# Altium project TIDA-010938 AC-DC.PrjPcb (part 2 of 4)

## Sheet TIDA-010938 AC-DC_Power Stage_BranchB.SchDoc
size 558 x 431 mm; Date: Not shown in title block; ApprovedBy: Not shown in title block; CheckedBy: Not shown in title block; Author: Not shown in title block; CompanyName: Not shown in title block; Engineer: Not shown in title block; Organization: Not shown in title block; Address1: Not shown in title block; Address2: Not shown in title block; Address3: Not shown in title block; Address4: Not shown in title block; DocumentNumber: 3; Revision: Use project parameter SCH_Rev; SheetNumber: 4; SheetTotal: 11; PageSetup: Record=PageOptions¦CenterHorizontal=True¦CenterVertical=True¦PrintScale=1.00¦XCorrection=1.00¦YCorrection=1.00¦PrintKind=0¦BorderSize=5000000¦LeftOffset=0¦BottomOffset=0¦Orientation=2¦PaperLength=1000¦PaperWidth=1000¦Scale=100¦PaperSource=15¦PrintQuality=600¦MediaType=1¦DitherType=10¦PaperKind=Letter¦PrintScaleMode=1

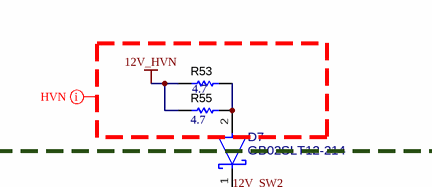
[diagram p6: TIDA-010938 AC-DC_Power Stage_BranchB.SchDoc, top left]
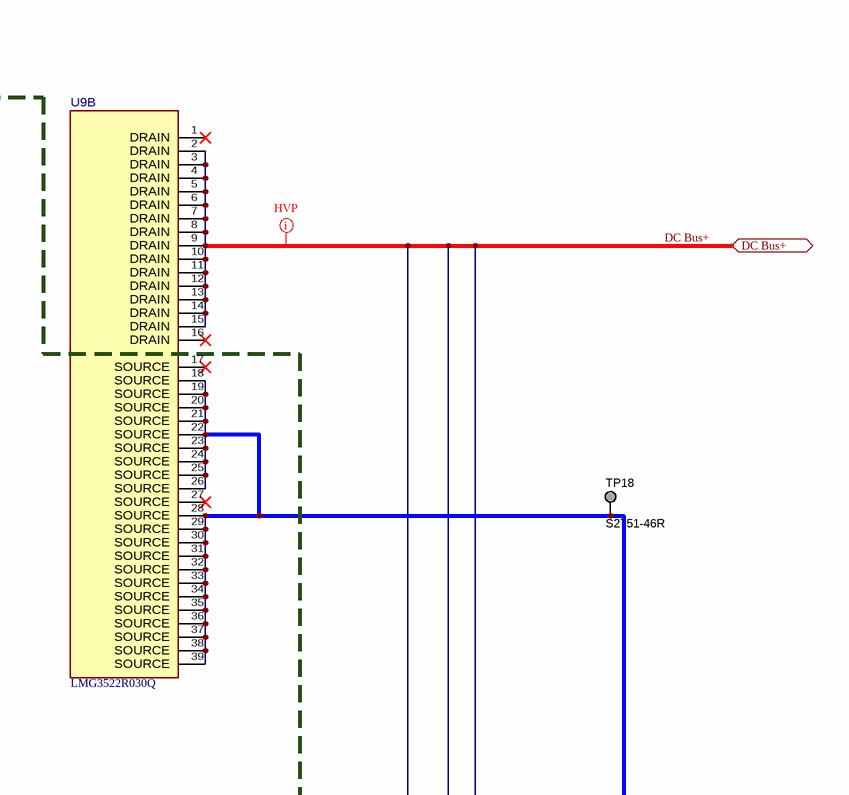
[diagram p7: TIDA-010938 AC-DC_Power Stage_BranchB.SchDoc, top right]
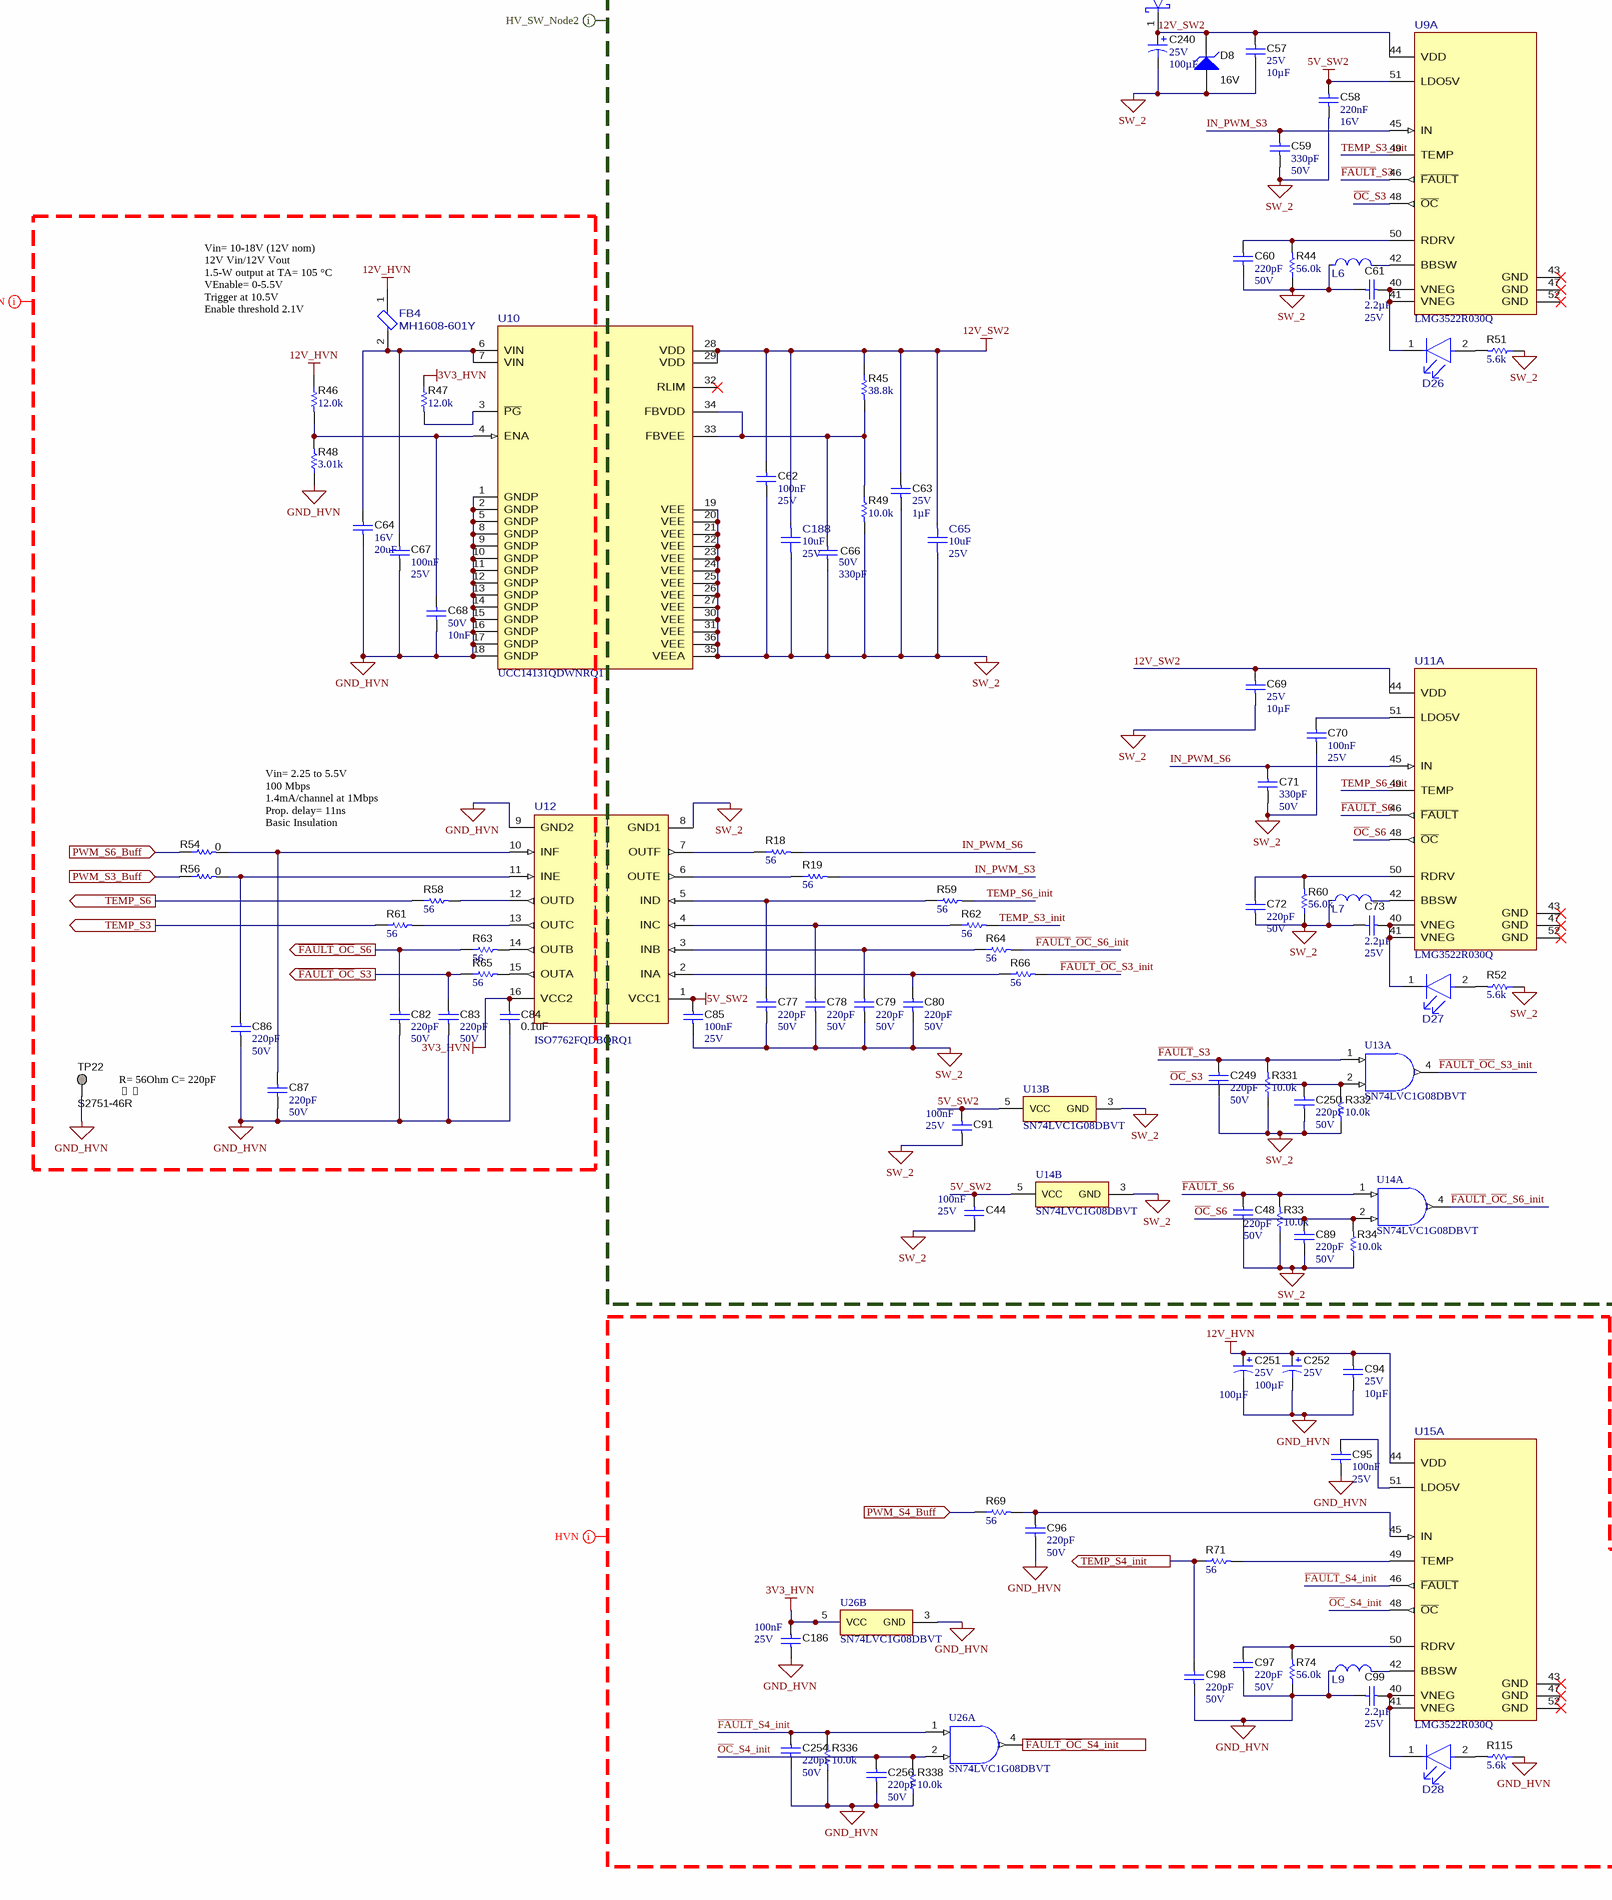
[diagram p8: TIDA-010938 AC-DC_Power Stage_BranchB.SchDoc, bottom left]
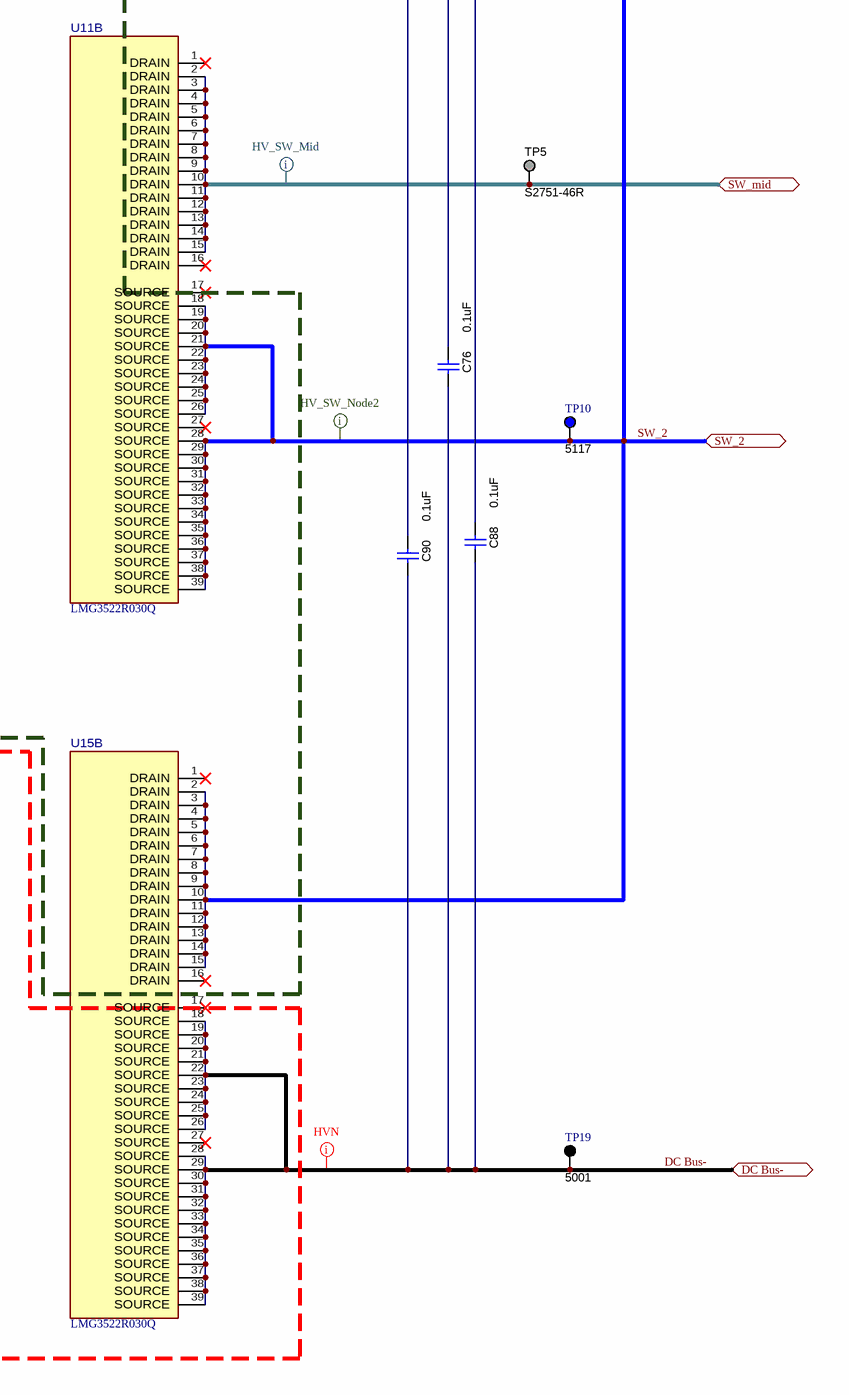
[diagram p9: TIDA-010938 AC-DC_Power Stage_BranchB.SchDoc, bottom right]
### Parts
C44  Cap_F: 100nF  VDC_V: 25V  [0603]  (hidden comment: 06033C104JAT2A)
C48  Cap_F: 220pF  VDC_V: 50V  [0603]  (hidden comment: GRM188R71H221KA01D)
C57  VDC_V: 25V  ValueDisplayed: 10µF  [1206_180]  (hidden comment: TMK316AB7106KLHT)
C58  Cap_F: 220nF  VDC_V: 16V  [0603]  (hidden comment: GRM188R71C224KA01D)
C59  Cap_F: 330pF  VDC_V: 50V  [0603]  (hidden comment: C0603C331K5RACTU)
C60  Cap_F: 220pF  VDC_V: 50V  [0603]  (hidden comment: GRM188R71H221KA01D)
C61  Cap_F: 2.2µF  VDC_V: 25V  [0805_HV]  (hidden comment: CGA4J3X7R1E225K125AB)
C62  Cap_F: 100nF  VDC_V: 25V  [0603]  (hidden comment: 06033C104JAT2A)
C63  VDC_V: 25V  ValueDisplayed: 1µF  [0603]  (hidden comment: TMK107BJ105KA-T)
C64  VDC_V: 16V  ValueDisplayed: 20uF  [0704]  (hidden comment: GRMJN7R61C206ME05)
C65  ValueDisplayed: 10uF  VDC_V: 25V  [FP-ZRB18AR61E106ME01L_0603-MFG]  (hidden comment: ZRB18AR61E106ME01L)
C66  VDC_V: 50V  ValueDisplayed: 330pF  [0603]  (hidden comment: GRM1885C1H331JA01D)
C67  Cap_F: 100nF  VDC_V: 25V  [0603]  (hidden comment: 06033C104JAT2A)
C68  VDC_V: 50V  Cap_F: 10nF  [0603]  (hidden comment: 885012206089)
C69  VDC_V: 25V  ValueDisplayed: 10µF  [1206_180]  (hidden comment: TMK316AB7106KLHT)
C70  Cap_F: 100nF  VDC_V: 25V  [0603]  (hidden comment: 06033C104JAT2A)
C71  Cap_F: 330pF  VDC_V: 50V  [0603]  (hidden comment: C0603C331K5RACTU)
C72  Cap_F: 220pF  VDC_V: 50V  [0603]  (hidden comment: GRM188R71H221KA01D)
C73  Cap_F: 2.2µF  VDC_V: 25V  [0805_HV]  (hidden comment: CGA4J3X7R1E225K125AB)
C76  ValueDisplayed: 0.1uF  [1812_254]  (hidden comment: C1812W104KDRACTU)
C77  Cap_F: 220pF  VDC_V: 50V  [0603]  (hidden comment: GRM188R71H221KA01D)
C78  Cap_F: 220pF  VDC_V: 50V  [0603]  (hidden comment: GRM188R71H221KA01D)
C79  Cap_F: 220pF  VDC_V: 50V  [0603]  (hidden comment: GRM188R71H221KA01D)
C80  Cap_F: 220pF  VDC_V: 50V  [0603]  (hidden comment: GRM188R71H221KA01D)
C82  Cap_F: 220pF  VDC_V: 50V  [0603]  (hidden comment: GRM188R71H221KA01D)
C83  Cap_F: 220pF  VDC_V: 50V  [0603]  (hidden comment: GRM188R71H221KA01D)
C84  ValueDisplayed: 0.1uF  [0603]  (hidden comment: 885012206095)
C85  Cap_F: 100nF  VDC_V: 25V  [0603]  (hidden comment: 06033C104JAT2A)
C86  Cap_F: 220pF  VDC_V: 50V  [0603]  (hidden comment: GRM188R71H221KA01D)
C87  Cap_F: 220pF  VDC_V: 50V  [0603]  (hidden comment: GRM188R71H221KA01D)
C88  ValueDisplayed: 0.1uF  [1812_254]  (hidden comment: C1812W104KDRACTU)
C89  Cap_F: 220pF  VDC_V: 50V  [0603]  (hidden comment: GRM188R71H221KA01D)
C90  ValueDisplayed: 0.1uF  [1812_254]  (hidden comment: C1812W104KDRACTU)
C91  Cap_F: 100nF  VDC_V: 25V  [0603]  (hidden comment: 06033C104JAT2A)
C94  VDC_V: 25V  ValueDisplayed: 10µF  [1206_180]  (hidden comment: TMK316AB7106KLHT)
C95  Cap_F: 100nF  VDC_V: 25V  [0603]  (hidden comment: 06033C104JAT2A)
C96  Cap_F: 220pF  VDC_V: 50V  [0603]  (hidden comment: GRM188R71H221KA01D)
C97  Cap_F: 220pF  VDC_V: 50V  [0603]  (hidden comment: GRM188R71H221KA01D)
C98  Cap_F: 220pF  VDC_V: 50V  [0603]  (hidden comment: GRM188R71H221KA01D)
C99  Cap_F: 2.2µF  VDC_V: 25V  [0805_HV]  (hidden comment: CGA4J3X7R1E225K125AB)
C186  Cap_F: 100nF  VDC_V: 25V  [0603]  (hidden comment: 06033C104JAT2A)
C188  ValueDisplayed: 10uF  VDC_V: 25V  [FP-ZRB18AR61E106ME01L_0603-MFG]  (hidden comment: ZRB18AR61E106ME01L)
C240  VDC_V: 25V  ValueDisplayed: 100µF  [UWT_630x770]  (hidden comment: UWT1E101MCL1GS)
C249  Cap_F: 220pF  VDC_V: 50V  [0603]  (hidden comment: GRM188R71H221KA01D)
C250  Cap_F: 220pF  VDC_V: 50V  [0603]  (hidden comment: GRM188R71H221KA01D)
C251  VDC_V: 25V  ValueDisplayed: 100µF  [UWT_630x770]  (hidden comment: UWT1E101MCL1GS)
C252  VDC_V: 25V  ValueDisplayed: 100µF  [UWT_630x770]  (hidden comment: UWT1E101MCL1GS)
C254  Cap_F: 220pF  VDC_V: 50V  [0603]  (hidden comment: GRM188R71H221KA01D)
C256  Cap_F: 220pF  VDC_V: 50V  [0603]  (hidden comment: GRM188R71H221KA01D)
D7  GB02SLT12-214  [FP-GB02SLT12-214_DO-214AA-MFG]
D8  value 16V  [SOD-123]  (hidden comment: BZT52C16-7-F)
D26  KG DELLS1.22-JGKH-24  [FP-KG DELLS1.22-JGKH-24_0603-MFG]  (value not drawn)
D27  KG DELLS1.22-JGKH-24  [FP-KG DELLS1.22-JGKH-24_0603-MFG]  (value not drawn)
D28  KG DELLS1.22-JGKH-24  [FP-KG DELLS1.22-JGKH-24_0603-MFG]  (value not drawn)
FB4  MH1608-601Y  [FP-MH1608-601Y_0603-MFG]
L6  SDEM20161T-4R7MS  [FP-SDEM20161T-4R7MS_SMD2-MFG]  (value not drawn)
L7  SDEM20161T-4R7MS  [FP-SDEM20161T-4R7MS_SMD2-MFG]  (value not drawn)
L9  SDEM20161T-4R7MS  [FP-SDEM20161T-4R7MS_SMD2-MFG]  (value not drawn)
R18  ValueDisplayed: 56  [0603]  (hidden comment: RG1608P-560-B-T5)
R19  ValueDisplayed: 56  [0603]  (hidden comment: RG1608P-560-B-T5)
R33  ValueDisplayed: 10.0k  [0603]  (hidden comment: RG1608P-103-B-T5)
R34  ValueDisplayed: 10.0k  [0603]  (hidden comment: RG1608P-103-B-T5)
R44  ValueDisplayed: 56.0k  [0603]  (hidden comment: RG1608P-563-B-T5)
R45  ValueDisplayed: 38.8k  [0603]  (hidden comment: RT0603DRE0738K8L)
R46  ValueDisplayed: 12.0k  [0603]  (hidden comment: ERJ-3EKF1202V)
R47  ValueDisplayed: 12.0k  [0603]  (hidden comment: ERJ-3EKF1202V)
R48  ValueDisplayed: 3.01k  [0603]  (hidden comment: RC0603FR-073K01L)
R49  ValueDisplayed: 10.0k  [0603]  (hidden comment: RG1608P-103-B-T5)
R51  ValueDisplayed: 5.6k  [0603]  (hidden comment: RC0603JR-075K6L)
R52  ValueDisplayed: 5.6k  [0603]  (hidden comment: RC0603JR-075K6L)
R53  ValueDisplayed: 4.7  [1206]  (hidden comment: CRCW12064R70JNEAHP)
R54  ValueDisplayed: 0  [0603]  (hidden comment: RCS06030000Z0EA)
R55  ValueDisplayed: 4.7  [1206]  (hidden comment: CRCW12064R70JNEAHP)
R56  ValueDisplayed: 0  [0603]  (hidden comment: RCS06030000Z0EA)
R58  ValueDisplayed: 56  [0603]  (hidden comment: RG1608P-560-B-T5)
R59  ValueDisplayed: 56  [0603]  (hidden comment: RG1608P-560-B-T5)
R60  ValueDisplayed: 56.0k  [0603]  (hidden comment: RG1608P-563-B-T5)
R61  ValueDisplayed: 56  [0603]  (hidden comment: RG1608P-560-B-T5)
R62  ValueDisplayed: 56  [0603]  (hidden comment: RG1608P-560-B-T5)
R63  ValueDisplayed: 56  [0603]  (hidden comment: RG1608P-560-B-T5)
R64  ValueDisplayed: 56  [0603]  (hidden comment: RG1608P-560-B-T5)
R65  ValueDisplayed: 56  [0603]  (hidden comment: RG1608P-560-B-T5)
R66  ValueDisplayed: 56  [0603]  (hidden comment: RG1608P-560-B-T5)
R69  ValueDisplayed: 56  [0603]  (hidden comment: RG1608P-560-B-T5)
R71  ValueDisplayed: 56  [0603]  (hidden comment: RG1608P-560-B-T5)
R74  ValueDisplayed: 56.0k  [0603]  (hidden comment: RG1608P-563-B-T5)
R115  ValueDisplayed: 5.6k  [0603]  (hidden comment: RC0603JR-075K6L)
R331  ValueDisplayed: 10.0k  [0603]  (hidden comment: RG1608P-103-B-T5)
R332  ValueDisplayed: 10.0k  [0603]  (hidden comment: RG1608P-103-B-T5)
R336  ValueDisplayed: 10.0k  [0603]  (hidden comment: RG1608P-103-B-T5)
R338  ValueDisplayed: 10.0k  [0603]  (hidden comment: RG1608P-103-B-T5)
TP5  S2751-46R  [Harwin_S2751-46R]  (no BOM)
TP10  5117  [Keystone5117]
TP18  S2751-46R  [Harwin_S2751-46R]  (no BOM)
TP19  5001  [Keystone5001]
TP22  S2751-46R  [Harwin_S2751-46R]  (no BOM)
U9  LMG3522R030Q  [RQS0052C-C01-MFG]  (parts A,B of 2)
U10  UCC14131QDWNRQ1  [DWJ0036A-MFG]
U11  LMG3522R030Q  [RQS0052C-C01-MFG]  (parts A,B of 2)
U12  ISO7762FQDBQRQ1  [DBQ0016A-MFG]
U13  SN74LVC1G08DBVT  [DBV0005A_N]  (parts A,B of 2)
U14  SN74LVC1G08DBVT  [DBV0005A_N]  (parts A,B of 2)
U15  LMG3522R030Q  [RQS0052C-C01-MFG]  (parts A,B of 2)
U26  SN74LVC1G08DBVT  [DBV0005A_N]  (parts A,B of 2)

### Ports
DC Bus+ (bidir), DC Bus- (bidir), PWM_S3_Buff (in), PWM_S4_Buff (in), PWM_S6_Buff (in), SW_2 (bidir), SW_mid (bidir), TEMP_S3 (out), TEMP_S4_init (out), TEMP_S6 (out), ~{FAULT}_~{OC}_S3 (out), ~{FAULT}_~{OC}_S4_init (out), ~{FAULT}_~{OC}_S6 (out)

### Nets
3V3_HVN: C84.2 C186.1 R47.1 U12.16(VCC2) U26.5(VCC)
5V_SW2: C44.1 C58.1 C85.2 C91.1 U9.51(LDO5V) U12.1(VCC1) U13.5(VCC) U14.5(VCC)
12V_HVN: C94.1 C251.1(+) C252.1(+) FB4.1 R46.1 R53.1 R55.1 U15.44(VDD)
12V_SW2: C57.1 C62.2 C63.2 C65.1 C69.1 C188.1 C240.1(+) D7.1(CATHODE) D8.1(K) R45.1 U9.44(VDD) U10.28(VDD) U10.29(VDD) U11.44(VDD)
DC Bus-: C64.1 C67.2 C68.1 C76.2 C82.1 C83.1 C84.1 C86.1 C87.1 C88.2 C90.2 C94.2 C95.1 C96.1 C97.1 C98.1 C99.2 C186.2 C251.2(-) C252.2(-) C254.1 C256.1 L9.1 R48.1 R74.1 R115.1 R336.1 R338.1 TP19.1 TP22.1 U10.1(GNDP) U10.2(GNDP) U10.5(GNDP) U10.8(GNDP) U10.9(GNDP) U10.10(GNDP) U10.11(GNDP) U10.12(GNDP) U10.13(GNDP) U10.14(GNDP) U10.15(GNDP) U10.16(GNDP) U10.17(GNDP) U10.18(GNDP) U12.9(GND2) U15.18(SOURCE) U15.19(SOURCE) U15.20(SOURCE) U15.21(SOURCE) U15.22(SOURCE) U15.23(SOURCE) U15.24(SOURCE) U15.25(SOURCE) U15.26(SOURCE) U15.28(SOURCE) U15.29(SOURCE) U15.30(SOURCE) U15.31(SOURCE) U15.32(SOURCE) U15.33(SOURCE) U15.34(SOURCE) U15.35(SOURCE) U15.36(SOURCE) U15.37(SOURCE) U15.38(SOURCE) U15.39(SOURCE) U26.3(GND) ; port DC Bus-  [also labelled GND_HVN]
SW_2: C44.2 C48.1 C57.2 C58.2 C59.1 C60.1 C61.2 C62.1 C63.1 C65.2 C66.2 C69.2 C70.1 C71.1 C72.1 C73.2 C77.1 C78.1 C79.1 C80.1 C85.1 C89.1 C91.2 C188.2 C240.2(-) C249.1 C250.1 D8.2(A) L6.1 L7.1 R33.1 R34.1 R44.1 R49.2 R51.1 R52.1 R60.1 R331.1 R332.1 TP10.1 TP18.1 U9.18(SOURCE) U9.19(SOURCE) U9.20(SOURCE) U9.21(SOURCE) U9.22(SOURCE) U9.23(SOURCE) U9.24(SOURCE) U9.25(SOURCE) U9.26(SOURCE) U9.28(SOURCE) U9.29(SOURCE) U9.30(SOURCE) U9.31(SOURCE) U9.32(SOURCE) U9.33(SOURCE) U9.34(SOURCE) U9.35(SOURCE) U9.36(SOURCE) U9.37(SOURCE) U9.38(SOURCE) U9.39(SOURCE) U10.19(VEE) U10.20(VEE) U10.21(VEE) U10.22(VEE) U10.23(VEE) U10.24(VEE) U10.25(VEE) U10.26(VEE) U10.27(VEE) U10.30(VEE) U10.31(VEE) U10.35(VEEA) U10.36(VEE) U11.18(SOURCE) U11.19(SOURCE) U11.20(SOURCE) U11.21(SOURCE) U11.22(SOURCE) U11.23(SOURCE) U11.24(SOURCE) U11.25(SOURCE) U11.26(SOURCE) U11.28(SOURCE) U11.29(SOURCE) U11.30(SOURCE) U11.31(SOURCE) U11.32(SOURCE) U11.33(SOURCE) U11.34(SOURCE) U11.35(SOURCE) U11.36(SOURCE) U11.37(SOURCE) U11.38(SOURCE) U11.39(SOURCE) U12.8(GND1) U13.3(GND) U14.3(GND) U15.2(DRAIN) U15.3(DRAIN) U15.4(DRAIN) U15.5(DRAIN) U15.6(DRAIN) U15.7(DRAIN) U15.8(DRAIN) U15.9(DRAIN) U15.10(DRAIN) U15.11(DRAIN) U15.12(DRAIN) U15.13(DRAIN) U15.14(DRAIN) U15.15(DRAIN) ; port SW_2
DC Bus+: C76.1 C88.1 C90.1 U9.2(DRAIN) U9.3(DRAIN) U9.4(DRAIN) U9.5(DRAIN) U9.6(DRAIN) U9.7(DRAIN) U9.8(DRAIN) U9.9(DRAIN) U9.10(DRAIN) U9.11(DRAIN) U9.12(DRAIN) U9.13(DRAIN) U9.14(DRAIN) U9.15(DRAIN) ; port DC Bus+
~{FAULT}_~{OC}_S3: C83.2 R65.1 ; port ~{FAULT}_~{OC}_S3
~{FAULT}_~{OC}_S3_init: R66.2 U13.4(Y)
~{FAULT}_~{OC}_S4_init: U26.4(Y) ; port ~{FAULT}_~{OC}_S4_init
~{FAULT}_~{OC}_S6: C82.2 R63.1 ; port ~{FAULT}_~{OC}_S6
~{FAULT}_~{OC}_S6_init: R64.2 U14.4(Y)
~{FAULT}_S3: C249.2 R331.2 U9.46(~{FAULT}) U13.1(A)
~{FAULT}_S4_init: C254.2 R336.2 U15.46(~{FAULT}) U26.1(A)
~{FAULT}_S6: C48.2 R33.2 U11.46(~{FAULT}) U14.1(A)
IN_PWM_S3: C59.2 R19.2 U9.45(IN)
IN_PWM_S6: C71.2 R18.2 U11.45(IN)
~{OC}_S3: C250.2 R332.2 U9.48(~{OC}) U13.2(B)
~{OC}_S4_init: C256.2 R338.2 U15.48(~{OC}) U26.2(B)
~{OC}_S6: C89.2 R34.2 U11.48(~{OC}) U14.2(B)
PWM_S3_Buff: R56.1 ; port PWM_S3_Buff
PWM_S4_Buff: R69.1 ; port PWM_S4_Buff
PWM_S6_Buff: R54.1 ; port PWM_S6_Buff
SW_mid: TP5.1 U11.2(DRAIN) U11.3(DRAIN) U11.4(DRAIN) U11.5(DRAIN) U11.6(DRAIN) U11.7(DRAIN) U11.8(DRAIN) U11.9(DRAIN) U11.10(DRAIN) U11.11(DRAIN) U11.12(DRAIN) U11.13(DRAIN) U11.14(DRAIN) U11.15(DRAIN) ; port SW_mid
TEMP_S3: R61.1 ; port TEMP_S3
TEMP_S3_init: R62.2 U9.49(TEMP)
TEMP_S4_init: C98.2 R71.1 ; port TEMP_S4_init
TEMP_S6: R58.1 ; port TEMP_S6
TEMP_S6_init: R59.2 U11.49(TEMP)
NetC60_2: C60.2 R44.2 U9.50(RDRV)
NetC61_1: C61.1 D26.1(CATHODE) U9.40(VNEG) U9.41(VNEG)
NetC64_2: C64.2 C67.1 FB4.2 U10.6(VIN) U10.7(VIN)
NetC66_1: C66.1 R45.2 R49.1 U10.33(FBVEE) U10.34(FBVDD)
NetC68_2: C68.2 R46.2 R48.2 U10.4(ENA)
NetC70_2: C70.2 U11.51(LDO5V)
NetC72_2: C72.2 R60.2 U11.50(RDRV)
NetC73_1: C73.1 D27.1(CATHODE) U11.40(VNEG) U11.41(VNEG)
NetC77_2: C77.2 R59.1 U12.5(IND)
NetC78_2: C78.2 R62.1 U12.4(INC)
NetC79_2: C79.2 R64.1 U12.3(INB)
NetC80_2: C80.2 R66.1 U12.2(INA)
NetC86_2: C86.2 R56.2 U12.11(INE)
NetC87_2: C87.2 R54.2 U12.10(INF)
NetC95_2: C95.2 U15.51(LDO5V)
NetC96_2: C96.2 R69.2 U15.45(IN)
NetC97_2: C97.2 R74.2 U15.50(RDRV)
NetC99_1: C99.1 D28.1(CATHODE) U15.40(VNEG) U15.41(VNEG)
NetD7_2: D7.2(ANODE) R53.2 R55.2
NetD26_2: D26.2(ANODE) R51.2
NetD27_2: D27.2(ANODE) R52.2
NetD28_2: D28.2(ANODE) R115.2
NetL6_2: L6.2 U9.42(BBSW)
NetL7_2: L7.2 U11.42(BBSW)
NetL9_2: L9.2 U15.42(BBSW)
NetR18_1: R18.1 U12.7(OUTF)
NetR19_1: R19.1 U12.6(OUTE)
NetR47_2: R47.2 U10.3(~{PG})
NetR58_2: R58.2 U12.12(OUTD)
NetR61_2: R61.2 U12.13(OUTC)
NetR63_2: R63.2 U12.14(OUTB)
NetR65_2: R65.2 U12.15(OUTA)
NetR71_2: R71.2 U15.49(TEMP)

Not connected (* = marked no-connect by the designer): U9 1(DRAIN)* 16(DRAIN)* 17(SOURCE)* 27(SOURCE)* 43(GND)* 47(GND)* 52(GND)*; U10 32(RLIM)*; U11 1(DRAIN)* 16(DRAIN)* 17(SOURCE)* 27(SOURCE)* 43(GND)* 47(GND)* 52(GND)*; U15 1(DRAIN)* 16(DRAIN)* 17(SOURCE)* 27(SOURCE)* 43(GND)* 47(GND)* 52(GND)*

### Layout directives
net class HV_SW_Node2: 5V_SW2, 12V_HVN, 12V_SW2, GND_HVN, IN_PWM_S3, IN_PWM_S6, SW_2, TEMP_S3_init, TEMP_S6_init, ~{FAULT}_S3, ~{FAULT}_S6, ~{FAULT}_~{OC}_S3_init, ~{FAULT}_~{OC}_S6_init, ~{OC}_S3, ~{OC}_S6
net class HVN: 3V3_HVN, 5V_SW2, 12V_HVN, 12V_SW2, DC Bus-, GND_HVN, IN_PWM_S3, IN_PWM_S6, SW_2, TEMP_S3_init, TEMP_S6_init, ~{FAULT}_S3, ~{FAULT}_S6, ~{FAULT}_~{OC}_S3_init, ~{FAULT}_~{OC}_S6_init, ~{OC}_S3, ~{OC}_S6
net class HV_SW_Mid: SW_mid
net class HVP: DC Bus+

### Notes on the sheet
- (near FB4) Vin= 10-18V (12V nom)
  12V Vin/12V Vout
  1.5-W output at TA= 105 °C
  VEnable= 0-5.5V
  Trigger at 10.5V
  Enable threshold 2.1V
- Vin= 2.25 to 5.5V
  100 Mbps
  1.4mA/channel at 1Mbps
  Prop. delay= 11ns
  Basic Insulation
- R= 56Ohm C= 220pF
  𝜏= 1.23e-8

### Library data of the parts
C44 C62 C67 C70 C85 C91 C95 C186 = CMP-0006752-5: CAP, CERM, 0.1 uF, 25 V, +/- 5%, X7R, 0603; Manufacturer: AVX; TaMin_C: -55°C; ESR_ohm: 0.05; Polarized: N; SizeAreaWB_mm2: 4.68; Value1: 0.05 ohm; U/M: EA; Value: 0.1uF; TaMax_C: 125°C; SizeZ_mm: 1; SizeX_mm: 1.6; SizeY_mm: 0.8; SizeArea_mm2: 1.28; AEC Category: Q200
C48 C60 C72 C77-C80 C82 C83 C86 C87 C89 C96-C98 C249 C250 C254 C256 = CMP-0007442-5: CAP, CERM, 220 pF, 50 V, +/- 10%, X7R, 0603; Manufacturer: MuRata; TaMin_C: -55°C; Polarized: N; SizeAreaWB_mm2: 4.68; Value1: Unknown; U/M: EA; Value: 220pF; TaMax_C: 125°C; SizeZ_mm: 1; SizeX_mm: 1.6; SizeY_mm: 0.8; SizeArea_mm2: 1.28; AEC Category: Q200
C57 C69 C94 = CMP-0750154-1: CAP, CERM, 10 µF, 25 V,+/- 10%, X7R, AEC-Q200 Grade 1, 1206; Manufacturer: Taiyo Yuden; AEC Qualified: Y; SizeZ_mm: 1.8; TaMax_C: 125°C; TaMin_C: -55°C; Cap_Case: 1206; Polarized: N; AEC Grade: 1; SizeY_mm: 1.6; Value: 10uF; SizeX_mm: 3.2; SizeAreaWB_mm2: 10.92; AEC Category: Q200; U/M: EA; SizeArea_mm2: 5.12
C58 = CMP-0007389-4: CAP, CERM, 0.22 uF, 16 V, +/- 10%, X7R, 0603; Manufacturer: MuRata; TaMin_C: -55°C; Polarized: N; SizeAreaWB_mm2: 4.68; Value1: Unknown; U/M: EA; Value: 0.22uF; TaMax_C: 125°C; SizeZ_mm: 1; SizeX_mm: 1.6; SizeY_mm: 0.8; SizeArea_mm2: 1.28; AEC Category: Q200
C59 C71 = CMP-0006921-4: CAP, CERM, 330 pF, 50 V, +/- 10%, X7R, 0603; Manufacturer: Kemet; TaMin_C: -55°C; Polarized: N; SizeAreaWB_mm2: 4.68; Value1: Unknown; U/M: EA; Value: 330pF; TaMax_C: 125°C; SizeZ_mm: 1; SizeX_mm: 1.6; SizeY_mm: 0.8; SizeArea_mm2: 1.28; AEC Category: Q200
C61 C73 C99 = CMP-0007975-2: CAP, CERM, 2.2 uF, 25 V, +/- 10%, X7R, AEC-Q200 Grade 1, 0805; Manufacturer: TDK; TaMin_C: -55°C; Polarized: N; SizeAreaWB_mm2: 6.75; Value1: Unknown; U/M: EA; Value: 2.2uF; TaMax_C: 125°C; SizeZ_mm: 1.45; SizeX_mm: 2; SizeY_mm: 1.25; Cap_Case: 0805; SizeArea_mm2: 2.5; AEC Qualified: Y; AEC Grade: 1; AEC Category: Q200
C63 = CMP-0086152-1: CAP, CERM, 1 µF, 25 V,+/- 10%, X5R, 0603; Manufacturer: Taiyo Yuden; SizeAreaWB_mm2: 4.68; SizeZ_mm: 1; U/M: EA; Green_REACh: Passed; Value: 1uF; AEC Qualified: N; TaMax_C: 85°C; Green_Lifecycle: Active; AEC Category: Q200; SizeArea_mm2: 1.28; TaMin_C: -55°C; SizeY_mm: 0.8; SizeX_mm: 1.6
C64 = CMP-0009474-2: CAP, CERM, 20 uF, 16 V, +/- 20%, X5R, 0704; Manufacturer: MuRata; TaMin_C: -55°C; Polarized: N; SizeAreaWB_mm2: 5.6; Value1: Unknown; U/M: EA; Value: 20uF; TaMax_C: 85°C; SizeZ_mm: 0.8; SizeX_mm: 1; SizeY_mm: 1.8; Cap_F: 20µF; AEC Category: Q200
C65 C188 = CMP-0094458-1: 10µF ±20% 25V Ceramic Capacitor X5R 0603 (1608 Metric); Manufacturer: Murata Electronics; SizeZ_mm: 1.2mm; AEC Qualified: No
C66 = CMP-0007209-4: CAP, CERM, 330 pF, 50 V, +/- 5%, C0G/NP0, 0603; Manufacturer: MuRata; TaMin_C: -55°C; Polarized: N; SizeAreaWB_mm2: 4.68; Value1: Unknown; U/M: EA; Value: 330pF; TaMax_C: 125°C; SizeZ_mm: 1; SizeX_mm: 1.6; SizeY_mm: 0.8; SizeArea_mm2: 1.28; AEC Category: Q200
C68 = CMP-0750039-1: CAP, CERM, 0.01 µF, 50 V,+/- 10%, X7R, 0603; Manufacturer: Wurth Elektronik; Polarized: N; AEC Category: Q200; TaMax_C: 125°C; SizeAreaWB_mm2: 4.68; Value: 0.01uF; SizeArea_mm2: 1.28; SizeY_mm: 0.8; SizeZ_mm: 1; ValueDisplayed: 0.01µF; SizeX_mm: 1.6; U/M: EA; TaMin_C: -55°C
C76 C88 C90 = CMP-0009326-2: CAP, CERM, 0.1 uF, 1000 V, +/- 10%, X7R, 1812; Manufacturer: Kemet; Polarized: N; Value: 0.1uF; U/M: EA; Cap_F: 100nF; Value1: Unknown; VDC_V: 1kV; Value2: 1000V; TaMin_C: -55°C; TaMax_C: 125°C; Cap_Case: 1812; AEC Category: Q200; SizeArea_mm2: 14.4; SizeAreaWB_mm2: 23.1; SizeX_mm: 4.5; SizeY_mm: 3.2; SizeZ_mm: 2.54
C84 = CMP-0006837-4: CAP, CERM, 0.1 uF, 50 V, +/- 10%, X7R, 0603; Manufacturer: Wurth Elektronik; TaMin_C: -55°C; Polarized: N; SizeAreaWB_mm2: 4.68; Value1: Unknown; U/M: EA; Value: 0.1uF; TaMax_C: 125°C; SizeZ_mm: 1; SizeX_mm: 1.6; SizeY_mm: 0.8; Value2: 50V; SizeArea_mm2: 1.28; CompType: Capacitor; Cap_F: 100nF; AEC Category: Q200
C240 C251 C252 = CMP-0081462-1: CAP, AL, 100 µF, 25 V, +/- 20%, SMD; Manufacturer: Nichicon; TaMin_C: -55°C; Polarized: Y; SizeAreaWB_mm2: 77.4; U/M: EA; Value: 100uF; TaMax_C: 105°C; SizeZ_mm: 8; SizeX_mm: 7; SizeY_mm: 6.6; Cap_Case: 6.3x7.7mm; SizeArea_mm2: 46.2; CompType: Capacitor; AEC Qualified: N; IRMS_A: 91mA; AEC Category: Q200
D7 = CMP-0095009-1: Diode Silicon Carbide Schottky 1200 V 2A (DC) Surface Mount DO-214AA; Manufacturer: GeneSiC Semiconductor; Max Surge Forward Current: 20A; ValueDisplayed: 122pF; Vf_V: 1.2kV; Peak Reverse Current: 1uA; SizeZ_mm: 2.44mm; AEC Qualified: No; TJmax_C: 175°C
D8 = CMP-0005769-4: Diode, Zener, 16 V, 500 mW, AEC-Q101, SOD-123; Manufacturer: Diodes Inc.; SizeZ_mm: 1.35; AEC Qualified: Y; SizeX_mm: 3.85; AEC Category: Q101; Power_W: 500mW; SizeY_mm: 1.7; Value1: 0.5W; SizeAreaWB_mm2: 13.095; SizeArea_mm2: 6.545; RJA_CperW: 338
D26-D28 = CMP-0093310-1: Standard LEDs - SMD Green TOPLED E 1608; Manufacturer: Osram Opto; AEC Grade: Grade 2; LambdaP: 572nm; SizeZ_mm: 0.7mm; LuminousFlux_PhiV: 0.016-0.0295lm; Luminous Intensity: 4.5-9.7mcd; LambdaD: 570nm; Tjmax_C: 125°C; Angle: 120°; Led Orientation: Top View; Forward Current: 2mA; Vf_V: 1.8V; AEC Qualified: Yes; Vr_V: 12V
FB4 = CMP-0037505-1: 600 Ohms @ 100 MHz 1 Power, Signal Line Ferrite Bead 0603 (1608 Metric) 1A 200mOhm; Manufacturer: Bourns; DCR_ohm: 0.2; SizeZ_mm: 1mm; AEC Qualified: No; Impedance At Frequency: 600Ω @ 100MHz; Test Frequency: 100MHz; Tolerance_%: 25%
L6 L7 L9 = CMP-0089347-1: 4.7µH Unshielded Inductor 1.1A 426mOhm Max 0806 (2016 Metric); Manufacturer: Cyntec; AEC Qualified: No; Material: Metal Dust; Isat: 1.26A; Test Frequency: 1MHz; DCR_ohm: 0.426; SizeZ_mm: 1mm; Tolerance_%: 20%
R18 R19 R58 R59 R61-R66 R69 R71 = CMP-0023572-3: RES, 56, 0.1%, 0.1 W, 0603; Manufacturer: Susumu Co Ltd; Power_W: 100mW; TempCo: 25 ppm/C; Value_Code: 56R0; U/M: EA; Value: 56; SizeX_mm: 1.6; SizeY_mm: 0.8; SizeZ_mm: 1; Value2: 0.1W; SizeArea_mm2: 1.28; VDC_V: 75V; AEC Category: Q200
R33 R34 R331 R332 R336 R338 = CMP-0023404-3: RES, 10.0 k, 0.1%, 0.1 W, 0603; Manufacturer: Susumu Co Ltd; Power_W: 100mW; TempCo: 25 ppm/C; Value_Code: 10k0; U/M: EA; Value: 10.0k; EIA_Code: E192; Res_ohm: 10k; SizeX_mm: 1.6; SizeY_mm: 0.8; SizeZ_mm: 1; Value2: 0.1W; SizeArea_mm2: 1.28; VDC_V: 75V; AEC Category: Q200
R44 R60 R74 = CMP-0023577-3: RES, 56.0 k, 0.1%, 0.1 W, 0603; Manufacturer: Susumu Co Ltd; Power_W: 100mW; TempCo: 25 ppm/C; Value_Code: 56k0; U/M: EA; Value: 56.0k; Res_ohm: 56k; SizeX_mm: 1.6; SizeY_mm: 0.8; SizeZ_mm: 1; Value2: 0.1W; SizeArea_mm2: 1.28; VDC_V: 75V; AEC Category: Q200
R45 = CMP-0025200-2: RES, 38.8 k, 0.5%, 0.1 W, 0603; Manufacturer: Yageo America; Power_W: 100mW; TempCo: 50 ppm/C; Value_Code: 38k8; U/M: EA; Value: 38.8k; EIA_Code: E192; SizeX_mm: 1.6; SizeY_mm: 0.8; SizeZ_mm: 1; Value2: 0.1W; SizeArea_mm2: 1.28; VDC_V: 75V; AEC Category: Q200
R46 R47 = CMP-0022685-3: RES, 12.0 k, 1%, 0.1 W, 0603; Manufacturer: Panasonic; Power_W: 100mW; TempCo: 100 ppm/C; Value_Code: 12k0; U/M: EA; Value: 12.0k; Res_ohm: 12k; SizeX_mm: 1.6; SizeY_mm: 0.8; SizeZ_mm: 1; Value2: 0.1W; SizeArea_mm2: 1.28; VDC_V: 75V; AEC Category: Q200
R48 = CMP-0023076-5: RES, 3.01 k, 1%, 0.1 W, 0603; Manufacturer: Yageo; Power_W: 100mW; TempCo: 100 ppm/C; Value_Code: 3k01; Value: 3.01k; EIA_Code: E96; SizeX_mm: 1.6; SizeY_mm: 0.8; SizeZ_mm: 1; Value2: 0.1W; SizeArea_mm2: 1.28; AEC Qualified: N; VDC_V: 75V; AEC Category: Q200; SizeAreaWB_mm2: 4.68
R49 = CMP-0023404-1: RES, 10.0 k, 0.1%, 0.1 W, 0603; Manufacturer: Susumu Co Ltd; Power_W: 100mW; TempCo: 25 ppm/C; Value_Code: 10k0; U/M: EA; Value: 10.0k; EIA_Code: E192; Res_ohm: 10k; SizeX_mm: 1.6; SizeY_mm: 0.8; SizeZ_mm: 1; Value2: 0.1W; SizeArea_mm2: 1.28; VDC_V: 75V; AEC Category: Q200
R51 R52 R115 = CMP-0025933-5: RES, 5.6 k, 5%, 0.1 W, 0603; Manufacturer: Yageo; Power_W: 100mW; TempCo: 100 ppm/C; Value_Code: 5k60; Value: 5.6k; EIA_Code: E24; SizeX_mm: 1.6; SizeY_mm: 0.8; SizeZ_mm: 1; Value2: 0.1W; SizeArea_mm2: 1.28; AEC Qualified: N; VDC_V: 75V; AEC Category: Q200; SizeAreaWB_mm2: 4.68
R53 R55 = CMP-0018694-3: RES, 4.7, 5%, 0.75 W, AEC-Q200 Grade 0, 1206; Manufacturer: Vishay-Dale; Power_W: 750mW; TempCo: 200 ppm/C; Value_Code: 4R70; Value: 4.7; EIA_Code: E24; SizeX_mm: 3.2; SizeY_mm: 1.6; SizeZ_mm: 1.35; Value2: 0.75W; SizeArea_mm2: 5.12; AEC Qualified: Y; AEC Grade: 0; AEC Category: Q200
R54 R56 = CMP-0081973-1: RES, 0, 0%, 0.25 W, AEC-Q200 Grade 0, 0603; Manufacturer: Vishay-Dale; SizeAreaWB_mm2: 4.68; SizeArea_mm2: 1.28; AEC Qualified: Y; AEC Category: Q200; Value: 0; SizeZ_mm: 1; SizeY_mm: 0.8; Power_W: 250mW; Value2: 0.25W; SizeX_mm: 1.6
TP5 TP18 TP22 = CMP-0003968-1: Test Point, SMT; Manufacturer: Harwin
TP10 = CMP-0055154-1: Test Point, Miniature, Blue, TH; Manufacturer: Keystone; CNHeader: FALSE; Green_Lifecycle: Active; Green_REACh: Passed; ContactFinish: Silver; CT: TRUE
TP19 = CMP-0055138-2: Test Point, Miniature, Black, TH; Manufacturer: Keystone Electronics; ContactFinish: Silver; CNHeader: FALSE; Green_Lifecycle: Active; Green_REACh: Passed; CT: TRUE
U9 U11 U15 = CMP-0089967-3: 650-V 30-mΩ GaN FET with Integrated Driver and Protection; Manufacturer: Texas Instruments; Standoff Height: 0mm; TJmax_C: +125°C; AEC Qualified: Yes; Nominal Supply Current: 16mA; Min Supply Voltage: 7.5V; SizeZ_mm: 1mm; AEC Category: Q200; Output Voltage: 520V; CompType: IC; Number Of Outputs: 1; Max Supply Voltage: 18V; AEC Grade: Grade 1
U10 = CMP-0033793-2: Automotive 1.5-W, 12-V VIN / 12-VOUT, 15-V VIN / 15-V VOUT, HighDensity, > 5-kVRMS, Isolated DC/DC Module; Manufacturer: Texas Instruments; SizeZ_mm: 3.55mm; AEC Qualified: Yes; AEC Grade: Grade 1; Max Supply Voltage: 18V; Min Supply Voltage: 9V; Nominal Supply Current: 200-270mA; Number Of Outputs: 2; Output Type: AdjustableProgrammable; Output Voltage: 10-18V; Standoff Height: 0.1mm; Switching Frequency: 18MHz; TaMax_C: +125°C; TaMin_C: -40°C; TJmax_C: +150°C; AEC Category: Q200; CompType: IC
U12 = CMP-0091060-1: Automotive, robust EMC, six-channel, 4/2, reinforced digital isolator 16-SSOP -40 to 125; Manufacturer: Texas Instruments; AEC Qualified: Yes; AEC Grade: Grade 1; Standoff Height: 0.11mm; Min Supply Voltage: 2.25V; SizeZ_mm: 1.75mm; TaMax_C: +125°C; Nominal Supply Current: 2.1-25.7mA; TJmax_C: +150°C; Max Supply Voltage: 5.5V; TaMin_C: -40°C
U13 U14 U26 = CMP-0051571-2: Single 2-Input Positive-AND Gate, DBV0005A, SMALL T&R; Manufacturer: Texas Instruments; Voltage(Nom)(V): 1.8,2.5,3.3,5; Bits(#): 1; Rating: Catalog; F @ Nom Voltage(Max)(Mhz): 150; 3-State Output: No; Gate Type: AND; Output Drive (IOL/IOH)(Max)(mA): 32/-32; Technology Family: LVC; Logic: True; VCC(Max)(V): 5.5; ICC @ Nom Voltage(Max)(mA): 0.01; VCC(Min)(V): 1.65; tpd @ Nom Voltage(Max)(ns): 4.5,6,4,5; Input Type: CMOS/TTL; Output Type: CMOS; AEC Category: Q200; AEC Qualified: N; CompType: IC

## Sheet TIDA-010938 AC-DC_EMI Protection Stage.SchDoc
size 431 x 279 mm; Date: Not shown in title block; ApprovedBy: Not shown in title block; CheckedBy: Not shown in title block; Author: Not shown in title block; CompanyName: Not shown in title block; Engineer: Not shown in title block; Organization: Not shown in title block; Address1: Not shown in title block; Address2: Not shown in title block; Address3: Not shown in title block; Address4: Not shown in title block; DocumentNumber: 5; Revision: Use project parameter SCH_Rev; SheetNumber: 6; SheetTotal: 11; PageSetup: Record=PageOptions¦CenterHorizontal=True¦CenterVertical=True¦PrintScale=1.00¦XCorrection=1.00¦YCorrection=1.00¦PrintKind=0¦BorderSize=5000000¦LeftOffset=0¦BottomOffset=0¦Orientation=2¦PaperLength=1000¦PaperWidth=1000¦Scale=100¦PaperSource=15¦PrintQuality=600¦MediaType=1¦DitherType=10¦PaperKind=Letter¦PrintScaleMode=1

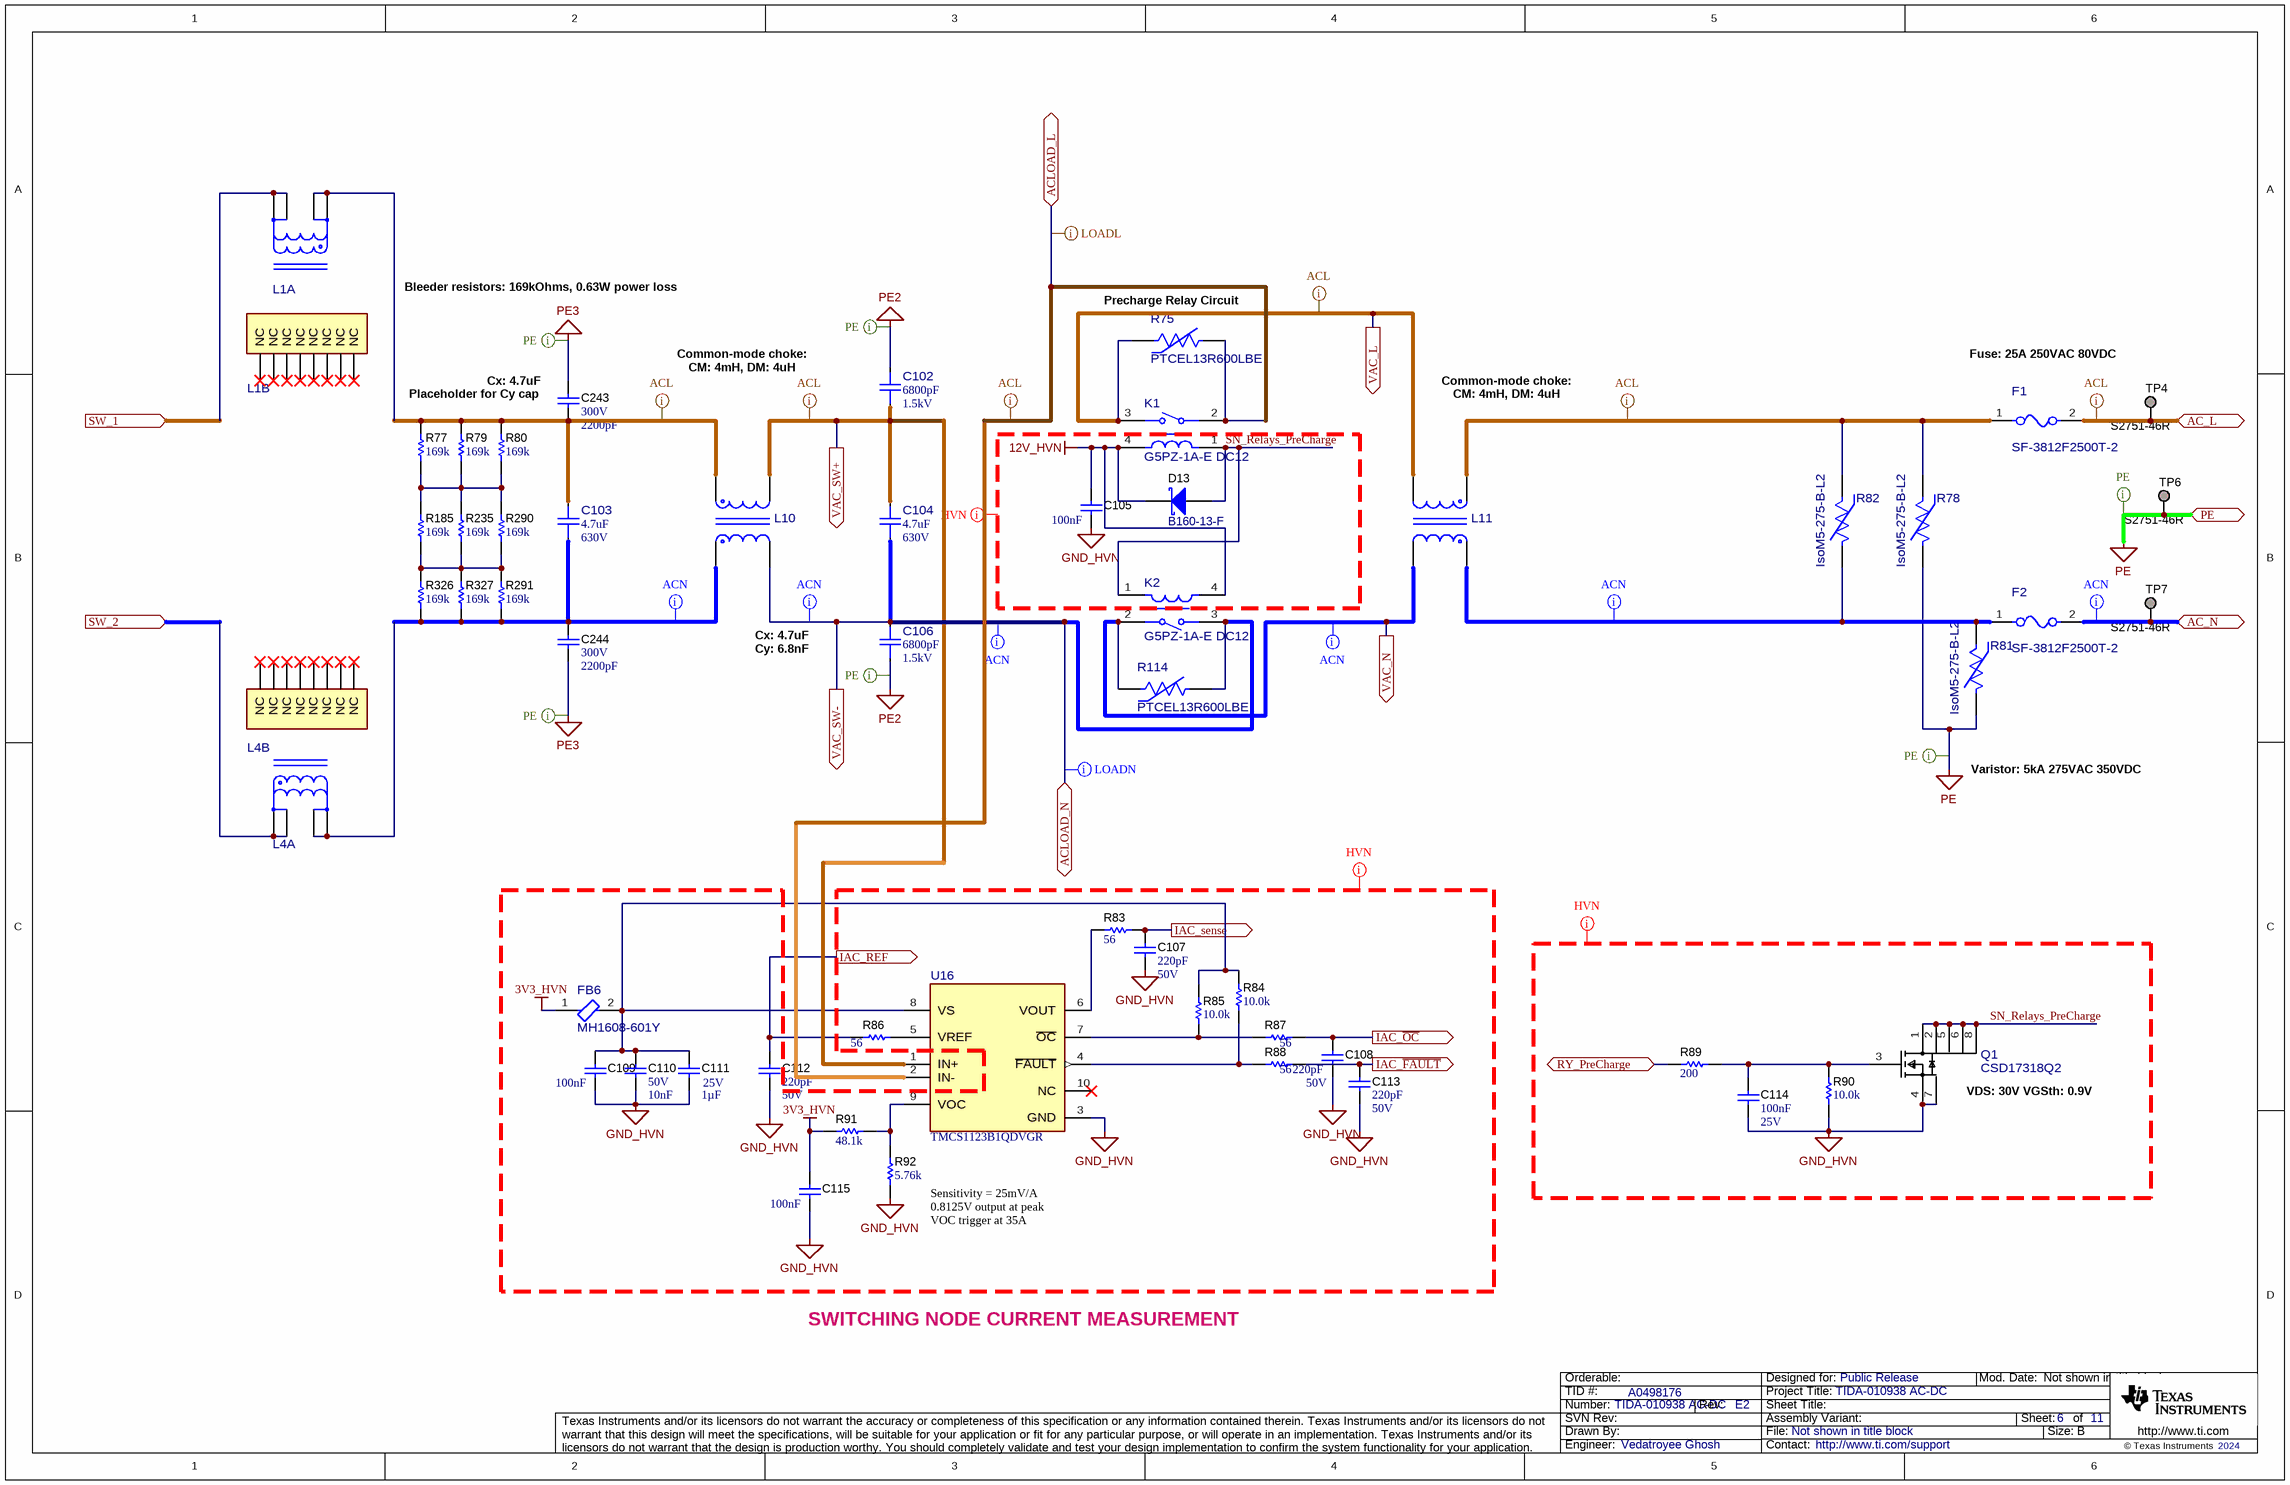
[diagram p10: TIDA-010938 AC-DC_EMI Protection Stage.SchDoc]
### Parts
C102  ValueDisplayed: 6800pF  VDC_V: 1.5kV  [FP-R413F168050T0K_RADIAL-MFG]  (hidden comment: R413F168050T0K)
C103  ValueDisplayed: 4.7uF  VDC_V: 630V  [FP-F862FY475K310ZV054_RADIAL-MFG]  (hidden comment: F862FY475K310ZV054)
C104  ValueDisplayed: 4.7uF  VDC_V: 630V  [FP-F862FY475K310ZV054_RADIAL-MFG]  (hidden comment: F862FY475K310ZV054)
C105  Cap_F: 100nF  [0603]  (hidden comment: GRM188R72A104KA35J)
C106  ValueDisplayed: 6800pF  VDC_V: 1.5kV  [FP-R413F168050T0K_RADIAL-MFG]  (hidden comment: R413F168050T0K)
C107  Cap_F: 220pF  VDC_V: 50V  [0603]  (hidden comment: GRM188R71H221KA01D)
C108  Cap_F: 220pF  VDC_V: 50V  [0603]  (hidden comment: GRM188R71H221KA01D)
C109  Cap_F: 100nF  [0603]  (hidden comment: GRM188R72A104KA35J)
C110  VDC_V: 50V  Cap_F: 10nF  [0603]  (hidden comment: 885012206089)
C111  VDC_V: 25V  ValueDisplayed: 1µF  [0603]  (hidden comment: TMK107BJ105KA-T)
C112  Cap_F: 220pF  VDC_V: 50V  [0603]  (hidden comment: GRM188R71H221KA01D)
C113  Cap_F: 220pF  VDC_V: 50V  [0603]  (hidden comment: GRM188R71H221KA01D)
C114  Cap_F: 100nF  VDC_V: 25V  [0603]  (hidden comment: 06033C104JAT2A)
C115  Cap_F: 100nF  [0603]  (hidden comment: GRM188R72A104KA35J)
C243  VDC_V: 300V  ValueDisplayed: 2200pF  [E_900x700x900]  (hidden comment: DE6E3KJ222MN3A)
C244  VDC_V: 300V  ValueDisplayed: 2200pF  [E_900x700x900]  (hidden comment: DE6E3KJ222MN3A)
D13  B160-13-F  [SMA]
F1  SF-3812F2500T-2  [FP-SF-3812F2500T-2_SMD2-MFG]
F2  SF-3812F2500T-2  [FP-SF-3812F2500T-2_SMD2-MFG]
FB6  MH1608-601Y  [FP-MH1608-601Y_0603-MFG]
K1  G5PZ-1A-E DC12  [FP-G5PZ-1A-E DC12_PTH_RELAY_23MM8_10MM3-MFG]
K2  G5PZ-1A-E DC12  [FP-G5PZ-1A-E DC12_PTH_RELAY_23MM8_10MM3-MFG]
L1  145453  [FP-145453_PTH12-MFG]  (value not drawn)  (parts A,B of 2)
L4  145453  [FP-145453_PTH12-MFG]  (value not drawn)  (parts A,B of 2)
L10  047708  [FP-047708_PTH4-MFG]  (value not drawn)
L11  047708  [FP-047708_PTH4-MFG]  (value not drawn)
Q1  CSD17318Q2  [FP-CSD17318Q2_WSON6-MFG]
R75  PTCEL13R600LBE  [FP-PTCEL13R600LBE_RADIAL-MFG]
R77  ValueDisplayed: 169k  [1206]  (hidden comment: ERJ-8ENF1693V)
R78  IsoM5-275-B-L2  [FP-IsoM5-275-B-L2_RADIAL-MFG]
R79  ValueDisplayed: 169k  [1206]  (hidden comment: ERJ-8ENF1693V)
R80  ValueDisplayed: 169k  [1206]  (hidden comment: ERJ-8ENF1693V)
R81  IsoM5-275-B-L2  [FP-IsoM5-275-B-L2_RADIAL-MFG]
R82  IsoM5-275-B-L2  [FP-IsoM5-275-B-L2_RADIAL-MFG]
R83  ValueDisplayed: 56  [0603]  (hidden comment: RG1608P-560-B-T5)
R84  ValueDisplayed: 10.0k  [0603]  (hidden comment: RG1608P-103-B-T5)
R85  ValueDisplayed: 10.0k  [0603]  (hidden comment: RG1608P-103-B-T5)
R86  ValueDisplayed: 56  [0603]  (hidden comment: RG1608P-560-B-T5)
R87  ValueDisplayed: 56  [0603]  (hidden comment: RG1608P-560-B-T5)
R88  ValueDisplayed: 56  [0603]  (hidden comment: RG1608P-560-B-T5)
R89  ValueDisplayed: 200  [0603]  (hidden comment: RT0603DRE07200RL)
R90  ValueDisplayed: 10.0k  [0603]  (hidden comment: RG1608P-103-B-T5)
R91  ValueDisplayed: 48.1k  [0603]  (hidden comment: RT0603BRD0748K1L)
R92  ValueDisplayed: 5.76k  [0603]  (hidden comment: RT0603DRE075K76L)
R114  PTCEL13R600LBE  [FP-PTCEL13R600LBE_RADIAL-MFG]
R185  ValueDisplayed: 169k  [1206]  (hidden comment: ERJ-8ENF1693V)
R235  ValueDisplayed: 169k  [1206]  (hidden comment: ERJ-8ENF1693V)
R290  ValueDisplayed: 169k  [1206]  (hidden comment: ERJ-8ENF1693V)
R291  ValueDisplayed: 169k  [1206]  (hidden comment: ERJ-8ENF1693V)
R326  ValueDisplayed: 169k  [1206]  (hidden comment: ERJ-8ENF1693V)
R327  ValueDisplayed: 169k  [1206]  (hidden comment: ERJ-8ENF1693V)
TP4  S2751-46R  [Harwin_S2751-46R]  (no BOM)
TP6  S2751-46R  [Harwin_S2751-46R]  (no BOM)
TP7  S2751-46R  [Harwin_S2751-46R]  (no BOM)
U16  TMCS1123B1QDVGR  [DVG0010A-MFG]

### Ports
AC_L (bidir), AC_N (bidir), ACLOAD_L (bidir), ACLOAD_N (bidir), IAC_REF (out), IAC_sense (out), IAC_~{FAULT} (out), IAC_~{OC} (out), PE (bidir), RY_PreCharge (bidir), SW_1 (in), SW_2 (in), VAC_L (out), VAC_N (out), VAC_SW+ (out), VAC_SW- (out)

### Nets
3V3_HVN: C115.1 FB6.1 R91.1
12V_HVN: C105.1 D13.1(K) K1.4 K2.4
GND_HVN: C105.2 C107.1 C108.1 C109.2 C110.2 C111.2 C112.1 C113.1 C114.2 C115.2 Q1.4(S) Q1.7(S) R90.2 R92.1 U16.3(GND)  [project net DC Bus-]
PE: R78.1 R81.1 TP6.1 ; port PE
PE2: C102.2 C106.1
PE3: C243.1 C244.2
SW_1: L1.11 L1.12 ; port SW_1
SW_2: L4.1 L4.2 ; port SW_2
AC_L: F1.2 TP4.1 ; port AC_L
AC_N: F2.2 TP7.1 ; port AC_N
ACLOAD_L: K1.2 R75.2 U16.2(IN-) ; port ACLOAD_L
ACLOAD_N: C104.1 C106.2 K2.3 L10.EI R114.2 ; port VAC_SW-, port ACLOAD_N
IAC_~{FAULT}: C113.2 R88.2 ; port IAC_~{FAULT}
IAC_~{OC}: C108.2 R87.2 ; port IAC_~{OC}
IAC_REF: C112.2 R86.1 ; port IAC_REF
IAC_sense: C107.2 R83.2 ; port IAC_sense
RY_PreCharge: R89.1 ; port RY_PreCharge
SN_Relays_PreCharge: D13.2(A) K1.1 K2.1 Q1.1(D) Q1.2(D) Q1.5(D) Q1.6(D) Q1.8(D)
VAC_L: K1.3 L11.EII R75.1 ; port VAC_L
VAC_N: K2.2 L11.EI R114.1 ; port VAC_N
VAC_SW+: C102.1 C104.2 L10.EII U16.1(IN+) ; port VAC_SW+
NetC103_1: C103.1 C244.1 L4.11 L4.12 L10.AI R291.1 R326.1 R327.1
NetC103_2: C103.2 C243.2 L1.1 L1.2 L10.AII R77.2 R79.2 R80.2
NetC109_1: C109.1 C110.1 C111.1 FB6.2 R84.1 R85.1 U16.8(VS)
NetC114_1: C114.1 Q1.3(G) R89.2 R90.1
NetF1_1: F1.1 L11.AII R78.2 R82.2
NetF2_1: F2.1 L11.AI R81.2 R82.1
NetR77_1: R77.1 R79.1 R80.1 R185.2 R235.2 R290.2
NetR83_1: R83.1 U16.6(VOUT)
NetR84_2: R84.2 R88.1 U16.4(~{FAULT})
NetR85_2: R85.2 R87.1 U16.7(~{OC})
NetR86_2: R86.2 U16.5(VREF)
NetR91_2: R91.2 R92.2 U16.9(VOC)
NetR185_1: R185.1 R235.1 R290.1 R291.2 R326.2 R327.2

Not connected (* = marked no-connect by the designer): L1 3(NC)* 4(NC)* 5(NC)* 6(NC)* 7(NC)* 8(NC)* 9(NC)* 10(NC)*; L4 3(NC)* 4(NC)* 5(NC)* 6(NC)* 7(NC)* 8(NC)* 9(NC)* 10(NC)*; U16 10(NC)*

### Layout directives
net class HVN: 3V3_HVN, 12V_HVN, GND_HVN, SN_Relays_PreCharge
net class ACL: AC_L, ACLOAD_L, NetC103_2, NetF1_1, VAC_L, VAC_SW+
net class ACN: AC_N, ACLOAD_N, NetC103_1, NetF2_1, VAC_N
net class PE: PE, PE2, PE3
net class LOADL: ACLOAD_L

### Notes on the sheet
- Bleeder resistors: 169kOhms, 0.63W power loss
- (near R75) Precharge Relay Circuit
- Common-mode choke:
- CM: 4mH, DM: 4uH
- Fuse: 25A 250VAC 80VDC
- Placeholder for Cy cap
- (near C243) Cx: 4.7uF
- Cx: 4.7uF
- Cy: 6.8nF
- Varistor: 5kA 275VAC 350VDC
- (near Q1) VDS: 30V VGSth: 0.9V
- (near R92) Sensitivity = 25mV/A
  0.8125V output at peak
  VOC trigger at 35A
- SWITCHING NODE CURRENT MEASUREMENT

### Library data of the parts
C102 C106 = CMP-0042924-1: 6800 pF Film Capacitor 300V 1500V (1.5kV) Polypropylene (PP), Metallized Radial; Manufacturer: KEMET; AEC Grade: Grade 1; AEC Qualified: Yes; Cap_F: 6.8nF; SizeZ_mm: 12.1mm; Tolerance_%: 10%; VAC_Y: Y2; Value: 6.8nF
C103 C104 = CMP-0038396-1: 4.7 µF Film Capacitor 310V 630V Polypropylene (PP), Metallized Radial; Manufacturer: KEMET; AEC Grade: Grade 2; AEC Qualified: Yes; Cap_F: 4.7µF; SizeZ_mm: 37mm; Tolerance_%: 10%; VAC_X: X2; Value: 4.7µF
C105 C109 C115 = CMP-0007470-5: CAP, CERM, 0.1 uF, 100 V, +/- 10%, X7R, 0603; Manufacturer: MuRata; TaMin_C: -55°C; Polarized: N; SizeAreaWB_mm2: 4.68; Value1: Unknown; U/M: EA; Value: 0.1uF; TaMax_C: 125°C; SizeZ_mm: 1; SizeX_mm: 1.6; SizeY_mm: 0.8; Value2: 100V; SizeArea_mm2: 1.28; AEC Category: Q200
C107 C108 C112 C113 = CMP-0007442-5: as C48 on sheet TIDA-010938 AC-DC_Power Stage_BranchB
C110 = CMP-0750039-1: as C68 on sheet TIDA-010938 AC-DC_Power Stage_BranchB
C111 = CMP-0086152-1: as C63 on sheet TIDA-010938 AC-DC_Power Stage_BranchB
C114 = CMP-0006752-5: as C44 on sheet TIDA-010938 AC-DC_Power Stage_BranchB
C243 C244 = CMP-0009613-2: CAP, CERM, 2200 pF, 300 V, +/- 20%, E, TH, 2- Leads, Body 9x7mm, Pin Spacing 7.5mm; Manufacturer: MuRata; TaMin_C: -40°C; Polarized: N; SizeAreaWB_mm2: 99; Value1: Unknown; U/M: EA; Value: 2200pF; TaMax_C: 125°C; SizeZ_mm: 12; SizeX_mm: 9; SizeY_mm: 7; Cap_Case: 9x7x9mm; SizeArea_mm2: 63; Cap_F: 2.2nF; AEC Category: Q200
D13 = CMP-0028389-2: Diode, Schottky, 60 V, 1 A, SMA; Manufacturer: Diodes Inc.; Green_Lifecycle: Not Set; SizeAreaWB_mm2: 37.3428; Green_REACh: Incomplete; TJmax_C: 150°C; AEC Category: Q101; SizeZ_mm: 2.87; RJC_CperW: 20; Io_A: 1A; SizeArea_mm2: 16.3228; Vf_V: 700mV; Value2: 0.7V; SizeY_mm: 2.92; Vr_V: 60V; SizeX_mm: 5.59; Value: 60V
F1 F2 = CMP-0122960-1: 25 A 250 V AC 80 V DC Fuse Board Mount (Cartridge Style Excluded) Surface Mount 2-SMD, Square End Block; Manufacturer: Bourns; Interrupt_AC: 100A; Interrupt_DC: 130A; MeltingTyp: 625A2Sec; SizeZ_mm: 3.3mm; VAC_V: 250V; Fuse Speed: Fast; AEC Qualified: No; Fuse Current: 25A; Res_ohm: 0.0024Ω
FB6 = CMP-0037505-1: as FB4 on sheet TIDA-010938 AC-DC_Power Stage_BranchB
K1 K2 = CMP-0093993-1: General Purpose Relay SPST-NO (1 Form A) 12VDC Coil Through Hole; Manufacturer: Omron; TaMax_C: +70°C; Coil Current_A: 44.1mA; Standoff Height: 0.5mm; Switching Current: 20A; Coil Voltage_VDC: 12V; Coil Resistance: 272Ω; AEC Qualified: No; TaMin_C: -40°C; Coil Type: Non-Latching; SizeZ_mm: 25mm; Coil Power_W: 530mW
L1 L4 = CMP-0123013-1: PFC Inductor 87µH ±10% 35A 13 mΩ; Manufacturer: Bourns; AEC Qualified: No; DCR_ohm: 14.3m; SizeZ_mm: 47.9mm; Value: 87uH; Test Frequency: 100kHz
L10 L11 = CMP-0123012-1: Common Mode Choke 4mH ±30%; Manufacturer: Kaschke Components; DCR_ohm: 12m; SizeZ_mm: 40mm; AEC Qualified: No
Q1 = CMP-0076725-1: 30-V N-Channel NexFET™ Power MOSFET; Manufacturer: Texas Instruments; VdsMax_V: 30V; SizeZ_mm: 0.8mm; ChMode: False; QgTyp_nC: 6nC @ 4.5V; Rdson45_ohm: 0.0139; Vgs_V: 10V; AEC Qualified: No; IdsMax_A: 10A
R75 R114 = CMP-0097004-1: PTCEL Series 500 V 60 Ohm ±30 % Radial Inrush Current Limiter PTC Thermistor; Manufacturer: Vishay Bccomponents; Value: 60Ω; SizeZ_mm: 17mm; AEC Qualified: Yes; Hold Current: 120mA; Tolerance_%: 30%; VDC_V: 500V; AEC Grade: Grade 2
R77 R79 R80 R185 R235 R290 R291 R326 R327 = CMP-0017399-3: RES, 169 k, 1%, 0.25 W, AEC-Q200 Grade 0, 1206; Manufacturer: Panasonic; Power_W: 250mW; TempCo: 100 ppm/C; Value: 169k; EIA_Code: E96; SizeX_mm: 3.2; SizeY_mm: 1.6; SizeZ_mm: 1.35; Value2: 0.25W; SizeArea_mm2: 5.12; AEC Qualified: Y; VDC_V: 200V; AEC Category: Q200; AEC Grade: 0; SizeAreaWB_mm2: 10.92
R78 R81 R82 = CMP-0096768-1: 5 kA Varistor 1 Circuit Through Hole Disc 17mm; Manufacturer: Bourns; AEC Qualified: No; SizeZ_mm: 23mm; VDC_V: 350V; Vc: 100A; ValueDisplayed: 40pF; Clamping Voltage: 730V
R83 R86-R88 = CMP-0023572-3: as R18 on sheet TIDA-010938 AC-DC_Power Stage_BranchB
R84 R85 R90 = CMP-0023404-1: as R49 on sheet TIDA-010938 AC-DC_Power Stage_BranchB
R89 = CMP-0024912-2: RES, 200, 0.5%, 0.1 W, 0603; Manufacturer: Yageo America; Power_W: 100mW; TempCo: 50 ppm/C; Value_Code: 200R; U/M: EA; Value: 200; EIA_Code: E192; SizeX_mm: 1.6; SizeY_mm: 0.8; SizeZ_mm: 1; Value2: 0.1W; SizeArea_mm2: 1.28; VDC_V: 75V; AEC Category: Q200
R91 = CMP-0024274-3: RES, 48.1 k, 0.1%, 0.1 W, 0603; Manufacturer: Yageo America; Power_W: 100mW; TempCo: 25 ppm/C; Value_Code: 48k1; U/M: EA; Value: 48.1k; EIA_Code: E192; SizeX_mm: 1.6; SizeY_mm: 0.8; SizeZ_mm: 1; Value2: 0.1W; SizeArea_mm2: 1.28; VDC_V: 75V; AEC Category: Q200
R92 = CMP-0025444-3: RES, 5.76 k, 0.5%, 0.1 W, 0603; Manufacturer: Yageo America; Power_W: 100mW; TempCo: 50 ppm/C; Value_Code: 5k76; U/M: EA; Value: 5.76k; EIA_Code: E192; SizeX_mm: 1.6; SizeY_mm: 0.8; SizeZ_mm: 1; Value2: 0.1W; SizeArea_mm2: 1.28; VDC_V: 75V; AEC Category: Q200
TP4 TP6 TP7 = CMP-0003968-1: Test Point, SMT; Manufacturer: Harwin
U16 = CMP-0096051-1: Manufacturer: Texas Instruments; Standoff Height: 0.1mm; SizeZ_mm: 2.65mm; AEC Qualified: No

## Sheet TIDA-010938 AC-DC_Voltage Measurement.SchDoc
size 431 x 279 mm; Date: Not shown in title block; ApprovedBy: Not shown in title block; CheckedBy: Not shown in title block; Author: Not shown in title block; CompanyName: Not shown in title block; Engineer: Not shown in title block; Organization: Not shown in title block; Address1: Not shown in title block; Address2: Not shown in title block; Address3: Not shown in title block; Address4: Not shown in title block; DocumentNumber: 6; Revision: Use project parameter SCH_Rev; SheetNumber: 7; SheetTotal: 11; PageSetup: Record=PageOptions¦CenterHorizontal=True¦CenterVertical=True¦PrintScale=1.00¦XCorrection=1.00¦YCorrection=1.00¦PrintKind=0¦BorderSize=5000000¦LeftOffset=0¦BottomOffset=0¦Orientation=2¦PaperLength=1000¦PaperWidth=1000¦Scale=100¦PaperSource=15¦PrintQuality=600¦MediaType=1¦DitherType=10¦PaperKind=Letter¦PrintScaleMode=1

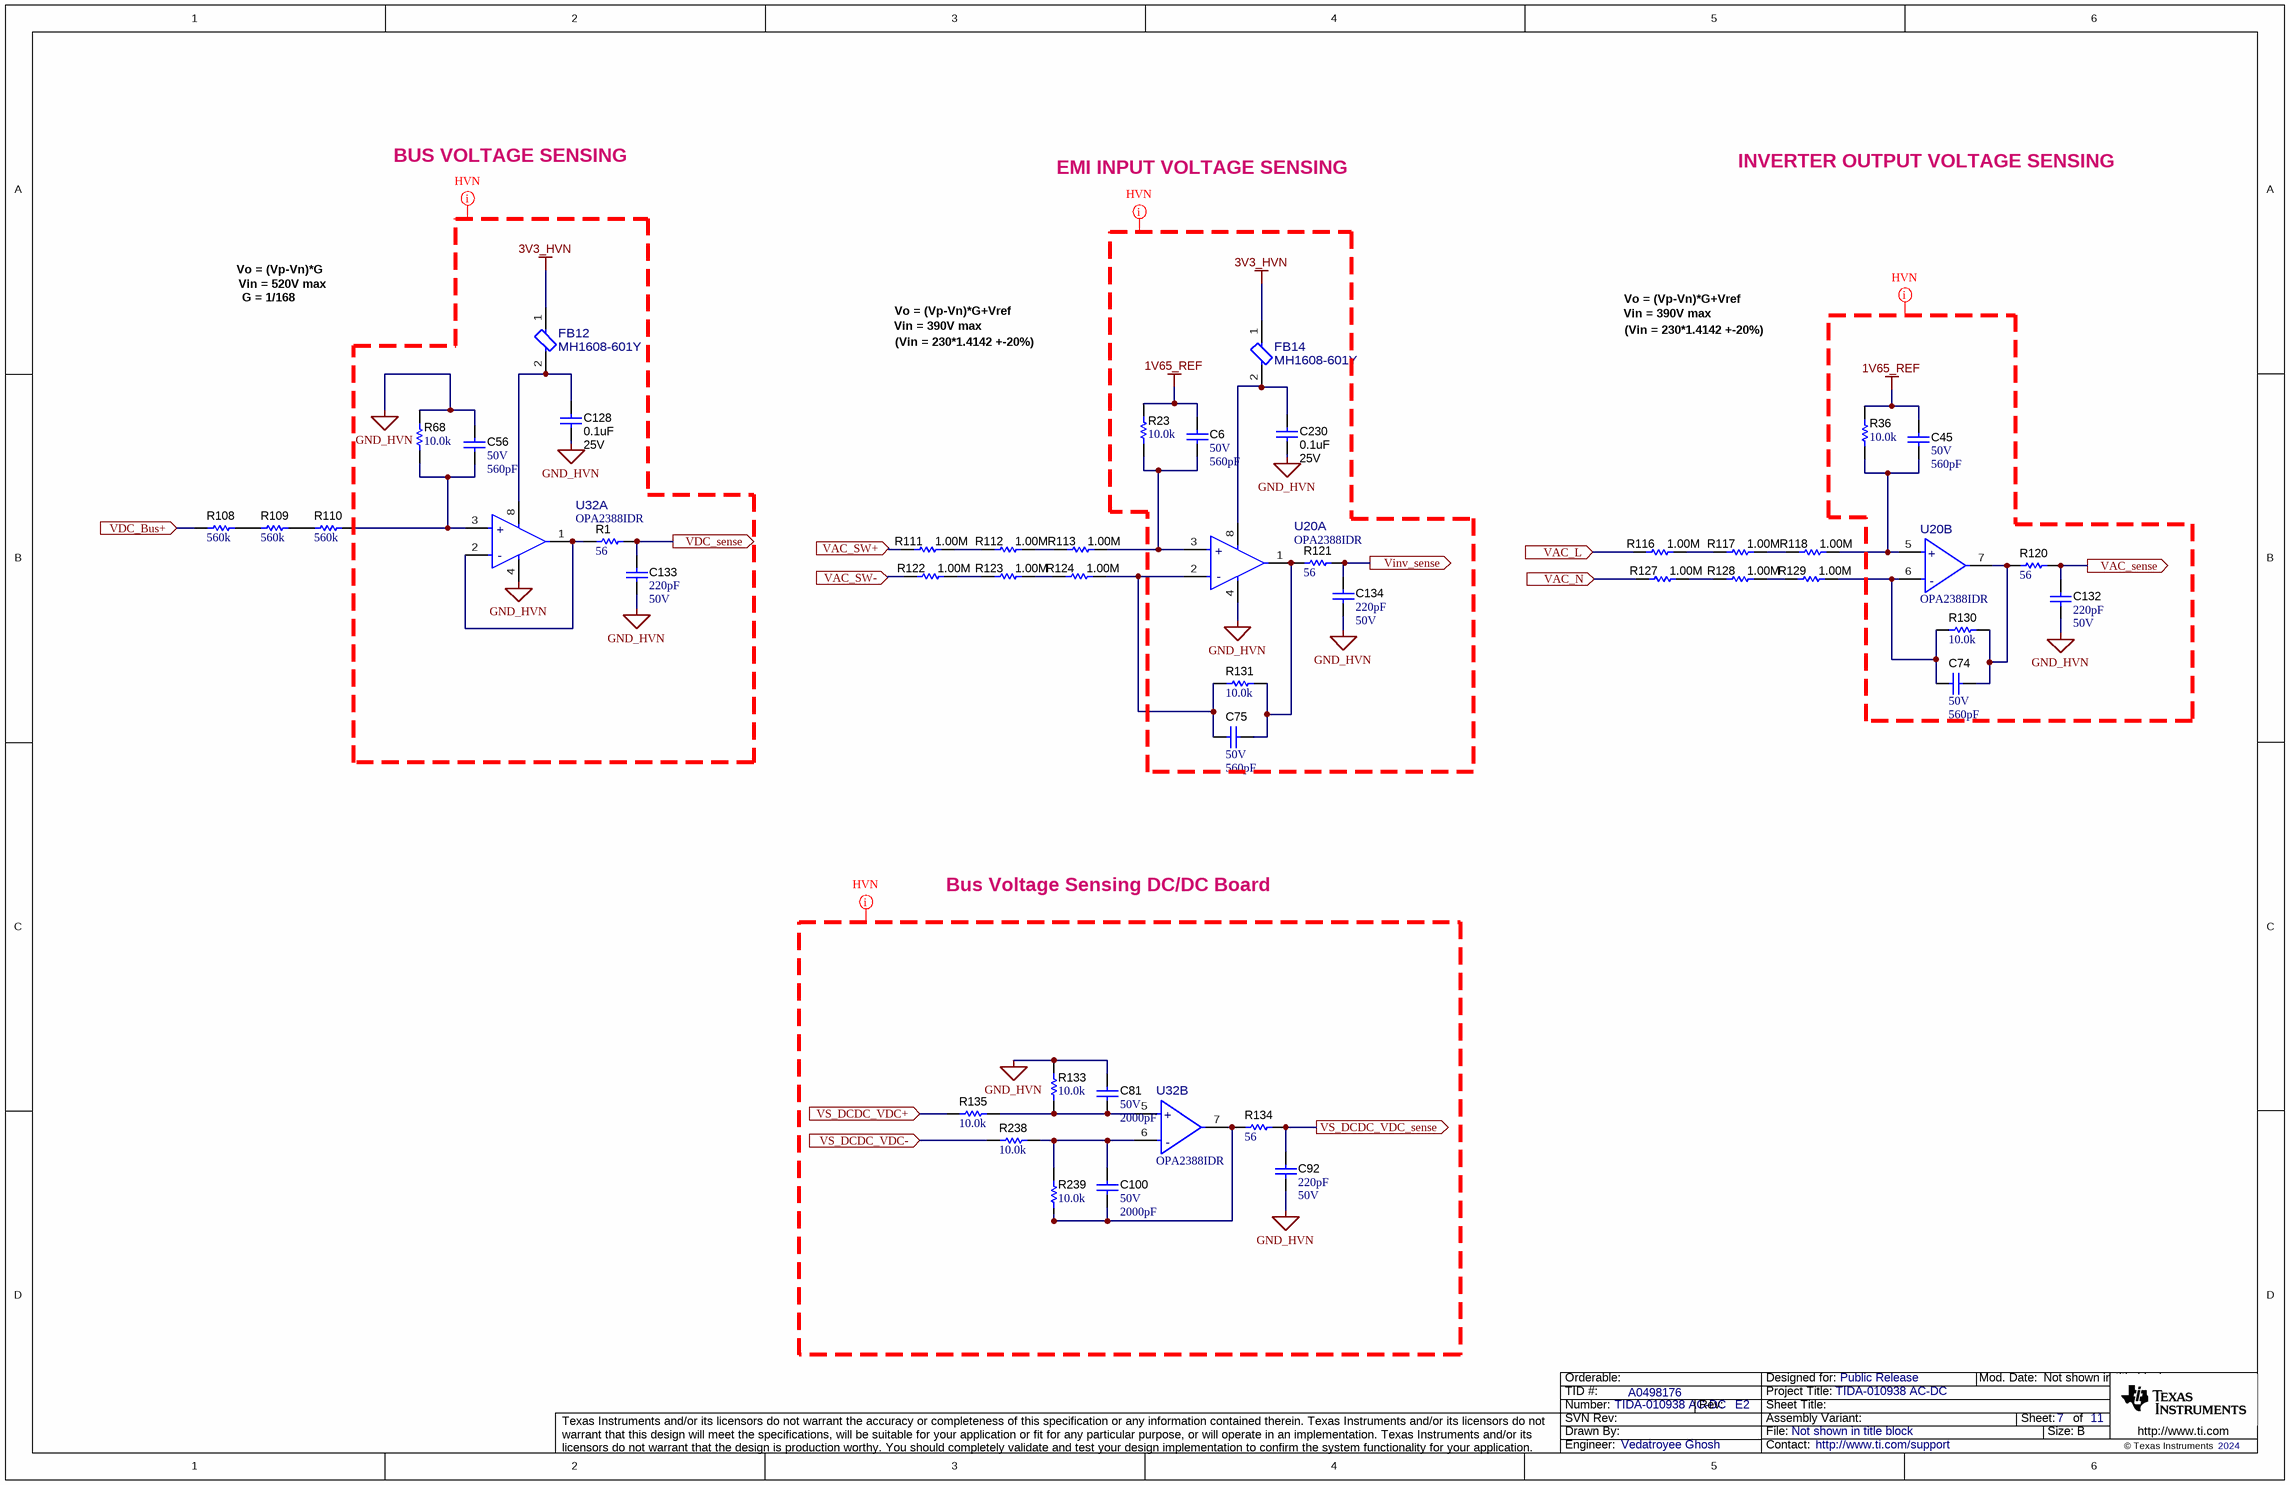
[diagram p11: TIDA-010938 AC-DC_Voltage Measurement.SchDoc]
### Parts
C6  VDC_V: 50V  ValueDisplayed: 560pF  [0603]  (hidden comment: GRM1885C1H561JA01D)
C45  VDC_V: 50V  ValueDisplayed: 560pF  [0603]  (hidden comment: GRM1885C1H561JA01D)
C56  VDC_V: 50V  ValueDisplayed: 560pF  [0603]  (hidden comment: GRM1885C1H561JA01D)
C74  VDC_V: 50V  ValueDisplayed: 560pF  [0603]  (hidden comment: GRM1885C1H561JA01D)
C75  VDC_V: 50V  ValueDisplayed: 560pF  [0603]  (hidden comment: GRM1885C1H561JA01D)
C81  VDC_V: 50V  ValueDisplayed: 2000pF  [0603]  (hidden comment: GRM1885C1H202JA01D)
C92  Cap_F: 220pF  VDC_V: 50V  [0603]  (hidden comment: GRM188R71H221KA01D)
C100  VDC_V: 50V  ValueDisplayed: 2000pF  [0603]  (hidden comment: GRM1885C1H202JA01D)
C128  ValueDisplayed: 0.1uF  VDC_V: 25V  [0603]  (hidden comment: C0603X104K3RACTU)
C132  Cap_F: 220pF  VDC_V: 50V  [0603]  (hidden comment: GRM188R71H221KA01D)
C133  Cap_F: 220pF  VDC_V: 50V  [0603]  (hidden comment: GRM188R71H221KA01D)
C134  Cap_F: 220pF  VDC_V: 50V  [0603]  (hidden comment: GRM188R71H221KA01D)
C230  ValueDisplayed: 0.1uF  VDC_V: 25V  [0603]  (hidden comment: C0603X104K3RACTU)
FB12  MH1608-601Y  [FP-MH1608-601Y_0603-MFG]
FB14  MH1608-601Y  [FP-MH1608-601Y_0603-MFG]
R1  ValueDisplayed: 56  [0603]  (hidden comment: RG1608P-560-B-T5)
R23  ValueDisplayed: 10.0k  [0603]  (hidden comment: RG1608P-103-B-T5)
R36  ValueDisplayed: 10.0k  [0603]  (hidden comment: RG1608P-103-B-T5)
R68  ValueDisplayed: 10.0k  [0603]  (hidden comment: RG1608P-103-B-T5)
R108  ValueDisplayed: 560k  [TNPV1206]  (hidden comment: TNPV1206560KBEEN)
R109  ValueDisplayed: 560k  [TNPV1206]  (hidden comment: TNPV1206560KBEEN)
R110  ValueDisplayed: 560k  [TNPV1206]  (hidden comment: TNPV1206560KBEEN)
R111  ValueDisplayed: 1.00M  [TNPV1206]  (hidden comment: TNPV12061M00BEEN)
R112  ValueDisplayed: 1.00M  [TNPV1206]  (hidden comment: TNPV12061M00BEEN)
R113  ValueDisplayed: 1.00M  [TNPV1206]  (hidden comment: TNPV12061M00BEEN)
R116  ValueDisplayed: 1.00M  [TNPV1206]  (hidden comment: TNPV12061M00BEEN)
R117  ValueDisplayed: 1.00M  [TNPV1206]  (hidden comment: TNPV12061M00BEEN)
R118  ValueDisplayed: 1.00M  [TNPV1206]  (hidden comment: TNPV12061M00BEEN)
R120  ValueDisplayed: 56  [0603]  (hidden comment: RG1608P-560-B-T5)
R121  ValueDisplayed: 56  [0603]  (hidden comment: RG1608P-560-B-T5)
R122  ValueDisplayed: 1.00M  [TNPV1206]  (hidden comment: TNPV12061M00BEEN)
R123  ValueDisplayed: 1.00M  [TNPV1206]  (hidden comment: TNPV12061M00BEEN)
R124  ValueDisplayed: 1.00M  [TNPV1206]  (hidden comment: TNPV12061M00BEEN)
R127  ValueDisplayed: 1.00M  [TNPV1206]  (hidden comment: TNPV12061M00BEEN)
R128  ValueDisplayed: 1.00M  [TNPV1206]  (hidden comment: TNPV12061M00BEEN)
R129  ValueDisplayed: 1.00M  [TNPV1206]  (hidden comment: TNPV12061M00BEEN)
R130  ValueDisplayed: 10.0k  [0603]  (hidden comment: RG1608P-103-B-T5)
R131  ValueDisplayed: 10.0k  [0603]  (hidden comment: RG1608P-103-B-T5)
R133  ValueDisplayed: 10.0k  [0603]  (hidden comment: RG1608P-103-B-T5)
R134  ValueDisplayed: 56  [0603]  (hidden comment: RG1608P-560-B-T5)
R135  ValueDisplayed: 10.0k  [0603]  (hidden comment: RG1608P-103-B-T5)
R238  ValueDisplayed: 10.0k  [0603]  (hidden comment: RG1608P-103-B-T5)
R239  ValueDisplayed: 10.0k  [0603]  (hidden comment: RG1608P-103-B-T5)
U20  OPA2388IDR  [D0008A-MFG]  (parts A,B of 2)
U32  OPA2388IDR  [D0008A-MFG]  (parts A,B of 2)

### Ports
VAC_L (in), VAC_N (in), VAC_sense (out), VAC_SW+ (in), VAC_SW- (in), VDC_Bus+ (in), VDC_sense (out), Vinv_sense (out), VS_DCDC_VDC+ (in), VS_DCDC_VDC- (in), VS_DCDC_VDC_sense (out)

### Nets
1V65_REF: C6.2 C45.2 R23.2 R36.2
3V3_HVN: FB12.1 FB14.1
GND_HVN: C56.1 C81.2 C92.1 C128.1 C132.1 C133.1 C134.1 C230.1 R68.2 R133.1 U20.4(V-) U32.4(V-)  [project net DC Bus-]
ACLOAD_N: R122.1 ; port VAC_SW-
VAC_L: R116.1 ; port VAC_L
VAC_N: R127.1 ; port VAC_N
VAC_sense: C132.2 R120.2 ; port VAC_sense
VAC_SW+: R111.1 ; port VAC_SW+
VDC_Bus+: R108.1 ; port VDC_Bus+
VDC_sense: C133.2 R1.2 ; port VDC_sense
Vinv_sense: C134.2 R121.2 ; port Vinv_sense
VS_DCDC_VDC+: R135.2 ; port VS_DCDC_VDC+
VS_DCDC_VDC-: R238.2 ; port VS_DCDC_VDC-
VS_DCDC_VDC_sense: C92.2 R134.2 ; port VS_DCDC_VDC_sense
NetC6_1: C6.1 R23.1 R113.2 U20.3(+IN_A)
NetC45_1: C45.1 R36.1 R118.2 U20.5(+IN_B)
NetC56_2: C56.2 R68.1 R110.2 U32.3(+IN_A)
NetC74_1: C74.1 R129.2 R130.2 U20.6(-IN_B)
NetC74_2: C74.2 R120.1 R130.1 U20.7(OUT_B)
NetC75_1: C75.1 R124.2 R131.2 U20.2(-IN_A)
NetC75_2: C75.2 R121.1 R131.1 U20.1(OUT_A)
NetC81_1: C81.1 R133.2 R135.1 U32.5(+IN_B)
NetC100_1: C100.1 R238.1 R239.1 U32.6(-IN_B)
NetC100_2: C100.2 R134.1 R239.2 U32.7(OUT_B)
NetC128_2: C128.2 FB12.2 U32.8(V+)
NetC230_2: C230.2 FB14.2 U20.8(V+)
NetR1_1: R1.1 U32.1(OUT_A) U32.2(-IN_A)
NetR108_2: R108.2 R109.1
NetR109_2: R109.2 R110.1
NetR111_2: R111.2 R112.1
NetR112_2: R112.2 R113.1
NetR116_2: R116.2 R117.1
NetR117_2: R117.2 R118.1
NetR122_2: R122.2 R123.1
NetR123_2: R123.2 R124.1
NetR127_2: R127.2 R128.1
NetR128_2: R128.2 R129.1

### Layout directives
net class HVN: 1V65_REF, 3V3_HVN, GND_HVN

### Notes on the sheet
- BUS VOLTAGE SENSING
- EMI INPUT VOLTAGE SENSING
- INVERTER OUTPUT VOLTAGE SENSING
- G = 1/168
- Vo = (Vp-Vn)*G
- Vin = 520V max
- Vo = (Vp-Vn)*G+Vref
- Vin = 390V max
- (Vin = 230*1.4142 +-20%)
- Bus Voltage Sensing DC/DC Board

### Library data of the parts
C6 C45 C56 C74 C75 = CMP-0007225-4: CAP, CERM, 560 pF, 50 V, +/- 5%, C0G/NP0, 0603; Manufacturer: MuRata; TaMin_C: -55°C; Polarized: N; SizeAreaWB_mm2: 4.68; Value1: Unknown; U/M: EA; Value: 560pF; TaMax_C: 125°C; SizeZ_mm: 1; SizeX_mm: 1.6; SizeY_mm: 0.8; SizeArea_mm2: 1.28; AEC Category: Q200
C81 C100 = CMP-0007195-4: CAP, CERM, 2000 pF, 50 V, +/- 5%, C0G/NP0, 0603; Manufacturer: MuRata; TaMin_C: -55°C; Polarized: N; SizeAreaWB_mm2: 4.68; Value1: Unknown; U/M: EA; Value: 2000pF; TaMax_C: 125°C; SizeZ_mm: 1; SizeX_mm: 1.6; SizeY_mm: 0.8; SizeArea_mm2: 1.28; Cap_F: 2nF; AEC Category: Q200
C92 C132-C134 = CMP-0007442-5: as C48 on sheet TIDA-010938 AC-DC_Power Stage_BranchB
C128 C230 = CMP-0006979-5: CAP, CERM, 0.1 uF, 25 V, +/- 10%, X7R, 0603; Manufacturer: Kemet; Polarized: N; Value: 0.1uF; U/M: EA; Cap_F: 100nF; Value1: Unknown; TaMin_C: -55°C; TaMax_C: 125°C; AEC Category: Q200; SizeArea_mm2: 1.28; SizeAreaWB_mm2: 4.68; SizeX_mm: 1.6; SizeY_mm: 0.8; SizeZ_mm: 1
FB12 FB14 = CMP-0037505-1: as FB4 on sheet TIDA-010938 AC-DC_Power Stage_BranchB
R1 R120 R121 R134 = CMP-0023572-3: as R18 on sheet TIDA-010938 AC-DC_Power Stage_BranchB
R23 R36 R68 R130 R131 R133 R135 R238 R239 = CMP-0023404-3: as R33 on sheet TIDA-010938 AC-DC_Power Stage_BranchB
R108-R110 = CMP-0018815-2: RES, 560 k, 0.1%, 1 W, 1206; Manufacturer: Vishay Draloric; Power_W: 1W; TempCo: 25 ppm/C; U/M: EA; Value: 560k; SizeX_mm: 3.2; SizeY_mm: 1.6; SizeZ_mm: 0.65; SizeArea_mm2: 5.12; AEC Qualified: N; VDC_V: 700V; AEC Category: Q200
R111-R113 R116-R118 R122-R124 R127-R129 = CMP-0018805-2: RES, 1.00 M, 0.1%, 1 W, 1206; Manufacturer: Vishay Draloric; Power_W: 1W; TempCo: 25 ppm/C; Value_Code: 1M00; U/M: EA; Value: 1.00Meg; EIA_Code: E192; Res_ohm: 1M; SizeX_mm: 3.2; SizeY_mm: 1.6; SizeZ_mm: 0.65; SizeArea_mm2: 5.12; AEC Qualified: N; VDC_V: 700V; AEC Category: Q200
U20 U32 = CMP-0097119-1: Precision, Zero-Drift, Zero-Crossover, True Rail-to-Rail, Input/Output Operational Amplifiers; Manufacturer: Texas Instruments; TJmax_C: +150°C; TaMin_C: -55°C; AEC Qualified: No; Max Dual Supply Voltage: 2.75V; Min Dual Supply Voltage: 1.25V; Input Offset Voltage: 0.00025mV; Output Current Per Channel: 30-60mA; Standoff Height: 0.11mm; Number Of Channels: 2; Min Supply Voltage: 2.5V; Input Bias Current: 0.00003uA; Nominal Supply Current: 1.7-1.9mA; Voltage Gain: 126-148dB; Bandwidth: 10MHz; SizeZ_mm: 1.75mm; Max Supply Voltage: 5.5V; Response Time: 0.75-2us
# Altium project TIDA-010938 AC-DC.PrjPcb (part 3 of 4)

## Sheet TIDA-010938 AC-DC_Control Stage.SchDoc
size 558 x 431 mm; Date: Not shown in title block; ApprovedBy: Not shown in title block; CheckedBy: Not shown in title block; Author: Not shown in title block; CompanyName: Not shown in title block; Engineer: Not shown in title block; Organization: Not shown in title block; Address1: Not shown in title block; Address2: Not shown in title block; Address3: Not shown in title block; Address4: Not shown in title block; DocumentNumber: 7; Revision: Use project parameter SCH_Rev; SheetNumber: 8; SheetTotal: 11; PageSetup: Record=PageOptions¦CenterHorizontal=True¦CenterVertical=True¦PrintScale=1.00¦XCorrection=1.00¦YCorrection=1.00¦PrintKind=0¦BorderSize=5000000¦LeftOffset=0¦BottomOffset=0¦Orientation=2¦PaperLength=1000¦PaperWidth=1000¦Scale=100¦PaperSource=15¦PrintQuality=600¦MediaType=1¦DitherType=10¦PaperKind=Letter¦PrintScaleMode=1

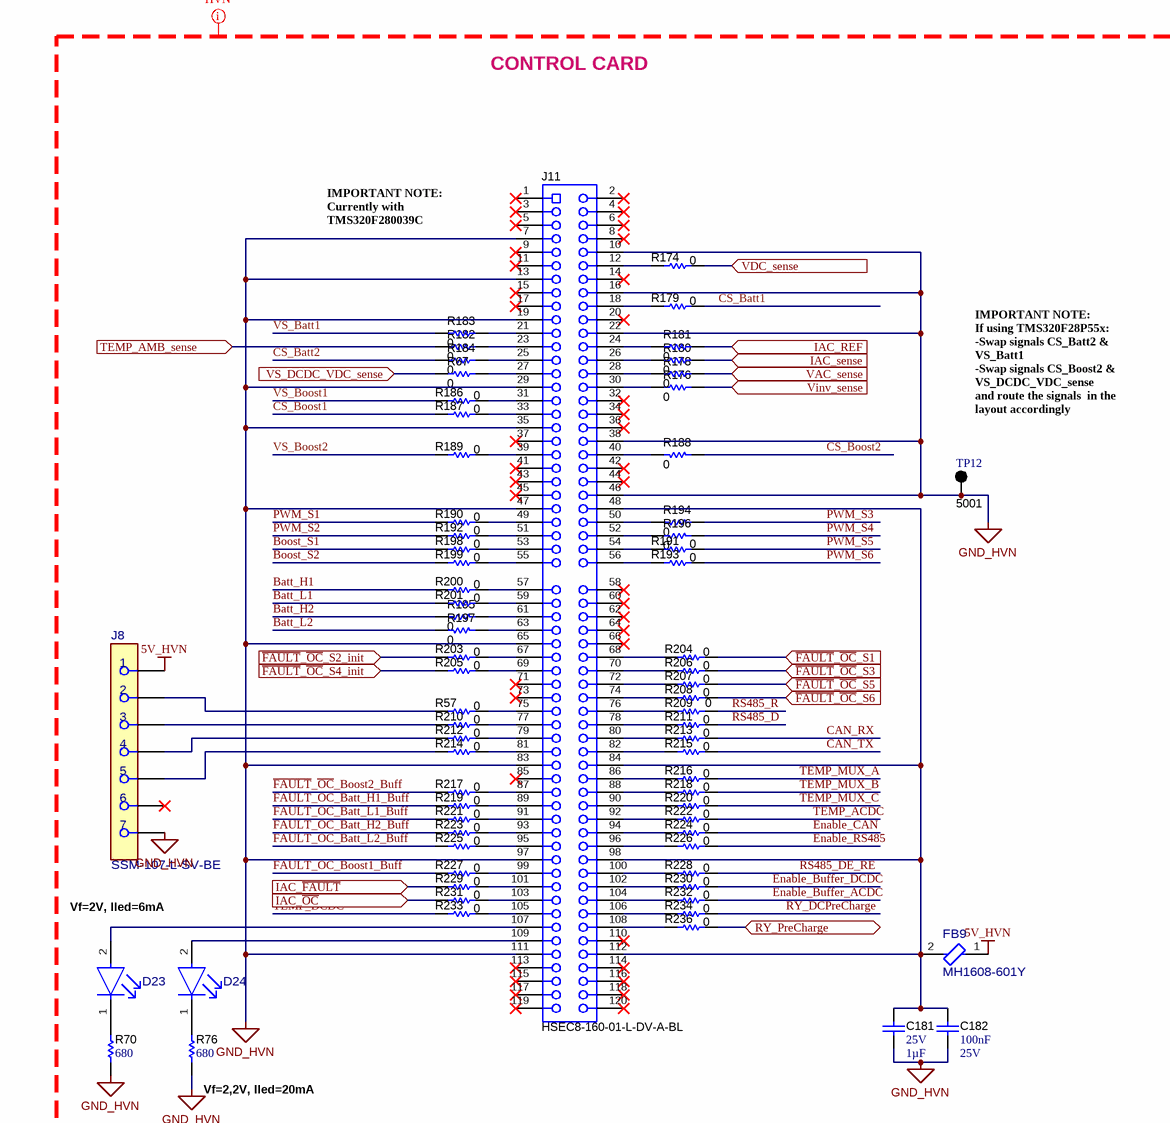
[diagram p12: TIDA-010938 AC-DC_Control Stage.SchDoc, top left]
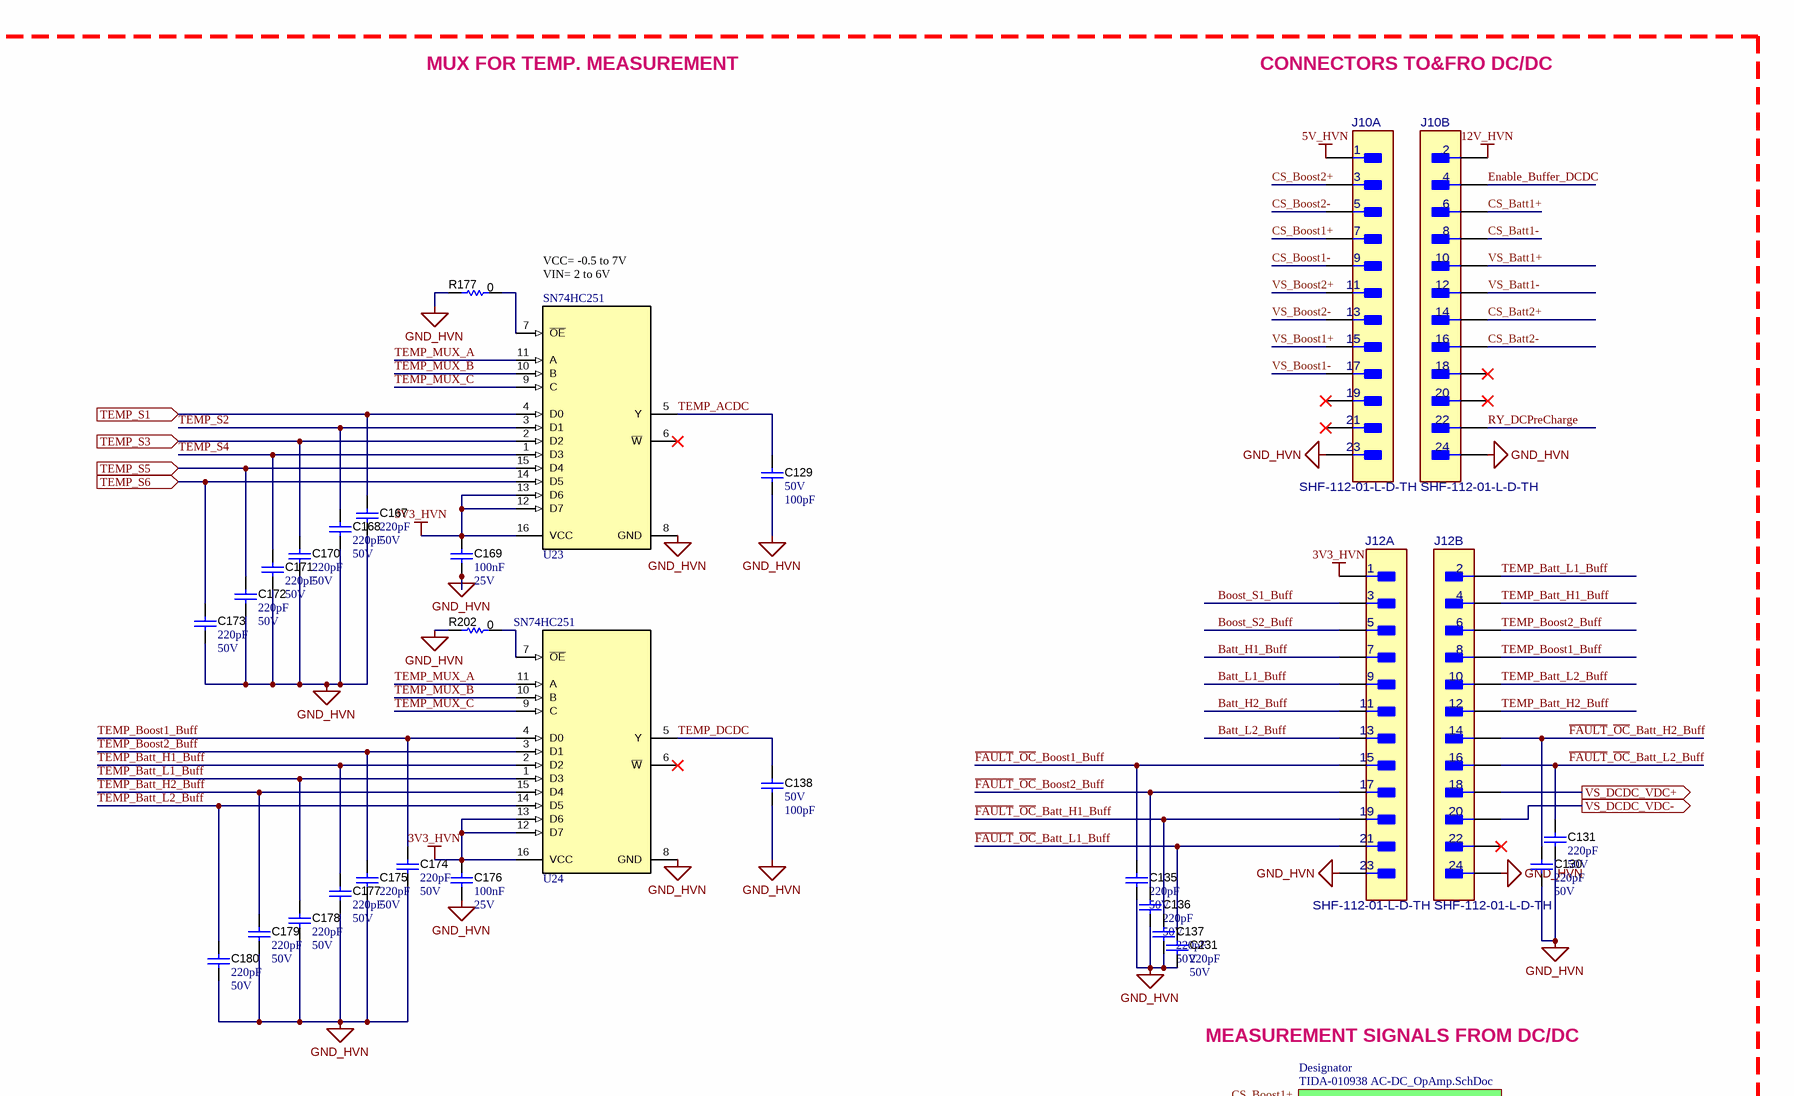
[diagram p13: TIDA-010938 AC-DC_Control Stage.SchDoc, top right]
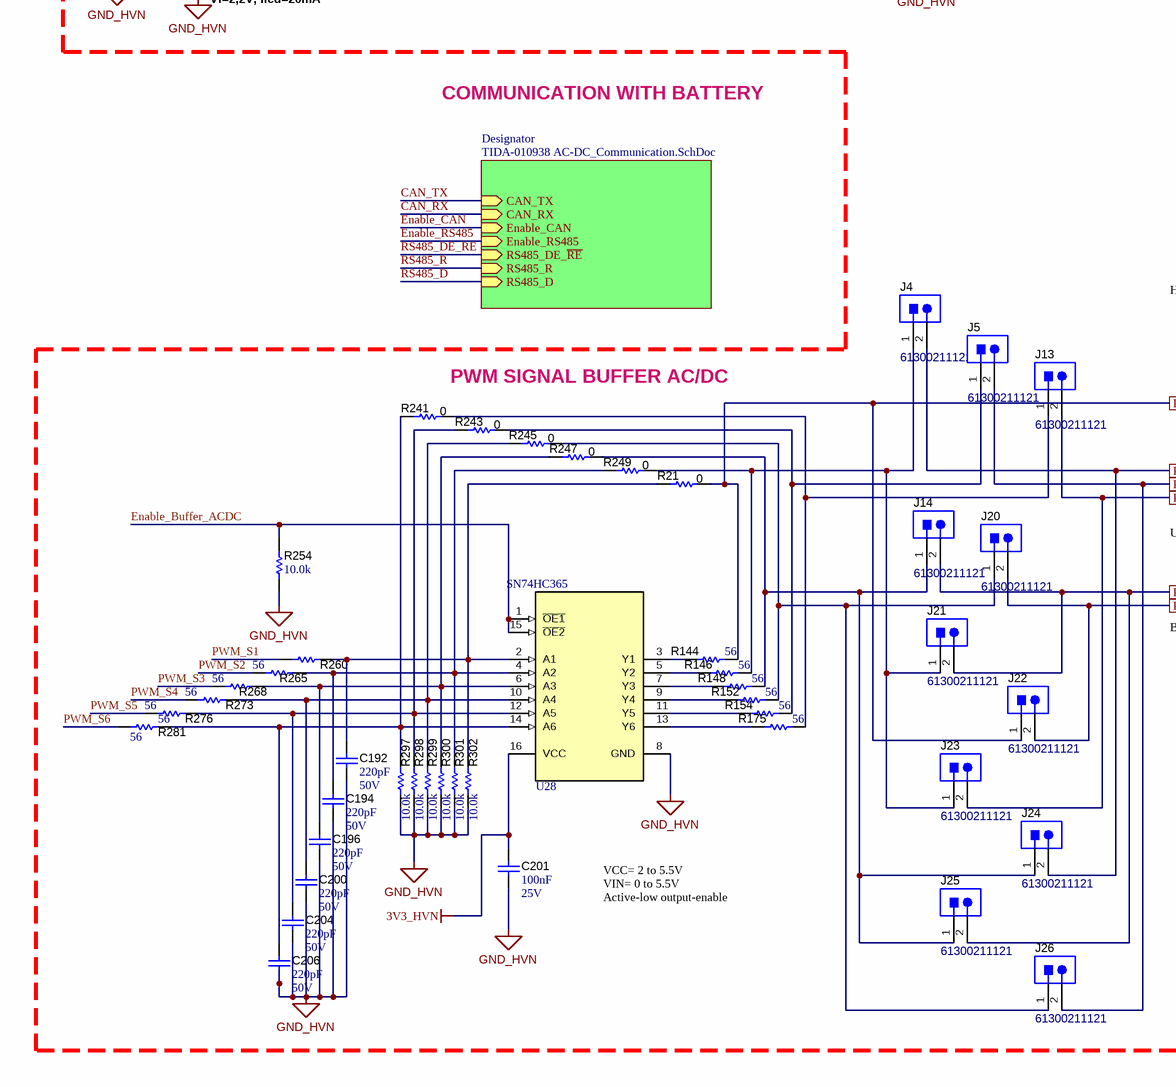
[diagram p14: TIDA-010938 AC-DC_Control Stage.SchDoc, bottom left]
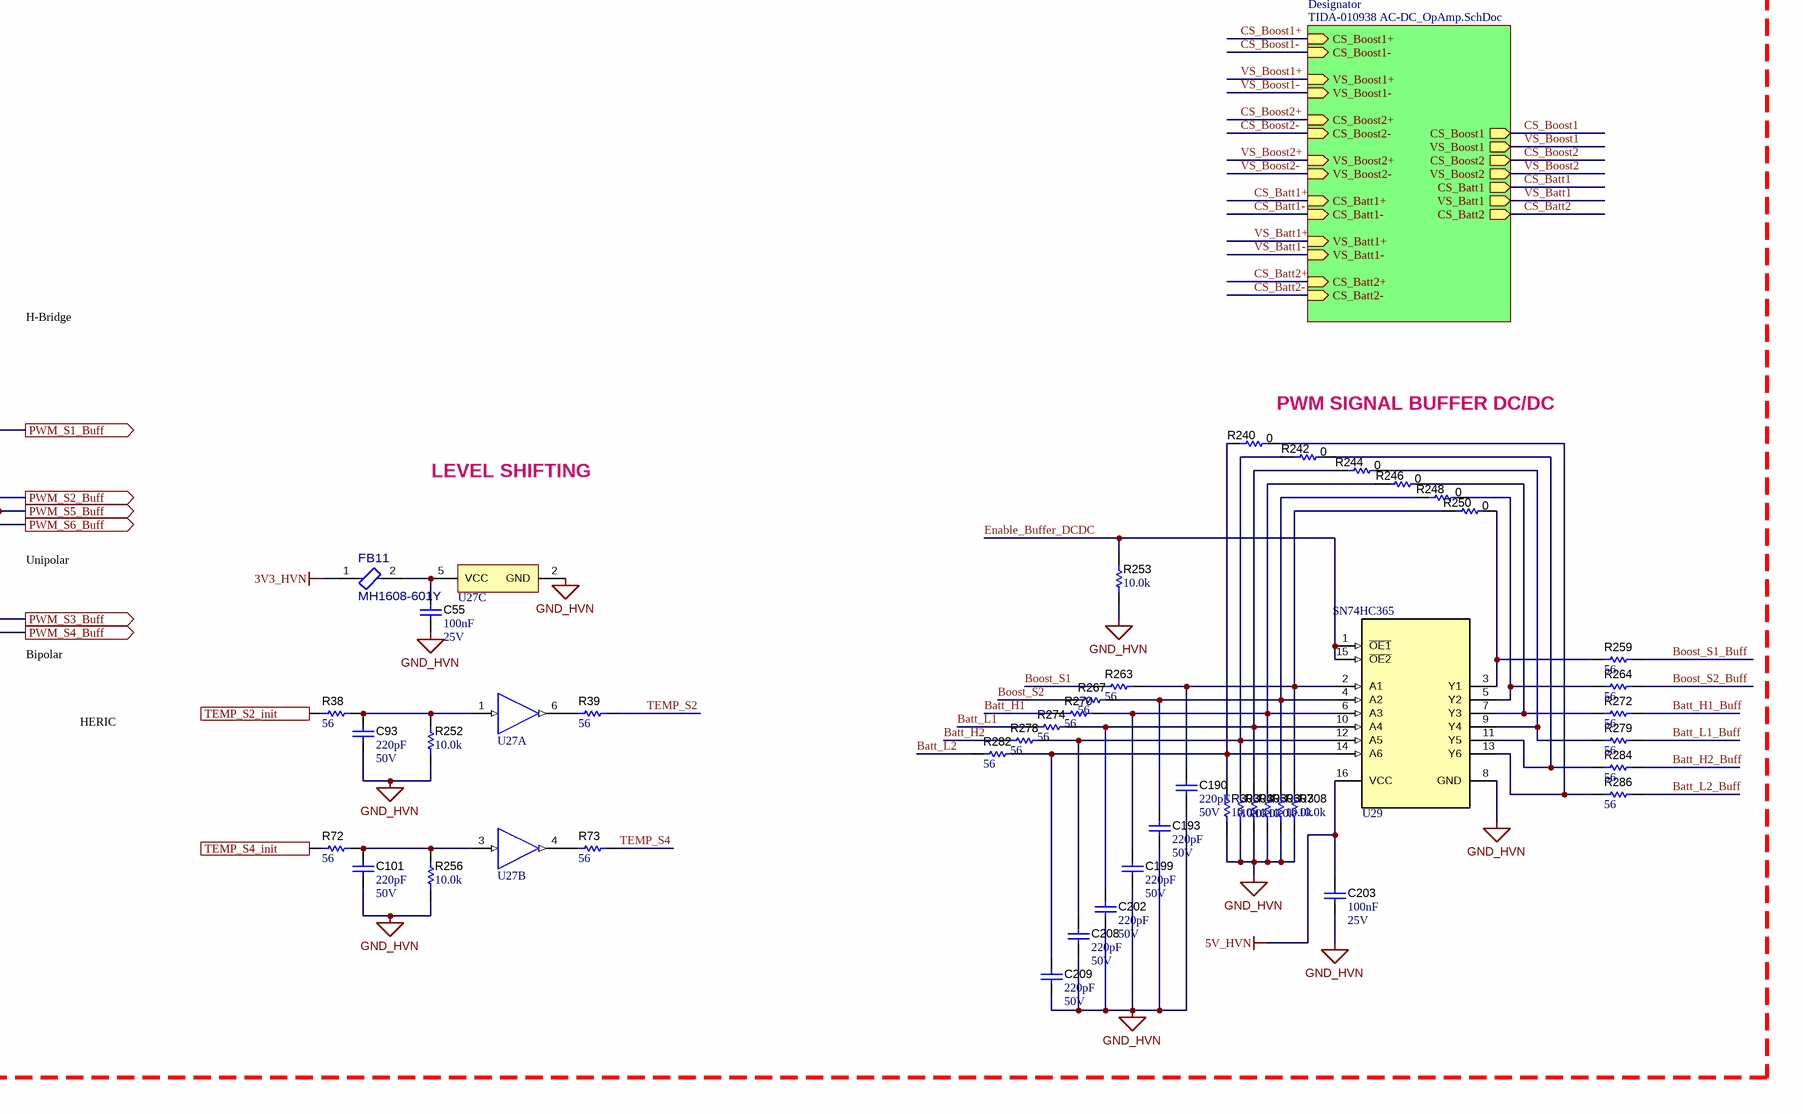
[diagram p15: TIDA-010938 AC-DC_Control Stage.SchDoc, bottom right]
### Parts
C55  Cap_F: 100nF  VDC_V: 25V  [0603]  (hidden comment: 06033C104JAT2A)
C93  Cap_F: 220pF  VDC_V: 50V  [0603]  (hidden comment: GRM188R71H221KA01D)
C101  Cap_F: 220pF  VDC_V: 50V  [0603]  (hidden comment: GRM188R71H221KA01D)
C129  VDC_V: 50V  ValueDisplayed: 100pF  [0603]  (hidden comment: C0603C101J5GAC)
C130  Cap_F: 220pF  VDC_V: 50V  [0603]  (hidden comment: GRM188R71H221KA01D)
C131  Cap_F: 220pF  VDC_V: 50V  [0603]  (hidden comment: GRM188R71H221KA01D)
C135  Cap_F: 220pF  VDC_V: 50V  [0603]  (hidden comment: GRM188R71H221KA01D)
C136  Cap_F: 220pF  VDC_V: 50V  [0603]  (hidden comment: GRM188R71H221KA01D)
C137  Cap_F: 220pF  VDC_V: 50V  [0603]  (hidden comment: GRM188R71H221KA01D)
C138  VDC_V: 50V  ValueDisplayed: 100pF  [0603]  (hidden comment: C0603C101J5GAC)
C167  Cap_F: 220pF  VDC_V: 50V  [0603]  (hidden comment: GRM188R71H221KA01D)
C168  Cap_F: 220pF  VDC_V: 50V  [0603]  (hidden comment: GRM188R71H221KA01D)
C169  Cap_F: 100nF  VDC_V: 25V  [0603]  (hidden comment: 06033C104JAT2A)
C170  Cap_F: 220pF  VDC_V: 50V  [0603]  (hidden comment: GRM188R71H221KA01D)
C171  Cap_F: 220pF  VDC_V: 50V  [0603]  (hidden comment: GRM188R71H221KA01D)
C172  Cap_F: 220pF  VDC_V: 50V  [0603]  (hidden comment: GRM188R71H221KA01D)
C173  Cap_F: 220pF  VDC_V: 50V  [0603]  (hidden comment: GRM188R71H221KA01D)
C174  Cap_F: 220pF  VDC_V: 50V  [0603]  (hidden comment: GRM188R71H221KA01D)
C175  Cap_F: 220pF  VDC_V: 50V  [0603]  (hidden comment: GRM188R71H221KA01D)
C176  Cap_F: 100nF  VDC_V: 25V  [0603]  (hidden comment: 06033C104JAT2A)
C177  Cap_F: 220pF  VDC_V: 50V  [0603]  (hidden comment: GRM188R71H221KA01D)
C178  Cap_F: 220pF  VDC_V: 50V  [0603]  (hidden comment: GRM188R71H221KA01D)
C179  Cap_F: 220pF  VDC_V: 50V  [0603]  (hidden comment: GRM188R71H221KA01D)
C180  Cap_F: 220pF  VDC_V: 50V  [0603]  (hidden comment: GRM188R71H221KA01D)
C181  VDC_V: 25V  ValueDisplayed: 1µF  [0603]  (hidden comment: TMK107BJ105KA-T)
C182  Cap_F: 100nF  VDC_V: 25V  [0603]  (hidden comment: 06033C104JAT2A)
C190  Cap_F: 220pF  VDC_V: 50V  [0603]  (hidden comment: GRM188R71H221KA01D)
C192  Cap_F: 220pF  VDC_V: 50V  [0603]  (hidden comment: GRM188R71H221KA01D)
C193  Cap_F: 220pF  VDC_V: 50V  [0603]  (hidden comment: GRM188R71H221KA01D)
C194  Cap_F: 220pF  VDC_V: 50V  [0603]  (hidden comment: GRM188R71H221KA01D)
C196  Cap_F: 220pF  VDC_V: 50V  [0603]  (hidden comment: GRM188R71H221KA01D)
C199  Cap_F: 220pF  VDC_V: 50V  [0603]  (hidden comment: GRM188R71H221KA01D)
C200  Cap_F: 220pF  VDC_V: 50V  [0603]  (hidden comment: GRM188R71H221KA01D)
C201  Cap_F: 100nF  VDC_V: 25V  [0603]  (hidden comment: 06033C104JAT2A)
C202  Cap_F: 220pF  VDC_V: 50V  [0603]  (hidden comment: GRM188R71H221KA01D)
C203  Cap_F: 100nF  VDC_V: 25V  [0603]  (hidden comment: 06033C104JAT2A)
C204  Cap_F: 220pF  VDC_V: 50V  [0603]  (hidden comment: GRM188R71H221KA01D)
C206  Cap_F: 220pF  VDC_V: 50V  [0603]  (hidden comment: GRM188R71H221KA01D)
C208  Cap_F: 220pF  VDC_V: 50V  [0603]  (hidden comment: GRM188R71H221KA01D)
C209  Cap_F: 220pF  VDC_V: 50V  [0603]  (hidden comment: GRM188R71H221KA01D)
C231  Cap_F: 220pF  VDC_V: 50V  [0603]  (hidden comment: GRM188R71H221KA01D)
D23  KG DELLS1.22-JGKH-24  [FP-KG DELLS1.22-JGKH-24_0603-MFG]  (value not drawn)
D24  KG DELLS1.22-JGKH-24  [FP-KG DELLS1.22-JGKH-24_0603-MFG]  (value not drawn)
FB9  MH1608-601Y  [FP-MH1608-601Y_0603-MFG]
FB11  MH1608-601Y  [FP-MH1608-601Y_0603-MFG]
J4  61300211121  [WURTH_61300211121]
J5  61300211121  [WURTH_61300211121]
J8  SSM-107-L-SV-BE  [FP-SSM-107-L-SV-BE_HDR7-MFG]
J10  SHF-112-01-L-D-TH  [FP-SHF-112-01-L-D-TH_HDR24-MFG]  (parts A,B of 2)
J11  HSEC8-160-01-L-DV-A-BL  [controlCARD-120HSEC]
J12  SHF-112-01-L-D-TH  [FP-SHF-112-01-L-D-TH_HDR24-MFG]  (parts A,B of 2)
J13  61300211121  [WURTH_61300211121]
J14  61300211121  [WURTH_61300211121]
J20  61300211121  [WURTH_61300211121]
J21  61300211121  [WURTH_61300211121]
J22  61300211121  [WURTH_61300211121]
J23  61300211121  [WURTH_61300211121]
J24  61300211121  [WURTH_61300211121]
J25  61300211121  [WURTH_61300211121]
J26  61300211121  [WURTH_61300211121]
R21  ValueDisplayed: 0  [0603]  (hidden comment: RCS06030000Z0EA)
R38  ValueDisplayed: 56  [0603]  (hidden comment: RG1608P-560-B-T5)
R39  ValueDisplayed: 56  [0603]  (hidden comment: RG1608P-560-B-T5)
R57  ValueDisplayed: 0  [0603]  (hidden comment: RCS06030000Z0EA)
R67  ValueDisplayed: 0  [0603]  (hidden comment: RCS06030000Z0EA)
R70  ValueDisplayed: 680  [0603]  (hidden comment: RC0603JR-07680RL)
R72  ValueDisplayed: 56  [0603]  (hidden comment: RG1608P-560-B-T5)
R73  ValueDisplayed: 56  [0603]  (hidden comment: RG1608P-560-B-T5)
R76  ValueDisplayed: 680  [0603]  (hidden comment: RC0603JR-07680RL)
R144  ValueDisplayed: 56  [0603]  (hidden comment: RG1608P-560-B-T5)
R146  ValueDisplayed: 56  [0603]  (hidden comment: RG1608P-560-B-T5)
R148  ValueDisplayed: 56  [0603]  (hidden comment: RG1608P-560-B-T5)
R152  ValueDisplayed: 56  [0603]  (hidden comment: RG1608P-560-B-T5)
R154  ValueDisplayed: 56  [0603]  (hidden comment: RG1608P-560-B-T5)
R174  ValueDisplayed: 0  [0603]  (hidden comment: RCS06030000Z0EA)
R175  ValueDisplayed: 56  [0603]  (hidden comment: RG1608P-560-B-T5)
R176  ValueDisplayed: 0  [0603]  (hidden comment: RCS06030000Z0EA)
R177  ValueDisplayed: 0  [0603]  (hidden comment: RCS06030000Z0EA)
R178  ValueDisplayed: 0  [0603]  (hidden comment: RCS06030000Z0EA)
R179  ValueDisplayed: 0  [0603]  (hidden comment: RCS06030000Z0EA)
R180  ValueDisplayed: 0  [0603]  (hidden comment: RCS06030000Z0EA)
R181  ValueDisplayed: 0  [0603]  (hidden comment: RCS06030000Z0EA)
R182  ValueDisplayed: 0  [0603]  (hidden comment: RCS06030000Z0EA)
R183  ValueDisplayed: 0  [0603]  (hidden comment: RCS06030000Z0EA)
R184  ValueDisplayed: 0  [0603]  (hidden comment: RCS06030000Z0EA)
R186  ValueDisplayed: 0  [0603]  (hidden comment: RCS06030000Z0EA)
R187  ValueDisplayed: 0  [0603]  (hidden comment: RCS06030000Z0EA)
R188  ValueDisplayed: 0  [0603]  (hidden comment: RCS06030000Z0EA)
R189  ValueDisplayed: 0  [0603]  (hidden comment: RCS06030000Z0EA)
R190  ValueDisplayed: 0  [0603]  (hidden comment: RCS06030000Z0EA)
R191  ValueDisplayed: 0  [0603]  (hidden comment: RCS06030000Z0EA)
R192  ValueDisplayed: 0  [0603]  (hidden comment: RCS06030000Z0EA)
R193  ValueDisplayed: 0  [0603]  (hidden comment: RCS06030000Z0EA)
R194  ValueDisplayed: 0  [0603]  (hidden comment: RCS06030000Z0EA)
R195  ValueDisplayed: 0  [0603]  (hidden comment: RCS06030000Z0EA)
R196  ValueDisplayed: 0  [0603]  (hidden comment: RCS06030000Z0EA)
R197  ValueDisplayed: 0  [0603]  (hidden comment: RCS06030000Z0EA)
R198  ValueDisplayed: 0  [0603]  (hidden comment: RCS06030000Z0EA)
R199  ValueDisplayed: 0  [0603]  (hidden comment: RCS06030000Z0EA)
R200  ValueDisplayed: 0  [0603]  (hidden comment: RCS06030000Z0EA)
R201  ValueDisplayed: 0  [0603]  (hidden comment: RCS06030000Z0EA)
R202  ValueDisplayed: 0  [0603]  (hidden comment: RCS06030000Z0EA)
R203  ValueDisplayed: 0  [0603]  (hidden comment: RCS06030000Z0EA)
R204  ValueDisplayed: 0  [0603]  (hidden comment: RCS06030000Z0EA)
R205  ValueDisplayed: 0  [0603]  (hidden comment: RCS06030000Z0EA)
R206  ValueDisplayed: 0  [0603]  (hidden comment: RCS06030000Z0EA)
R207  ValueDisplayed: 0  [0603]  (hidden comment: RCS06030000Z0EA)
R208  ValueDisplayed: 0  [0603]  (hidden comment: RCS06030000Z0EA)
R209  value 0  [0603]  (hidden comment: RCS06030000Z0EA)
R210  ValueDisplayed: 0  [0603]  (hidden comment: RCS06030000Z0EA)
R211  ValueDisplayed: 0  [0603]  (hidden comment: RCS06030000Z0EA)
R212  ValueDisplayed: 0  [0603]  (hidden comment: RCS06030000Z0EA)
R213  ValueDisplayed: 0  [0603]  (hidden comment: RCS06030000Z0EA)
R214  ValueDisplayed: 0  [0603]  (hidden comment: RCS06030000Z0EA)
R215  ValueDisplayed: 0  [0603]  (hidden comment: RCS06030000Z0EA)
R216  ValueDisplayed: 0  [0603]  (hidden comment: RCS06030000Z0EA)
R217  ValueDisplayed: 0  [0603]  (hidden comment: RCS06030000Z0EA)
R218  ValueDisplayed: 0  [0603]  (hidden comment: RCS06030000Z0EA)
R219  ValueDisplayed: 0  [0603]  (hidden comment: RCS06030000Z0EA)
R220  ValueDisplayed: 0  [0603]  (hidden comment: RCS06030000Z0EA)
R221  ValueDisplayed: 0  [0603]  (hidden comment: RCS06030000Z0EA)
R222  ValueDisplayed: 0  [0603]  (hidden comment: RCS06030000Z0EA)
R223  ValueDisplayed: 0  [0603]  (hidden comment: RCS06030000Z0EA)
R224  ValueDisplayed: 0  [0603]  (hidden comment: RCS06030000Z0EA)
R225  ValueDisplayed: 0  [0603]  (hidden comment: RCS06030000Z0EA)
R226  ValueDisplayed: 0  [0603]  (hidden comment: RCS06030000Z0EA)
R227  ValueDisplayed: 0  [0603]  (hidden comment: RCS06030000Z0EA)
R228  ValueDisplayed: 0  [0603]  (hidden comment: RCS06030000Z0EA)
R229  ValueDisplayed: 0  [0603]  (hidden comment: RCS06030000Z0EA)
R230  ValueDisplayed: 0  [0603]  (hidden comment: RCS06030000Z0EA)
R231  ValueDisplayed: 0  [0603]  (hidden comment: RCS06030000Z0EA)
R232  ValueDisplayed: 0  [0603]  (hidden comment: RCS06030000Z0EA)
R233  ValueDisplayed: 0  [0603]  (hidden comment: RCS06030000Z0EA)
R234  ValueDisplayed: 0  [0603]  (hidden comment: RCS06030000Z0EA)
R236  ValueDisplayed: 0  [0603]  (hidden comment: RCS06030000Z0EA)
R240  ValueDisplayed: 0  [0603]  (hidden comment: RCS06030000Z0EA)
R241  ValueDisplayed: 0  [0603]  (hidden comment: RCS06030000Z0EA)
R242  ValueDisplayed: 0  [0603]  (hidden comment: RCS06030000Z0EA)
R243  ValueDisplayed: 0  [0603]  (hidden comment: RCS06030000Z0EA)
R244  ValueDisplayed: 0  [0603]  (hidden comment: RCS06030000Z0EA)
R245  ValueDisplayed: 0  [0603]  (hidden comment: RCS06030000Z0EA)
R246  ValueDisplayed: 0  [0603]  (hidden comment: RCS06030000Z0EA)
R247  ValueDisplayed: 0  [0603]  (hidden comment: RCS06030000Z0EA)
R248  ValueDisplayed: 0  [0603]  (hidden comment: RCS06030000Z0EA)
R249  ValueDisplayed: 0  [0603]  (hidden comment: RCS06030000Z0EA)
R250  ValueDisplayed: 0  [0603]  (hidden comment: RCS06030000Z0EA)
R252  ValueDisplayed: 10.0k  [0603]  (hidden comment: RG1608P-103-B-T5)
R253  ValueDisplayed: 10.0k  [0603]  (hidden comment: RG1608P-103-B-T5)
R254  ValueDisplayed: 10.0k  [0603]  (hidden comment: RG1608P-103-B-T5)
R256  ValueDisplayed: 10.0k  [0603]  (hidden comment: RG1608P-103-B-T5)
R259  ValueDisplayed: 56  [0603]  (hidden comment: RG1608P-560-B-T5)
R260  ValueDisplayed: 56  [0603]  (hidden comment: RG1608P-560-B-T5)
R263  ValueDisplayed: 56  [0603]  (hidden comment: RG1608P-560-B-T5)
R264  ValueDisplayed: 56  [0603]  (hidden comment: RG1608P-560-B-T5)
R265  ValueDisplayed: 56  [0603]  (hidden comment: RG1608P-560-B-T5)
R267  ValueDisplayed: 56  [0603]  (hidden comment: RG1608P-560-B-T5)
R268  ValueDisplayed: 56  [0603]  (hidden comment: RG1608P-560-B-T5)
R270  ValueDisplayed: 56  [0603]  (hidden comment: RG1608P-560-B-T5)
R272  ValueDisplayed: 56  [0603]  (hidden comment: RG1608P-560-B-T5)
R273  ValueDisplayed: 56  [0603]  (hidden comment: RG1608P-560-B-T5)
R274  ValueDisplayed: 56  [0603]  (hidden comment: RG1608P-560-B-T5)
R276  ValueDisplayed: 56  [0603]  (hidden comment: RG1608P-560-B-T5)
R278  ValueDisplayed: 56  [0603]  (hidden comment: RG1608P-560-B-T5)
R279  ValueDisplayed: 56  [0603]  (hidden comment: RG1608P-560-B-T5)
R281  ValueDisplayed: 56  [0603]  (hidden comment: RG1608P-560-B-T5)
R282  ValueDisplayed: 56  [0603]  (hidden comment: RG1608P-560-B-T5)
R284  ValueDisplayed: 56  [0603]  (hidden comment: RG1608P-560-B-T5)
R286  ValueDisplayed: 56  [0603]  (hidden comment: RG1608P-560-B-T5)
R297  ValueDisplayed: 10.0k  [0603]  (hidden comment: RG1608P-103-B-T5)
R298  ValueDisplayed: 10.0k  [0603]  (hidden comment: RG1608P-103-B-T5)
R299  ValueDisplayed: 10.0k  [0603]  (hidden comment: RG1608P-103-B-T5)
R300  ValueDisplayed: 10.0k  [0603]  (hidden comment: RG1608P-103-B-T5)
R301  ValueDisplayed: 10.0k  [0603]  (hidden comment: RG1608P-103-B-T5)
R302  ValueDisplayed: 10.0k  [0603]  (hidden comment: RG1608P-103-B-T5)
R303  ValueDisplayed: 10.0k  [0603]  (hidden comment: RG1608P-103-B-T5)
R304  ValueDisplayed: 10.0k  [0603]  (hidden comment: RG1608P-103-B-T5)
R305  ValueDisplayed: 10.0k  [0603]  (hidden comment: RG1608P-103-B-T5)
R306  ValueDisplayed: 10.0k  [0603]  (hidden comment: RG1608P-103-B-T5)
R307  ValueDisplayed: 10.0k  [0603]  (hidden comment: RG1608P-103-B-T5)
R308  ValueDisplayed: 10.0k  [0603]  (hidden comment: RG1608P-103-B-T5)
TP12  5001  [Keystone5001]
U23  Generic Part Number: SN74HC251  [PW0016A_N]  (hidden comment: SN74HC251PW)
U24  Generic Part Number: SN74HC251  [PW0016A_N]  (hidden comment: SN74HC251PW)
U27  SN74LVC2G34DBVR  [DBV0006A_N]  (value not drawn)  (parts A,B,C of 3)
U28  Generic Part Number: SN74HC365  [D0016A_L]  (hidden comment: SN74HC365D)
U29  Generic Part Number: SN74HC365  [D0016A_L]  (hidden comment: SN74HC365D)

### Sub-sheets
Designator = TIDA-010938 AC-DC_Communication.SchDoc: CAN_TX (in), CAN_RX (in), Enable_CAN (in), Enable_RS485 (in), RS485_DE_~{RE} (in), RS485_R (in), RS485_D (in)
Designator = TIDA-010938 AC-DC_OpAmp.SchDoc: CS_Boost1+ (in), CS_Boost1- (in), CS_Boost1 (out), CS_Boost2 (out), VS_Boost1 (out), VS_Boost2 (out), CS_Batt1 (out), VS_Batt1 (out), CS_Batt2 (out), CS_Batt1+ (in), CS_Batt1- (in), CS_Boost2+ (in), CS_Boost2- (in), VS_Boost1+ (in), VS_Boost1- (in), VS_Boost2+ (in), VS_Boost2- (in), VS_Batt1+ (in), VS_Batt1- (in), CS_Batt2+ (in), CS_Batt2- (in)

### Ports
IAC_REF (in), IAC_sense (in), IAC_~{FAULT} (in), IAC_~{OC} (in), PWM_S1_Buff (out), PWM_S2_Buff (out), PWM_S3_Buff (out), PWM_S4_Buff (out), PWM_S5_Buff (out), PWM_S6_Buff (out), RY_PreCharge (bidir), TEMP_AMB_sense (in), TEMP_S1 (in), TEMP_S2_init (in), TEMP_S3 (in), TEMP_S4_init (in), TEMP_S5 (in), TEMP_S6 (in), VAC_sense (in), VDC_sense (in), Vinv_sense (in), VS_DCDC_VDC+ (out), VS_DCDC_VDC- (out), VS_DCDC_VDC_sense (in), ~{FAULT}_~{OC}_S1 (in), ~{FAULT}_~{OC}_S2_init (in), ~{FAULT}_~{OC}_S3 (in), ~{FAULT}_~{OC}_S4_init (in), ~{FAULT}_~{OC}_S5 (in), ~{FAULT}_~{OC}_S6 (in)

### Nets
3V3_HVN: C169.1 C176.1 C201.2 FB11.1 J12.1 U23.12(D7) U23.13(D6) U23.16(VCC) U24.12(D7) U24.13(D6) U24.16(VCC) U28.16(VCC)
5V_HVN: C203.1 FB9.1 J8.1 J10.1 U29.16(VCC)
12V_HVN: J10.2
GND_HVN: C55.1 C93.1 C101.1 C129.2 C130.1 C131.1 C135.1 C136.1 C137.1 C138.2 C167.1 C168.1 C169.2 C170.1 C171.1 C172.1 C173.1 C174.1 C175.1 C176.2 C177.1 C178.1 C179.1 C180.1 C181.1 C182.2 C190.1 C192.1 C193.1 C194.1 C196.1 C199.1 C200.1 C201.1 C202.1 C203.2 C204.1 C206.1 C208.1 C209.1 C231.1 J8.7 J10.23 J10.24 J11.7 J11.10 J11.13 J11.16 J11.19 J11.22 J11.29 J11.35 J11.38 J11.46 J11.47 J11.65 J11.83 J11.97 J11.111 J12.23 J12.24 R70.1 R76.1 R177.1 R202.1 R252.1 R253.1 R254.1 R256.1 R297.1 R298.1 R299.1 R300.1 R301.1 R302.1 R303.1 R304.1 R305.1 R306.1 R307.1 R308.1 TP12.1 U23.8(GND) U24.8(GND) U27.2(GND) U28.8(GND) U29.8(GND)  [project net DC Bus-]
Batt_H1: R200.1 R270.1
Batt_H1_Buff: J12.7 R272.2
Batt_H2: R195.2 R278.1
Batt_H2_Buff: J12.11 R284.2
Batt_L1: R201.1 R274.1
Batt_L1_Buff: J12.9 R279.2
Batt_L2: R197.2 R282.1
Batt_L2_Buff: J12.13 R286.2
Boost_S1: R198.1 R263.1
Boost_S1_Buff: J12.3 R259.2
Boost_S2: R199.1 R267.1
Boost_S2_Buff: J12.5 R264.2
CAN_RX: R213.2 ; sheet Designator/CAN_RX
CAN_TX: R215.2 ; sheet Designator/CAN_TX
CS_Batt1: R179.2 ; sheet Designator/CS_Batt1
CS_Batt1+: J10.6 ; sheet Designator/CS_Batt1+
CS_Batt1-: J10.8 ; sheet Designator/CS_Batt1-
CS_Batt2: R184.2 ; sheet Designator/CS_Batt2
CS_Batt2+: J10.14 ; sheet Designator/CS_Batt2+
CS_Batt2-: J10.16 ; sheet Designator/CS_Batt2-
CS_Boost1: R187.1 ; sheet Designator/CS_Boost1
CS_Boost1+: J10.7 ; sheet Designator/CS_Boost1+
CS_Boost1-: J10.9 ; sheet Designator/CS_Boost1-
CS_Boost2: R188.1 ; sheet Designator/CS_Boost2
CS_Boost2+: J10.3 ; sheet Designator/CS_Boost2+
CS_Boost2-: J10.5 ; sheet Designator/CS_Boost2-
Enable_Buffer_ACDC: R232.2 R254.2 U28.1(~{OE1}) U28.15(~{OE2})
Enable_Buffer_DCDC: J10.4 R230.2 R253.2 U29.1(~{OE1}) U29.15(~{OE2})
Enable_CAN: R224.2 ; sheet Designator/Enable_CAN
Enable_RS485: R226.2 ; sheet Designator/Enable_RS485
~{FAULT}_~{OC}_Batt_H1_Buff: C137.2 J12.19 R219.1
~{FAULT}_~{OC}_Batt_H2_Buff: C130.2 J12.14 R223.1
~{FAULT}_~{OC}_Batt_L1_Buff: C231.2 J12.21 R221.1
~{FAULT}_~{OC}_Batt_L2_Buff: C131.2 J12.16 R225.1
~{FAULT}_~{OC}_Boost1_Buff: C135.2 J12.15 R227.1
~{FAULT}_~{OC}_Boost2_Buff: C136.2 J12.17 R217.1
~{FAULT}_~{OC}_S1: R204.2 ; port ~{FAULT}_~{OC}_S1
~{FAULT}_~{OC}_S2_init: R203.1 ; port ~{FAULT}_~{OC}_S2_init
~{FAULT}_~{OC}_S3: R206.2 ; port ~{FAULT}_~{OC}_S3
~{FAULT}_~{OC}_S4_init: R205.1 ; port ~{FAULT}_~{OC}_S4_init
~{FAULT}_~{OC}_S5: R207.2 ; port ~{FAULT}_~{OC}_S5
~{FAULT}_~{OC}_S6: R208.2 ; port ~{FAULT}_~{OC}_S6
IAC_~{FAULT}: R229.1 ; port IAC_~{FAULT}
IAC_~{OC}: R231.1 ; port IAC_~{OC}
IAC_REF: R181.1 ; port IAC_REF
IAC_sense: R180.1 ; port IAC_sense
PWM_S1: R190.1 R260.1
PWM_S1_Buff: J22.1 R21.2 R144.2 ; port PWM_S1_Buff
PWM_S2: R192.1 R265.1
PWM_S2_Buff: J4.2 J24.2 ; port PWM_S2_Buff
PWM_S3: R194.1 R268.1
PWM_S3_Buff: J14.2 J21.2 J25.2 ; port PWM_S3_Buff
PWM_S4: R196.1 R273.1
PWM_S4_Buff: J20.2 J22.2 ; port PWM_S4_Buff
PWM_S5: R191.2 R276.1
PWM_S5_Buff: J5.2 J26.2 ; port PWM_S5_Buff
PWM_S6: R193.2 R281.1
PWM_S6_Buff: J13.2 J23.2 ; port PWM_S6_Buff
RS485_D: R211.2 ; sheet Designator/RS485_D
RS485_DE_~{RE}: R228.2 ; sheet Designator/RS485_DE_~{RE}
RS485_R: R209.2 ; sheet Designator/RS485_R
RY_DCPreCharge: J10.22 R234.2
RY_PreCharge: R236.2 ; port RY_PreCharge
TEMP_ACDC: C129.1 R222.2 U23.5(Y)
TEMP_AMB_sense: R182.2 ; port TEMP_AMB_sense
TEMP_Batt_H1_Buff: C177.2 J12.4 U24.2(D2)
TEMP_Batt_H2_Buff: C179.2 J12.12 U24.15(D4)
TEMP_Batt_L1_Buff: C178.2 J12.2 U24.1(D3)
TEMP_Batt_L2_Buff: C180.2 J12.10 U24.14(D5)
TEMP_Boost1_Buff: C174.2 J12.8 U24.4(D0)
TEMP_Boost2_Buff: C175.2 J12.6 U24.3(D1)
TEMP_DCDC: C138.1 R233.1 U24.5(Y)
TEMP_MUX_A: R216.2 U23.11(A) U24.11(A)
TEMP_MUX_B: R218.2 U23.10(B) U24.10(B)
TEMP_MUX_C: R220.2 U23.9(C) U24.9(C)
TEMP_S1: C167.2 U23.4(D0) ; port TEMP_S1
TEMP_S2: C168.2 R39.2 U23.3(D1)
TEMP_S2_init: R38.1 ; port TEMP_S2_init
TEMP_S3: C170.2 U23.2(D2) ; port TEMP_S3
TEMP_S4: C171.2 R73.2 U23.1(D3)
TEMP_S4_init: R72.1 ; port TEMP_S4_init
TEMP_S5: C172.2 U23.15(D4) ; port TEMP_S5
TEMP_S6: C173.2 U23.14(D5) ; port TEMP_S6
VAC_sense: R178.1 ; port VAC_sense
VDC_sense: R174.2 ; port VDC_sense
Vinv_sense: R176.1 ; port Vinv_sense
VS_Batt1: R183.2 ; sheet Designator/VS_Batt1
VS_Batt1+: J10.10 ; sheet Designator/VS_Batt1+
VS_Batt1-: J10.12 ; sheet Designator/VS_Batt1-
VS_Boost1: R186.1 ; sheet Designator/VS_Boost1
VS_Boost1+: J10.15 ; sheet Designator/VS_Boost1+
VS_Boost1-: J10.17 ; sheet Designator/VS_Boost1-
VS_Boost2: R189.1 ; sheet Designator/VS_Boost2
VS_Boost2+: J10.11 ; sheet Designator/VS_Boost2+
VS_Boost2-: J10.13 ; sheet Designator/VS_Boost2-
VS_DCDC_VDC+: J12.18 ; port VS_DCDC_VDC+
VS_DCDC_VDC-: J12.20 ; port VS_DCDC_VDC-
VS_DCDC_VDC_sense: R67.2 ; port VS_DCDC_VDC_sense
NetC55_2: C55.2 FB11.2 U27.5(VCC)
NetC93_2: C93.2 R38.2 R252.2 U27.1(1A)
NetC101_2: C101.2 R72.2 R256.2 U27.3(2A)
NetC181_2: C181.2 C182.1 FB9.2 J11.48 J11.84 J11.98 J11.112
NetC190_2: C190.2 R250.1 R263.2 R308.2 U29.2(A1)
NetC192_2: C192.2 R21.1 R260.2 R302.2 U28.2(A1)
NetC193_2: C193.2 R248.1 R267.2 R307.2 U29.4(A2)
NetC194_2: C194.2 R249.1 R265.2 R301.2 U28.4(A2)
NetC196_2: C196.2 R247.1 R268.2 R300.2 U28.6(A3)
NetC199_2: C199.2 R246.1 R270.2 R306.2 U29.6(A3)
NetC200_2: C200.2 R245.1 R273.2 R299.2 U28.10(A4)
NetC202_2: C202.2 R244.1 R274.2 R305.2 U29.10(A4)
NetC204_2: C204.2 R243.1 R276.2 R298.2 U28.12(A5)
NetC206_2: C206.2 R241.1 R281.2 R297.2 U28.14(A6)
NetC208_2: C208.2 R242.1 R278.2 R304.2 U29.12(A5)
NetC209_2: C209.2 R240.1 R282.2 R303.2 U29.14(A6)
NetD23_1: D23.1(CATHODE) R70.2
NetD23_2: D23.2(ANODE) J11.107
NetD24_1: D24.1(CATHODE) R76.2
NetD24_2: D24.2(ANODE) J11.109
NetJ4_1: J4.1 J21.1 J23.1 R146.2 R249.2
NetJ5_1: J5.1 R154.2 R243.2
NetJ8_2: J8.2 R57.1
NetJ8_3: J8.3 R210.1
NetJ8_4: J8.4 R212.1
NetJ8_5: J8.5 R214.1
NetJ11_12: J11.12 R174.1
NetJ11_18: J11.18 R179.1
NetJ11_21: J11.21 R183.1
NetJ11_23: J11.23 R182.1
NetJ11_24: J11.24 R181.2
NetJ11_25: J11.25 R184.1
NetJ11_26: J11.26 R180.2
NetJ11_27: J11.27 R67.1
NetJ11_28: J11.28 R178.2
NetJ11_30: J11.30 R176.2
NetJ11_31: J11.31 R186.2
NetJ11_33: J11.33 R187.2
NetJ11_39: J11.39 R189.2
NetJ11_40: J11.40 R188.2
NetJ11_49: J11.49 R190.2
NetJ11_50: J11.50 R194.2
NetJ11_51: J11.51 R192.2
NetJ11_52: J11.52 R196.2
NetJ11_53: J11.53 R198.2
NetJ11_54: J11.54 R191.1
NetJ11_55: J11.55 R199.2
NetJ11_56: J11.56 R193.1
NetJ11_57: J11.57 R200.2
NetJ11_59: J11.59 R201.2
NetJ11_61: J11.61 R195.1
NetJ11_63: J11.63 R197.1
NetJ11_67: J11.67 R203.2
NetJ11_68: J11.68 R204.1
NetJ11_69: J11.69 R205.2
NetJ11_70: J11.70 R206.1
NetJ11_72: J11.72 R207.1
NetJ11_74: J11.74 R208.1
NetJ11_75: J11.75 R57.2
NetJ11_76: J11.76 R209.1
NetJ11_77: J11.77 R210.2
NetJ11_78: J11.78 R211.1
NetJ11_79: J11.79 R212.2
NetJ11_80: J11.80 R213.1
NetJ11_81: J11.81 R214.2
NetJ11_82: J11.82 R215.1
NetJ11_86: J11.86 R216.1
NetJ11_87: J11.87 R217.2
NetJ11_88: J11.88 R218.1
NetJ11_89: J11.89 R219.2
NetJ11_90: J11.90 R220.1
NetJ11_91: J11.91 R221.2
NetJ11_92: J11.92 R222.1
NetJ11_93: J11.93 R223.2
NetJ11_94: J11.94 R224.1
NetJ11_95: J11.95 R225.2
NetJ11_96: J11.96 R226.1
NetJ11_99: J11.99 R227.2
NetJ11_100: J11.100 R228.1
NetJ11_101: J11.101 R229.2
NetJ11_102: J11.102 R230.1
NetJ11_103: J11.103 R231.2
NetJ11_104: J11.104 R232.1
NetJ11_105: J11.105 R233.2
NetJ11_106: J11.106 R234.1
NetJ11_108: J11.108 R236.1
NetJ13_1: J13.1 R175.2 R241.2
NetJ14_1: J14.1 J24.1 J25.1 R148.2 R247.2
NetJ20_1: J20.1 J26.1 R152.2 R245.2
NetR39_1: R39.1 U27.6(1Y)
NetR73_1: R73.1 U27.4(2Y)
NetR144_1: R144.1 U28.3(Y1)
NetR146_1: R146.1 U28.5(Y2)
NetR148_1: R148.1 U28.7(Y3)
NetR152_1: R152.1 U28.9(Y4)
NetR154_1: R154.1 U28.11(Y5)
NetR175_1: R175.1 U28.13(Y6)
NetR177_2: R177.2 U23.7(~{OE})
NetR202_2: R202.2 U24.7(~{OE})
NetR240_2: R240.2 R286.1 U29.13(Y6)
NetR242_2: R242.2 R284.1 U29.11(Y5)
NetR244_2: R244.2 R279.1 U29.9(Y4)
NetR246_2: R246.2 R272.1 U29.7(Y3)
NetR248_2: R248.2 R264.1 U29.5(Y2)
NetR250_2: R250.2 R259.1 U29.3(Y1)

Not connected (* = marked no-connect by the designer): J8 6*; J10 18* 19* 20* 21*; J11 1* 2* 3* 4* 5* 6* 8* 9* 11* 14* 15* 17* 20* 32* 34* 36* 37* 41* 42* 43* 44* 45* 58* 60* 62* 64* 66* 71* 73* 85* 110* 113* 114* 115* 116* 117* 118* 119* 120*; J12 22*; U23 6(~{W})*; U24 6(~{W})*

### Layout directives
net class HVN: 3V3_HVN, 5V_HVN, 12V_HVN, Batt_H1, Batt_H1_Buff, Batt_H2, Batt_H2_Buff, Batt_L1, Batt_L1_Buff, Batt_L2, Batt_L2_Buff, Boost_S1, Boost_S1_Buff, Boost_S2, Boost_S2_Buff, CAN_RX, CAN_TX, CS_Batt1, CS_Batt1+, CS_Batt1-, CS_Batt2, CS_Batt2+, CS_Batt2-, CS_Boost1, CS_Boost1+, CS_Boost1-, CS_Boost2, CS_Boost2+, CS_Boost2-, Enable_Buffer_ACDC, Enable_Buffer_DCDC, Enable_CAN, Enable_RS485, GND_HVN, PWM_S1, PWM_S2, PWM_S3, PWM_S4, PWM_S5, PWM_S6, RS485_D, RS485_DE_~{RE}, RS485_R, RY_DCPreCharge, TEMP_ACDC, TEMP_Batt_H1_Buff, TEMP_Batt_H2_Buff, TEMP_Batt_L1_Buff, TEMP_Batt_L2_Buff, TEMP_Boost1_Buff, TEMP_Boost2_Buff, TEMP_DCDC, TEMP_MUX_A, TEMP_MUX_B, TEMP_MUX_C, TEMP_S2, TEMP_S4, VS_Batt1, VS_Batt1+, VS_Batt1-, VS_Boost1, VS_Boost1+, VS_Boost1-, VS_Boost2, VS_Boost2+, VS_Boost2-, ~{FAULT}_~{OC}_Batt_H1_Buff, ~{FAULT}_~{OC}_Batt_H2_Buff, ~{FAULT}_~{OC}_Batt_L1_Buff, ~{FAULT}_~{OC}_Batt_L2_Buff, ~{FAULT}_~{OC}_Boost1_Buff, ~{FAULT}_~{OC}_Boost2_Buff

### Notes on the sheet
- CONTROL CARD
- MUX FOR TEMP. MEASUREMENT
- CONNECTORS TO&FRO DC/DC
- IMPORTANT NOTE:
  Currently with TMS320F280039C
- VCC= -0.5 to 7V
  VIN= 2 to 6V
- IMPORTANT NOTE:
  If using TMS320F28P55x:
  -Swap signals CS_Batt2 & VS_Batt1
  -Swap signals CS_Boost2 & VS_DCDC_VDC_sense
  and route the signals  in the layout accordingly
- Vf=2V, Iled=6mA
- MEASUREMENT SIGNALS FROM DC/DC
- (near R76) Vf=2,2V, Iled=20mA
- COMMUNICATION WITH BATTERY
- PWM SIGNAL BUFFER AC/DC
- PWM SIGNAL BUFFER DC/DC
- H-Bridge
- LEVEL SHIFTING
- Unipolar
- Bipolar
- VCC= 2 to 5.5V
  VIN= 0 to 5.5V
  Active-low output-enable
- HERIC

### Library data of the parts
C55 C169 C176 C182 C201 C203 = CMP-0006752-5: CAP, CERM, 0.1 uF, 25 V, +/- 5%, X7R, 0603; Manufacturer: AVX; TaMin_C: -55°C; ESR_ohm: 0.05; Polarized: N; SizeAreaWB_mm2: 4.68; Value1: 0.05 ohm; U/M: EA; Value: 0.1uF; TaMax_C: 125°C; SizeZ_mm: 1; SizeX_mm: 1.6; SizeY_mm: 0.8; SizeArea_mm2: 1.28; AEC Category: Q200
C93 C101 C130 C131 C135-C137 C167 C168 C170-C175 C177-C180 C190 C192-C194 C196 C199 C200 C202 C204 C206 C208 C209 C231 = CMP-0007442-5: CAP, CERM, 220 pF, 50 V, +/- 10%, X7R, 0603; Manufacturer: MuRata; TaMin_C: -55°C; Polarized: N; SizeAreaWB_mm2: 4.68; Value1: Unknown; U/M: EA; Value: 220pF; TaMax_C: 125°C; SizeZ_mm: 1; SizeX_mm: 1.6; SizeY_mm: 0.8; SizeArea_mm2: 1.28; AEC Category: Q200
C129 C138 = CMP-0006840-4: CAP, CERM, 100 pF, 50 V, +/- 5%, C0G/NP0, 0603; Manufacturer: Kemet; TaMin_C: -55°C; Polarized: N; SizeAreaWB_mm2: 4.68; Value1: Unknown; U/M: EA; Value: 100pF; TaMax_C: 125°C; SizeZ_mm: 1; SizeX_mm: 1.6; SizeY_mm: 0.8; SizeArea_mm2: 1.28; AEC Category: Q200
C181 = CMP-0086152-1: CAP, CERM, 1 µF, 25 V,+/- 10%, X5R, 0603; Manufacturer: Taiyo Yuden; SizeAreaWB_mm2: 4.68; SizeZ_mm: 1; U/M: EA; Green_REACh: Passed; Value: 1uF; AEC Qualified: N; TaMax_C: 85°C; Green_Lifecycle: Active; AEC Category: Q200; SizeArea_mm2: 1.28; TaMin_C: -55°C; SizeY_mm: 0.8; SizeX_mm: 1.6
D23 D24 = CMP-0093310-1: Standard LEDs - SMD Green TOPLED E 1608; Manufacturer: Osram Opto; AEC Grade: Grade 2; LambdaP: 572nm; SizeZ_mm: 0.7mm; LuminousFlux_PhiV: 0.016-0.0295lm; Luminous Intensity: 4.5-9.7mcd; LambdaD: 570nm; Tjmax_C: 125°C; Angle: 120°; Led Orientation: Top View; Forward Current: 2mA; Vf_V: 1.8V; AEC Qualified: Yes; Vr_V: 12V
FB9 FB11 = CMP-0037505-1: 600 Ohms @ 100 MHz 1 Power, Signal Line Ferrite Bead 0603 (1608 Metric) 1A 200mOhm; Manufacturer: Bourns; DCR_ohm: 0.2; SizeZ_mm: 1mm; AEC Qualified: No; Impedance At Frequency: 600Ω @ 100MHz; Test Frequency: 100MHz; Tolerance_%: 25%
J4 J5 J13 J14 J20-J26 = CMP-0054794-2: Header, 2.54 mm, 2x1, Gold, TH; Manufacturer: Wurth Elektronik; Green_Lifecycle: Active; Green_REACh: Passed; Cert_UL: Y; Gender: Male; Pitch_mm: 2.54; Row_Count: 1; Shrouded: N
J8 = CMP-0095208-1: 7 Position Receptacle, Bottom Entry Connector 0.100" (2.54mm) Surface Mount Gold; Manufacturer: Samtec; Conn Orientation: Vertical; Voltage_V: 572V; Current_A: 5.2A; Is Female: yes; AEC Qualified: No; Conn Gender: Female; SizeZ_mm: 7.541mm; ContactFinish: Gold,Nickel; Row_Count: 1
J10 J12 = CMP-0003796-1: Conn Shrouded Header (4 Sides) HDR 24 POS 1.27mm Solder ST Top Entry Thru-Hole Tube; Manufacturer: Samtec; ContactFinish: Gold,Nickel; Row_Count: 2; AEC Qualified: No; Conn Gender: Male; Conn Orientation: Straight; SizeZ_mm: 5.46mm; Standoff Height: 0.38mm
J11 = CMP-0003814-2: C2000 controlCARD-120HSEC connector, SMT; Manufacturer: Samtec; Note: The pin numbering does not match Samtec datasheet
R21 R57 R67 R174 R176-R184 R186-R208 R210-R234 R236 R240-R250 = CMP-0081973-1: RES, 0, 0%, 0.25 W, AEC-Q200 Grade 0, 0603; Manufacturer: Vishay-Dale; SizeAreaWB_mm2: 4.68; SizeArea_mm2: 1.28; AEC Qualified: Y; AEC Category: Q200; Value: 0; SizeZ_mm: 1; SizeY_mm: 0.8; Power_W: 250mW; Value2: 0.25W; SizeX_mm: 1.6
R38 R39 R72 R73 R144 R146 R148 R152 R154 R175 R259 R260 R263-R265 R267 R268 R270 R272-R274 R276 R278 R279 R281 R282 R284 R286 = CMP-0023572-3: RES, 56, 0.1%, 0.1 W, 0603; Manufacturer: Susumu Co Ltd; Power_W: 100mW; TempCo: 25 ppm/C; Value_Code: 56R0; U/M: EA; Value: 56; SizeX_mm: 1.6; SizeY_mm: 0.8; SizeZ_mm: 1; Value2: 0.1W; SizeArea_mm2: 1.28; VDC_V: 75V; AEC Category: Q200
R70 R76 = CMP-0025936-5: RES, 680, 5%, 0.1 W, 0603; Manufacturer: Yageo; Power_W: 100mW; TempCo: 100 ppm/C; Value_Code: 680R; Value: 680; EIA_Code: E24; SizeX_mm: 1.6; SizeY_mm: 0.8; SizeZ_mm: 1; Value2: 0.1W; SizeArea_mm2: 1.28; AEC Qualified: N; VDC_V: 75V; AEC Category: Q200; SizeAreaWB_mm2: 4.68
R209 = CMP-0081973-1: RES, 0, 0%, 0.25 W, AEC-Q200 Grade 0, 0603; Manufacturer: Vishay-Dale; SizeAreaWB_mm2: 4.68; SizeArea_mm2: 1.28; AEC Qualified: Y; AEC Category: Q200; SizeZ_mm: 1; SizeY_mm: 0.8; Power_W: 250mW; Value2: 0.25W; SizeX_mm: 1.6
R252-R254 R256 R297-R308 = CMP-0023404-3: RES, 10.0 k, 0.1%, 0.1 W, 0603; Manufacturer: Susumu Co Ltd; Power_W: 100mW; TempCo: 25 ppm/C; Value_Code: 10k0; U/M: EA; Value: 10.0k; EIA_Code: E192; Res_ohm: 10k; SizeX_mm: 1.6; SizeY_mm: 0.8; SizeZ_mm: 1; Value2: 0.1W; SizeArea_mm2: 1.28; VDC_V: 75V; AEC Category: Q200
TP12 = CMP-0055138-2: Test Point, Miniature, Black, TH; Manufacturer: Keystone Electronics; ContactFinish: Silver; CNHeader: FALSE; Green_Lifecycle: Active; Green_REACh: Passed; CT: TRUE
U23 U24 = CMP-0045028-1: Data Selectors/Multiplexers With 3-State Outputs, PW0016A, TUBE; Manufacturer: Texas Instruments; Channels(#): 1; F @ Nom Voltage(Max)(Mhz): 28; Function: Encoder/Multiplexer; tpd @ Nom Voltage(Max)(ns): 51; ICC @ Nom Voltage(Max)(mA): 0.08; Input Type: LVTTL/CMOS; Schmitt Trigger: No; Bits(#): 8; Output Type: CMOS; Configuration: 8：1; VCC(Max)(V): 6; Output Drive (IOL/IOH)(Max)(mA): 7.8/-7.8; Rating: Catalog; VCC(Min)(V): 2; Technology Family: HC; Voltage(Nom)(V): 3.3,5
U27 = CMP-0051910-1: Dual Buffer Gate, DBV0006A, LARGE T&R; Manufacturer: Texas Instruments; Logic: True; F @ Nom Voltage(Max)(Mhz): 150; Output Type: CMOS; Output Drive (IOL/IOH)(Max)(mA): 32/-32; Voltage(Nom)(V): 1.8,2.5,3.3,5; 3-State Output: No; VCC(Max)(V): 5.5; ICC @ Nom Voltage(Max)(mA): 0.01; Technology Family: LVC; Input Type: CMOS/TTL; VCC(Min)(V): 1.65; Bits(#): 2; tpd @ Nom Voltage(Max)(ns): 8.6,4.4,4.1,3.2; Rating: Catalog; Sub-Family: Non-Inverting Buffer/Driver
U28 U29 = CMP-0047247-1: Hex Buffers And Line Drivers With 3-State Outputs, D0016A, TUBE; Manufacturer: Texas Instruments; Rating: Catalog; Bits(#): 6; Input Type: CMOS; ICC @ Nom Voltage(Max)(mA): 0.08; VCC(Min)(V): 2; tpd @ Nom Voltage(Max)(ns): 20; F @ Nom Voltage(Max)(Mhz): 28

## Sheet TIDA-010938 AC-DC_Communication.SchDoc
size 431 x 279 mm; Date: Not shown in title block; ApprovedBy: Not shown in title block; CheckedBy: Not shown in title block; Author: Not shown in title block; CompanyName: Not shown in title block; Engineer: Not shown in title block; Organization: Not shown in title block; Address1: Not shown in title block; Address2: Not shown in title block; Address3: Not shown in title block; Address4: Not shown in title block; DocumentNumber: 10; Revision: Use project parameter SCH_Rev; SheetNumber: 10; SheetTotal: 11; PageSetup: Record=PageOptions¦CenterHorizontal=True¦CenterVertical=True¦PrintScale=1.00¦XCorrection=1.00¦YCorrection=1.00¦PrintKind=0¦BorderSize=5000000¦LeftOffset=0¦BottomOffset=0¦Orientation=2¦PaperLength=1000¦PaperWidth=1000¦Scale=100¦PaperSource=15¦PrintQuality=600¦MediaType=1¦DitherType=10¦PaperKind=Letter¦PrintScaleMode=1

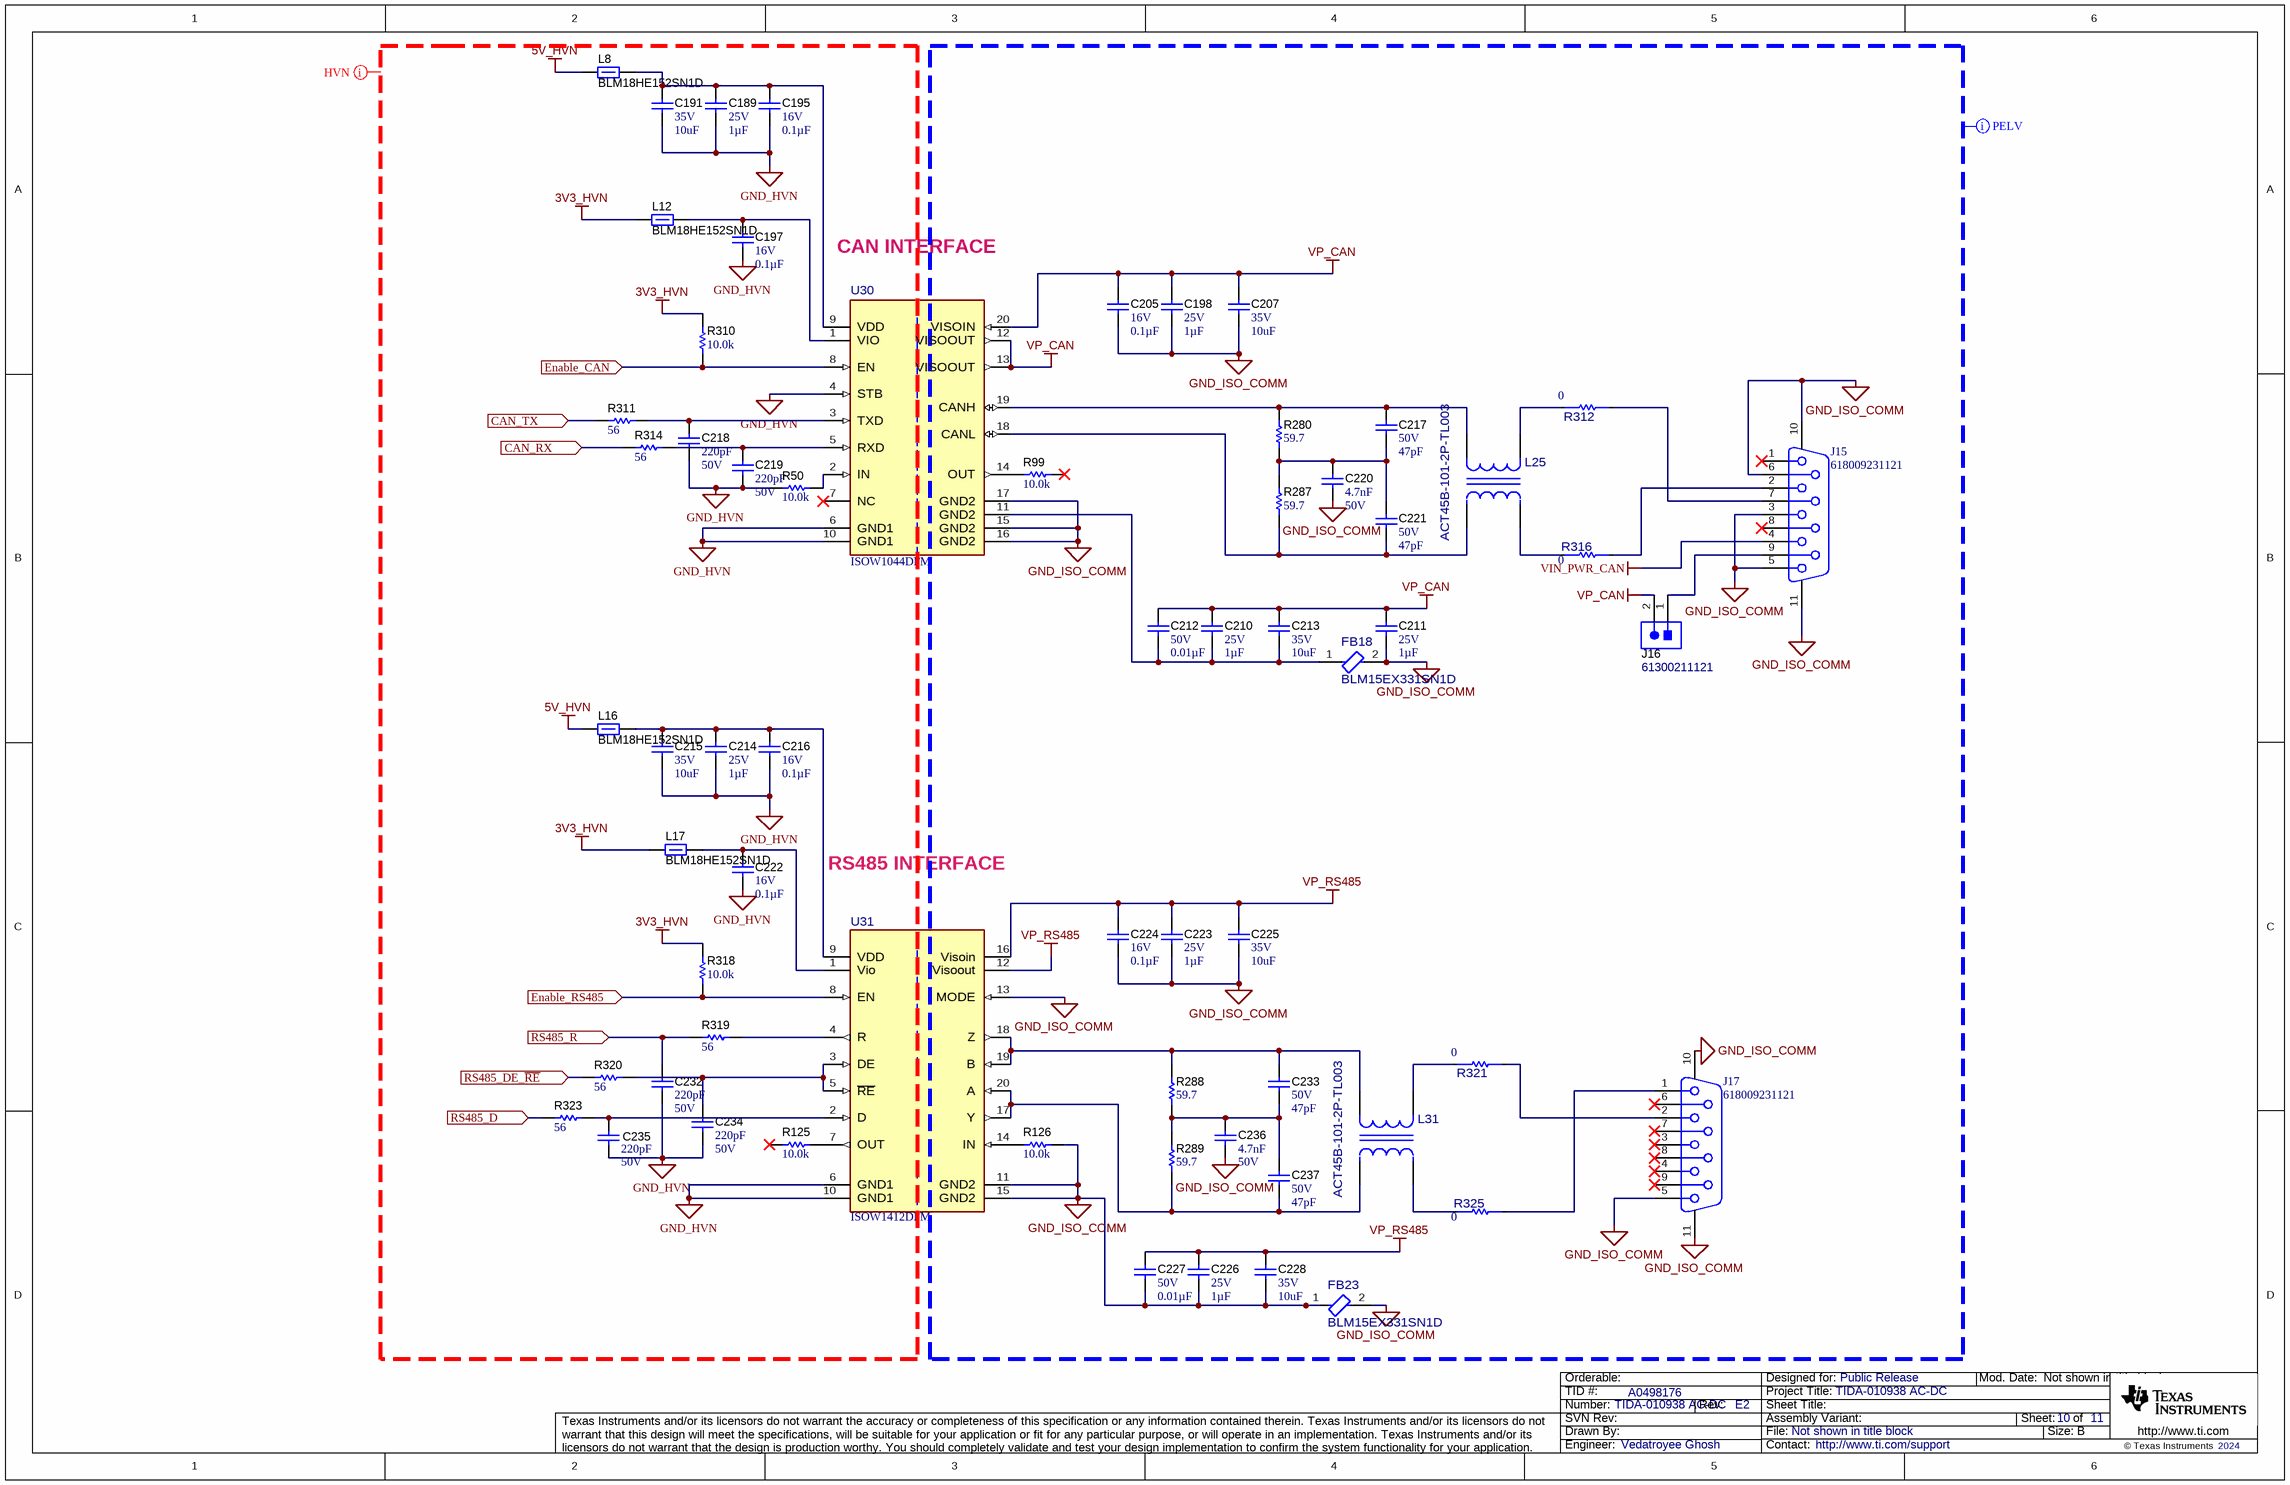
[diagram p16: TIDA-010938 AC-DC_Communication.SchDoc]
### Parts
C189  VDC_V: 25V  ValueDisplayed: 1µF  [0603]  (hidden comment: TMK107BJ105KA-T)
C191  VDC_V: 35V  ValueDisplayed: 10uF  [0805_HV]  (hidden comment: GRM21BR6YA106KE43L)
C195  VDC_V: 16V  ValueDisplayed: 0.1µF  [0402]  (hidden comment: CL05B104KO5NNNC)
C197  VDC_V: 16V  ValueDisplayed: 0.1µF  [0402]  (hidden comment: CL05B104KO5NNNC)
C198  VDC_V: 25V  ValueDisplayed: 1µF  [0603]  (hidden comment: TMK107BJ105KA-T)
C205  VDC_V: 16V  ValueDisplayed: 0.1µF  [0402]  (hidden comment: CL05B104KO5NNNC)
C207  VDC_V: 35V  ValueDisplayed: 10uF  [0805_HV]  (hidden comment: GRM21BR6YA106KE43L)
C210  VDC_V: 25V  ValueDisplayed: 1µF  [0603]  (hidden comment: TMK107BJ105KA-T)
C211  VDC_V: 25V  ValueDisplayed: 1µF  [0603]  (hidden comment: TMK107BJ105KA-T)
C212  VDC_V: 50V  ValueDisplayed: 0.01µF  [0402]  (hidden comment: 0402B103K500CT)
C213  VDC_V: 35V  ValueDisplayed: 10uF  [0805_HV]  (hidden comment: GRM21BR6YA106KE43L)
C214  VDC_V: 25V  ValueDisplayed: 1µF  [0603]  (hidden comment: TMK107BJ105KA-T)
C215  VDC_V: 35V  ValueDisplayed: 10uF  [0805_HV]  (hidden comment: GRM21BR6YA106KE43L)
C216  VDC_V: 16V  ValueDisplayed: 0.1µF  [0402]  (hidden comment: CL05B104KO5NNNC)
C217  VDC_V: 50V  ValueDisplayed: 47pF  [0603]  (hidden comment: GRM1885C1H470JA01D)
C218  Cap_F: 220pF  VDC_V: 50V  [0603]  (hidden comment: GRM188R71H221KA01D)
C219  Cap_F: 220pF  VDC_V: 50V  [0603]  (hidden comment: GRM188R71H221KA01D)
C220  Cap_F: 4.7nF  VDC_V: 50V  [0603]  (hidden comment: C0603X472K5RACTU)
C221  VDC_V: 50V  ValueDisplayed: 47pF  [0603]  (hidden comment: GRM1885C1H470JA01D)
C222  VDC_V: 16V  ValueDisplayed: 0.1µF  [0402]  (hidden comment: CL05B104KO5NNNC)
C223  VDC_V: 25V  ValueDisplayed: 1µF  [0603]  (hidden comment: TMK107BJ105KA-T)
C224  VDC_V: 16V  ValueDisplayed: 0.1µF  [0402]  (hidden comment: CL05B104KO5NNNC)
C225  VDC_V: 35V  ValueDisplayed: 10uF  [0805_HV]  (hidden comment: GRM21BR6YA106KE43L)
C226  VDC_V: 25V  ValueDisplayed: 1µF  [0603]  (hidden comment: TMK107BJ105KA-T)
C227  VDC_V: 50V  ValueDisplayed: 0.01µF  [0402]  (hidden comment: 0402B103K500CT)
C228  VDC_V: 35V  ValueDisplayed: 10uF  [0805_HV]  (hidden comment: GRM21BR6YA106KE43L)
C232  Cap_F: 220pF  VDC_V: 50V  [0603]  (hidden comment: GRM188R71H221KA01D)
C233  VDC_V: 50V  ValueDisplayed: 47pF  [0603]  (hidden comment: GRM1885C1H470JA01D)
C234  Cap_F: 220pF  VDC_V: 50V  [0603]  (hidden comment: GRM188R71H221KA01D)
C235  Cap_F: 220pF  VDC_V: 50V  [0603]  (hidden comment: GRM188R71H221KA01D)
C236  Cap_F: 4.7nF  VDC_V: 50V  [0603]  (hidden comment: C0603X472K5RACTU)
C237  VDC_V: 50V  ValueDisplayed: 47pF  [0603]  (hidden comment: GRM1885C1H470JA01D)
FB18  BLM15EX331SN1D  [FP-BLM15EX331SN1D_0402-MFG]
FB23  BLM15EX331SN1D  [FP-BLM15EX331SN1D_0402-MFG]
J15  618009231121  [Wurth_618009231121]
J16  61300211121  [WURTH_61300211121]
J17  618009231121  [Wurth_618009231121]
L8  BLM18HE152SN1D  [0603]
L12  BLM18HE152SN1D  [0603]
L16  BLM18HE152SN1D  [0603]
L17  BLM18HE152SN1D  [0603]
L25  ACT45B-101-2P-TL003  [FP-ACT45B-101-2P-TL003_SMT_4MM5_3MM2-MFG]
L31  ACT45B-101-2P-TL003  [FP-ACT45B-101-2P-TL003_SMT_4MM5_3MM2-MFG]
R50  ValueDisplayed: 10.0k  [0603]  (hidden comment: RG1608P-103-B-T5)
R99  ValueDisplayed: 10.0k  [0603]  (hidden comment: RG1608P-103-B-T5)
R125  ValueDisplayed: 10.0k  [0603]  (hidden comment: RG1608P-103-B-T5)
R126  ValueDisplayed: 10.0k  [0603]  (hidden comment: RG1608P-103-B-T5)
R280  ValueDisplayed: 59.7  [0603]  (hidden comment: RT0603DRE0759R7L)
R287  ValueDisplayed: 59.7  [0603]  (hidden comment: RT0603DRE0759R7L)
R288  ValueDisplayed: 59.7  [0603]  (hidden comment: RT0603DRE0759R7L)
R289  ValueDisplayed: 59.7  [0603]  (hidden comment: RT0603DRE0759R7L)
R310  ValueDisplayed: 10.0k  [0603]  (hidden comment: RG1608P-103-B-T5)
R311  ValueDisplayed: 56  [0603]  (hidden comment: RG1608P-560-B-T5)
R312  Res_ohm: 0  [FP-RMCF0805ZT0R00_0805-MFG]  (hidden comment: RMCF0805ZT0R00)
R314  ValueDisplayed: 56  [0603]  (hidden comment: RG1608P-560-B-T5)
R316  Res_ohm: 0  [FP-RMCF0805ZT0R00_0805-MFG]  (hidden comment: RMCF0805ZT0R00)
R318  ValueDisplayed: 10.0k  [0603]  (hidden comment: RG1608P-103-B-T5)
R319  ValueDisplayed: 56  [0603]  (hidden comment: RG1608P-560-B-T5)
R320  ValueDisplayed: 56  [0603]  (hidden comment: RG1608P-560-B-T5)
R321  Res_ohm: 0  [FP-RMCF0805ZT0R00_0805-MFG]  (hidden comment: RMCF0805ZT0R00)
R323  ValueDisplayed: 56  [0603]  (hidden comment: RG1608P-560-B-T5)
R325  Res_ohm: 0  [FP-RMCF0805ZT0R00_0805-MFG]  (hidden comment: RMCF0805ZT0R00)
U30  ISOW1044DFM  [DFM0020A-MFG]
U31  ISOW1412DFM  [DFM0020A-MFG]

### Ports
CAN_RX (in), CAN_TX (in), Enable_CAN (in), Enable_RS485 (in), RS485_D (in), RS485_DE_~{RE} (in), RS485_R (in)

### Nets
3V3_HVN: L12.1 L17.1 R310.2 R318.2
5V_HVN: L8.1 L16.1
GND_HVN: C189.1 C191.2 C195.2 C197.2 C214.1 C215.2 C216.2 C218.1 C219.1 C222.2 C232.1 C234.1 C235.1 R50.2 U30.4(STB) U30.6(GND1) U30.10(GND1) U31.6(GND1) U31.10(GND1)  [project net DC Bus-]
GND_ISO_COMM: C198.1 C205.2 C207.2 C211.1 C220.1 C223.1 C224.2 C225.2 C226.1 C227.2 C228.2 C236.1 FB18.2 FB23.1 FB23.2 J15.3 J15.5 J15.6 J15.10 J15.11 J17.5 J17.10 J17.11 R126.1 U30.15(GND2) U30.16(GND2) U30.17(GND2) U31.11(GND2) U31.13(MODE) U31.15(GND2)
VIN_PWR_CAN: J15.4
VP_CAN: C198.2 C205.1 C207.1 C210.2 C211.2 C212.1 C213.1 J16.2 U30.12(VISOOUT) U30.13(VISOOUT) U30.20(VISOIN)
VP_RS485: C223.2 C224.1 C225.1 C226.2 C227.1 C228.1 U31.12(Visoout) U31.16(Visoin)
CAN_RX: R314.1 ; port CAN_RX
CAN_TX: R311.1 ; port CAN_TX
Enable_CAN: R310.1 U30.8(EN) ; port Enable_CAN
Enable_RS485: R318.1 U31.8(EN) ; port Enable_RS485
RS485_D: R323.1 ; port RS485_D
RS485_DE_~{RE}: R320.1 ; port RS485_DE_~{RE}
RS485_R: C232.2 R319.1 ; port RS485_R
NetC189_2: C189.2 C191.1 C195.1 L8.2 U30.9(VDD)
NetC197_1: C197.1 L12.2 U30.1(VIO)
NetC210_1: C210.1 C212.2 C213.2 FB18.1 U30.11(GND2)
NetC214_2: C214.2 C215.1 C216.1 L16.2 U31.9(VDD)
NetC217_1: C217.1 C220.2 C221.2 R280.1 R287.2
NetC217_2: C217.2 L25.1 R280.2 U30.19(CANH)
NetC218_2: C218.2 R311.2 U30.3(TXD)
NetC219_2: C219.2 R314.2 U30.5(RXD)
NetC221_1: C221.1 L25.2 R287.1 U30.18(CANL)
NetC222_1: C222.1 L17.2 U31.1(Vio)
NetC233_1: C233.1 C236.2 C237.2 R288.1 R289.2
NetC233_2: C233.2 L31.1 R288.2 U31.18(Z) U31.19(B)
NetC234_2: C234.2 R320.2 U31.3(DE) U31.5(~{RE})
NetC235_2: C235.2 R323.2 U31.2(D)
NetC237_1: C237.1 L31.2 R289.1 U31.17(Y) U31.20(A)
NetJ15_2: J15.2 R316.2
NetJ15_7: J15.7 R312.2
NetJ15_9: J15.9 J16.1
NetJ17_1: J17.1 R325.2
NetJ17_2: J17.2 R321.2
NetL25_3: L25.3 R316.1
NetL25_4: L25.4 R312.1
NetL31_3: L31.3 R325.1
NetL31_4: L31.4 R321.1
NetR50_1: R50.1 U30.2(IN)
NetR99_2: R99.2 U30.14(OUT)
NetR125_1: R125.1 U31.7(OUT)
NetR126_2: R126.2 U31.14(IN)
NetR319_2: R319.2 U31.4(R)

Not connected (* = marked no-connect by the designer): J15 1* 8*; J17 3* 4* 6* 7* 8* 9*; R99 1*; R125 2*; U30 7(NC)*

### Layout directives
net class HVN: 3V3_HVN, 5V_HVN, GND_HVN
net class PELV: GND_ISO_COMM, VIN_PWR_CAN, VP_CAN, VP_RS485

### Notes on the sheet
- CAN INTERFACE
- RS485 INTERFACE

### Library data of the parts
C189 C198 C210 C211 C214 C223 C226 = CMP-0086152-1: as C181 on sheet TIDA-010938 AC-DC_Control Stage
C191 C207 C213 C215 C225 C228 = CMP-0008310-2: CAP, CERM, 10 uF, 35 V, +/- 10%, X5R, 0805; Manufacturer: MuRata; TaMin_C: -55°C; Polarized: N; SizeAreaWB_mm2: 6.75; Value1: Unknown; U/M: EA; Value: 10uF; TaMax_C: 85°C; SizeZ_mm: 1.45; SizeX_mm: 2; SizeY_mm: 1.25; Cap_Case: 0805; SizeArea_mm2: 2.5; Cap_F: 10µF; AEC Category: Q200
C195 C197 C205 C216 C222 C224 = CMP-0085850-1: CAP, CERM, 0.1 µF, 16 V,+/- 10%, X7R, 0402; Manufacturer: Walsin; SizeZ_mm: 0.6; SizeX_mm: 1; AEC Category: Q200; AEC Qualified: N; SizeY_mm: 0.5; Value: 0.1uF; Cap_F: 100nF; U/M: EA; SizeAreaWB_mm2: 3; TaMin_C: -55°C; TaMax_C: 125°C
C212 C227 = CMP-0085842-1: CAP, CERM, 0.01 µF, 50 V,+/- 10%, X7R, 0402; Manufacturer: Walsin; AEC Qualified: N; SizeZ_mm: 0.6; U/M: EA; Value: 0.01uF; TaMax_C: 125°C; AEC Category: Q200; SizeY_mm: 0.5; Cap_F: 10nF; SizeAreaWB_mm2: 3; TaMin_C: -55°C; SizeX_mm: 1
C217 C221 C233 C237 = CMP-0007220-4: CAP, CERM, 47 pF, 50 V, +/- 5%, C0G/NP0, 0603; Manufacturer: MuRata; TaMin_C: -55°C; Polarized: N; SizeAreaWB_mm2: 4.68; Value1: Unknown; U/M: EA; Value: 47pF; TaMax_C: 125°C; SizeZ_mm: 1; SizeX_mm: 1.6; SizeY_mm: 0.8; SizeArea_mm2: 1.28; AEC Category: Q200
C218 C219 C232 C234 C235 = CMP-0007442-5: as C93 on sheet TIDA-010938 AC-DC_Control Stage
C220 C236 = CMP-0006987-4: CAP, CERM, 4700 pF, 50 V, +/- 10%, X7R, 0603; Manufacturer: Kemet; TaMin_C: -55°C; Polarized: N; SizeAreaWB_mm2: 4.68; Value1: Unknown; U/M: EA; Value: 4700pF; TaMax_C: 125°C; SizeZ_mm: 1; SizeX_mm: 1.6; SizeY_mm: 0.8; SizeArea_mm2: 1.28; AEC Category: Q200
FB18 FB23 = CMP-0041881-1: Chip Ferrite Bead, 0402, 330Ω @ 100MHz, 0.205Ω, 25%, 1.1A; Manufacturer: Murata; DCR_ohm: 0.205; SizeZ_mm: 0.55mm; AEC Qualified: No; Ciiva Ids: 2806665; Import Ts: 1521856324
J15 J17 = CMP-0054820-2: Receptacle, D-Sub, 9 Position, R/A, TH; Manufacturer: Wurth Elektronik; Pitch_mm: 2.77; Gender: Female; Cert_UL: Y; Voltage_V: 125V; ContactFinish: Gold; Row_Count: 2; Current_A: 3A; CNHeader: FALSE; CT: TRUE
J16 = CMP-0054794-2: as J4 on sheet TIDA-010938 AC-DC_Control Stage
L8 L12 L16 L17 = CMP-0003349-2: Ferrite Bead, 1500 ohm @ 100 MHz, 0.5 A, 0603; Manufacturer: MuRata; Ztyp@1GHz_Ohm: 1.5k; SizeAreaWB_mm2: 4.68; DCR_ohm: 5d; Value1: 0.5 ohm; Imax_A: 5dA; SizeZ_mm: 1; SizeX_mm: 1.6; SizeY_mm: 0.8; Value2: 0.5A; SizeArea_mm2: 1.28
L25 L31 = CMP-0084086-1: 100µH @ 100kHz 2 Line Common Mode Choke Surface Mount 5.8 kOhms @ 10MHz 150mA DCR 2Ohm; Manufacturer: TDK; AEC Grade: Grade 0; Tolerance_%: +50/-30%; AEC Qualified: Yes; Ind_H: 100uH; SizeZ_mm: 3mm; DCR_ohm: 2Ω; Impedance At Frequency: 5800Ω @ 10MHz; Imax_A: 0.15A
R50 R99 R125 R126 R310 R318 = CMP-0023404-3: as R252-R254 on sheet TIDA-010938 AC-DC_Control Stage
R280 R287-R289 = CMP-0025431-3: RES, 59.7, 0.5%, 0.1 W, 0603; Manufacturer: Yageo America; Power_W: 100mW; TempCo: 50 ppm/C; Value_Code: 59R7; U/M: EA; Value: 59.7; EIA_Code: E192; SizeX_mm: 1.6; SizeY_mm: 0.8; SizeZ_mm: 1; Value2: 0.1W; SizeArea_mm2: 1.28; VDC_V: 75V; AEC Category: Q200
R311 R314 R319 R320 R323 = CMP-0023572-3: as R38 on sheet TIDA-010938 AC-DC_Control Stage
R312 R316 R321 R325 = CMP-0089632-1: 0 Ohms Jumper 0.125W, 1/8W Chip Resistor 0805 (2012 Metric) Automotive AEC-Q200 Thick Film; Manufacturer: Stackpole Electronics; TempCo: 200ppm/°C; SizeZ_mm: 0.65mm; AEC Grade: Grade 0; AEC Qualified: Yes; Power_W: 125mW; VDC_V: 150V
U30 = CMP-0092023-2: Reinforced 5-kVRMS Isolated CAN Transceiver with Integrated lowemissions DC-DC Converter; Manufacturer: Texas Instruments; TJmax_C: +150°C; Max Supply Voltage: 5.5V; AEC Qualified: No; Standoff Height: 0.1mm; Nominal Supply Current: 0.3-124mA; CompType: IC; AEC Category: Q200; TaMax_C: +105°C; SizeZ_mm: 3.55mm; Min Supply Voltage: 1.71V; TaMin_C: -40°C
U31 = CMP-0089988-1: Reinforced 5-kVRMS Isolated RS-485/RS-422 Transceiver With Integrated Low Emissions DC-DC Converter; Manufacturer: Texas Instruments; Simplex Duplex: Full-Duplex; Number Of Transmitters: 1; Data Rate: 500kbits/s; Min Supply Voltage: 1.71V; Interface: RS-485,RS-422; Max Supply Voltage: 5.5V; Standoff Height: 0.1mm; TaMax_C: +105°C; TJmax_C: +150°C; TaMin_C: -40°C; AEC Qualified: No; SizeZ_mm: 3.55mm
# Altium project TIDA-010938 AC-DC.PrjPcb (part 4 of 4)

## Sheet TIDA-010938 AC-DC_OpAmp.SchDoc
size 431 x 279 mm; Date: Not shown in title block; ApprovedBy: Not shown in title block; CheckedBy: Not shown in title block; Author: Not shown in title block; CompanyName: Not shown in title block; Engineer: Not shown in title block; Organization: Not shown in title block; Address1: Not shown in title block; Address2: Not shown in title block; Address3: Not shown in title block; Address4: Not shown in title block; DocumentNumber: 9; Revision: Use project parameter SCH_Rev; SheetNumber: 9; SheetTotal: 11; PageSetup: Record=PageOptions¦CenterHorizontal=True¦CenterVertical=True¦PrintScale=1.00¦XCorrection=1.00¦YCorrection=1.00¦PrintKind=0¦BorderSize=5000000¦LeftOffset=0¦BottomOffset=0¦Orientation=2¦PaperLength=1000¦PaperWidth=1000¦Scale=100¦PaperSource=15¦PrintQuality=600¦MediaType=1¦DitherType=10¦PaperKind=Letter¦PrintScaleMode=1

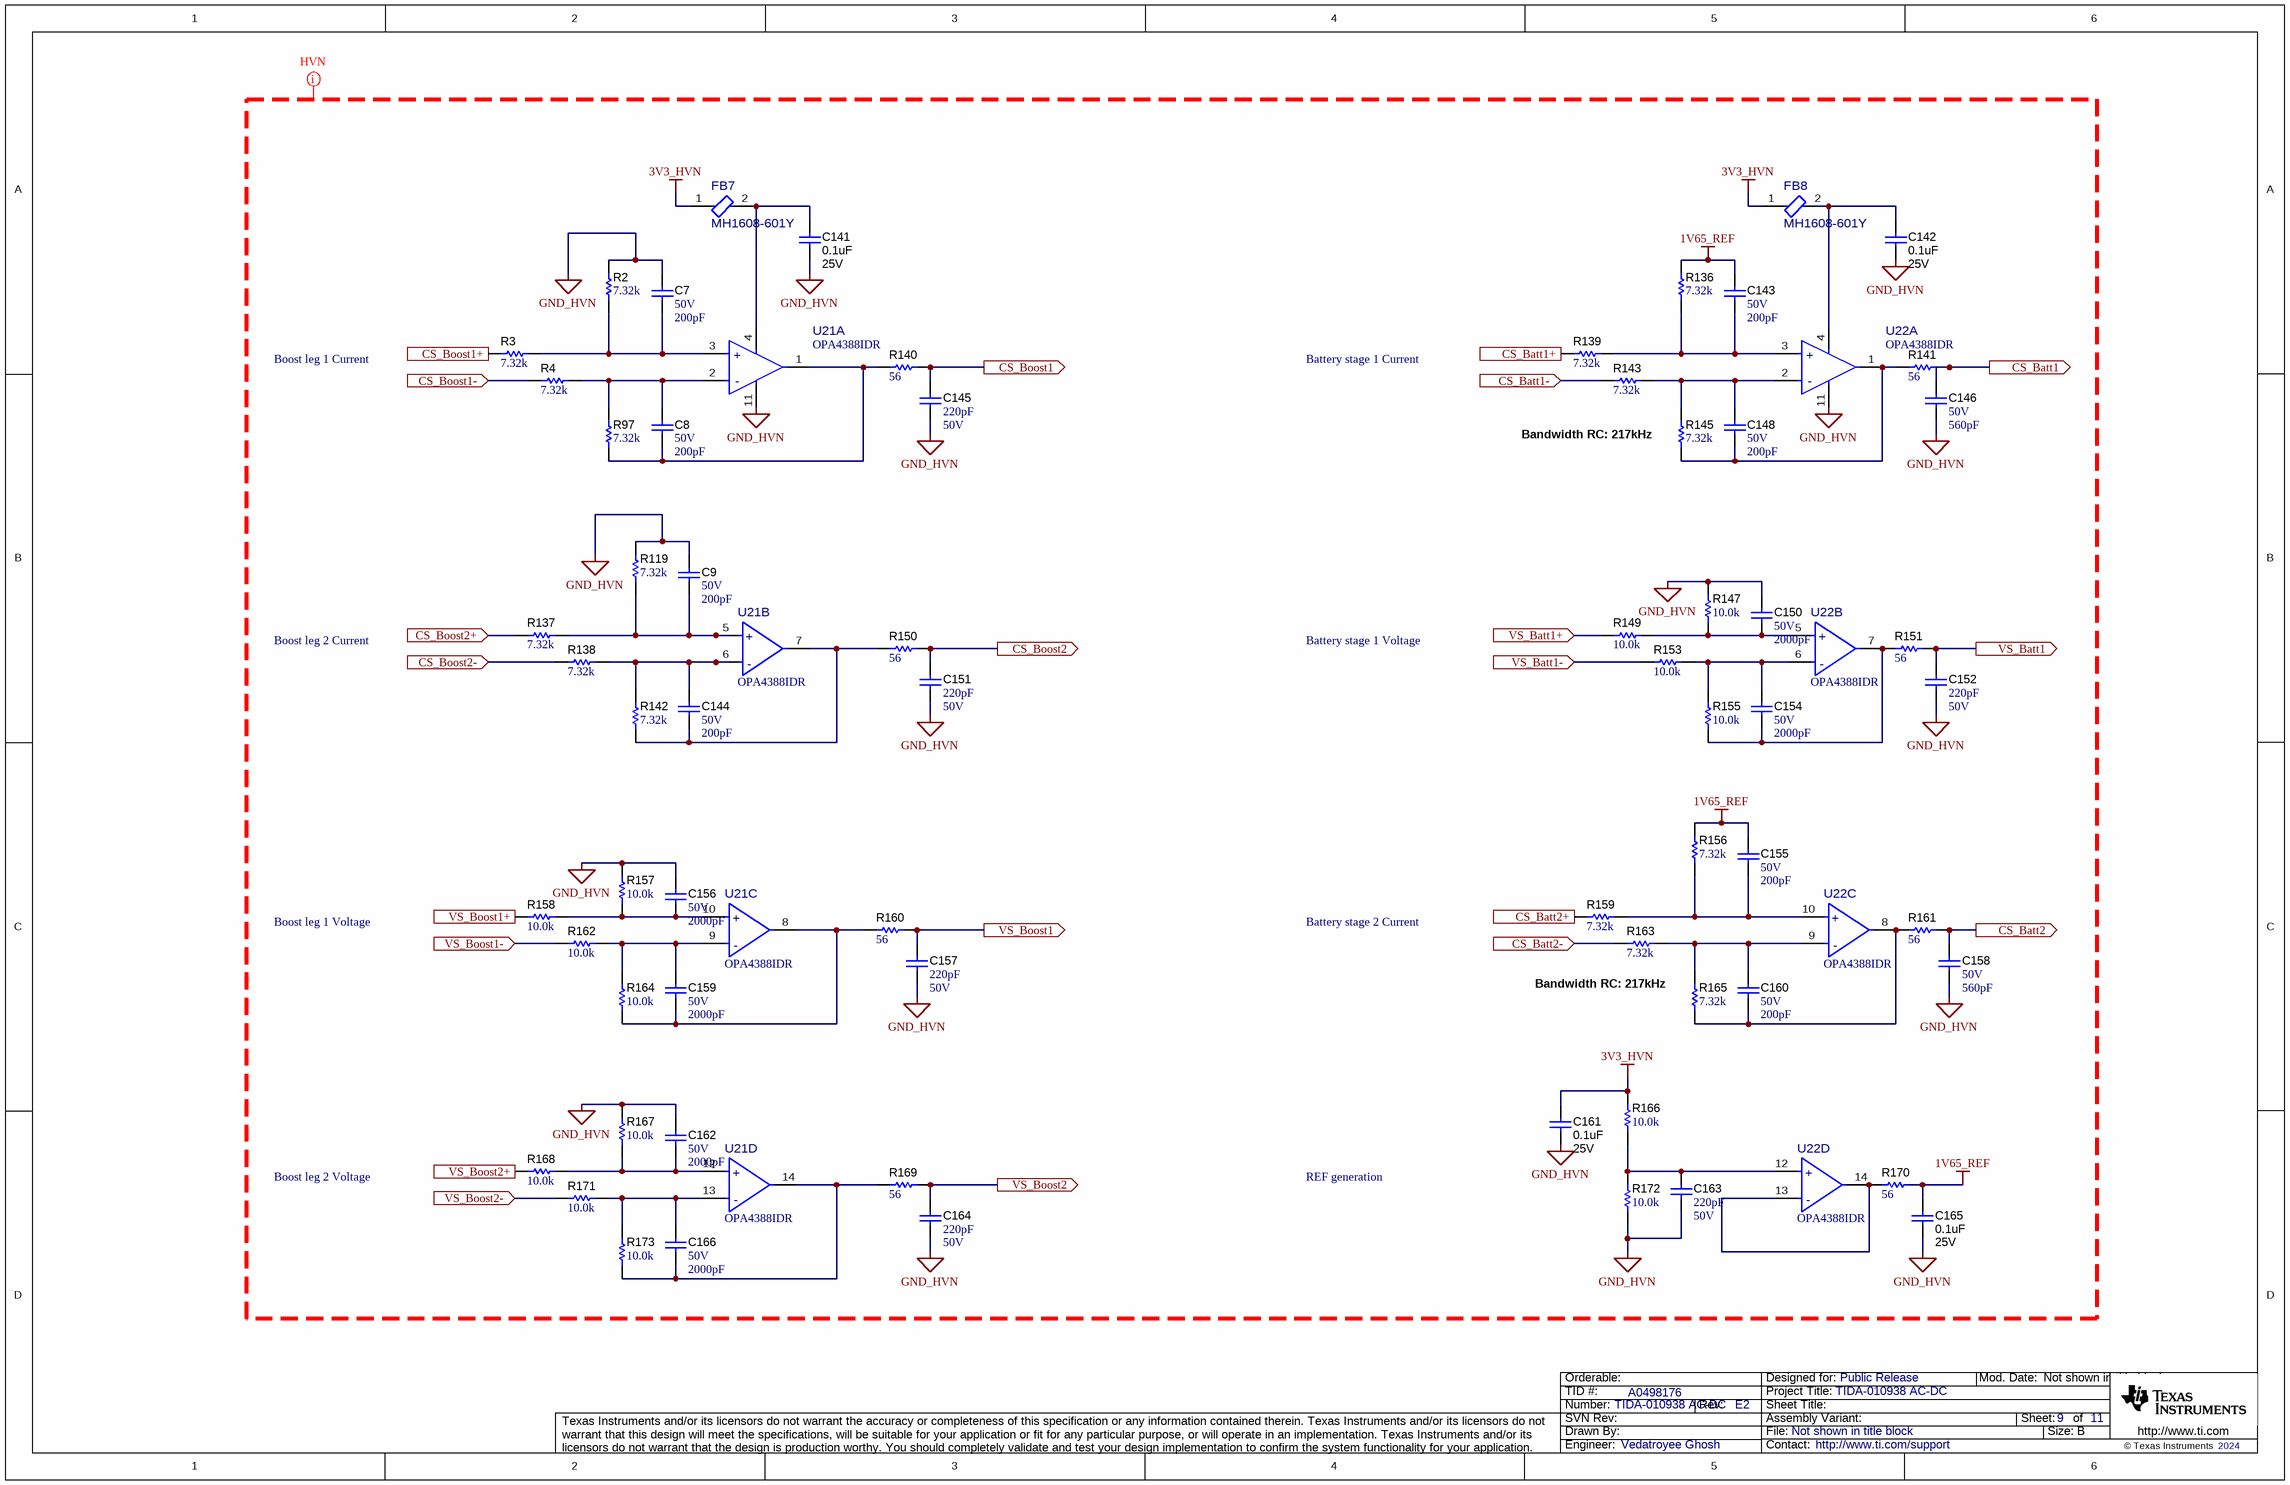
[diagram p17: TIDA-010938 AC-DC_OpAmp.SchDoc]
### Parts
C7  VDC_V: 50V  ValueDisplayed: 200pF  [0603]  (hidden comment: GRM1885C1H201JA01D)
C8  VDC_V: 50V  ValueDisplayed: 200pF  [0603]  (hidden comment: GRM1885C1H201JA01D)
C9  VDC_V: 50V  ValueDisplayed: 200pF  [0603]  (hidden comment: GRM1885C1H201JA01D)
C141  ValueDisplayed: 0.1uF  VDC_V: 25V  [0603]  (hidden comment: C0603X104K3RACTU)
C142  ValueDisplayed: 0.1uF  VDC_V: 25V  [0603]  (hidden comment: C0603X104K3RACTU)
C143  VDC_V: 50V  ValueDisplayed: 200pF  [0603]  (hidden comment: GRM1885C1H201JA01D)
C144  VDC_V: 50V  ValueDisplayed: 200pF  [0603]  (hidden comment: GRM1885C1H201JA01D)
C145  Cap_F: 220pF  VDC_V: 50V  [0603]  (hidden comment: GRM188R71H221KA01D)
C146  VDC_V: 50V  ValueDisplayed: 560pF  [0603]  (hidden comment: C0603C561J5GACTU)
C148  VDC_V: 50V  ValueDisplayed: 200pF  [0603]  (hidden comment: GRM1885C1H201JA01D)
C150  VDC_V: 50V  ValueDisplayed: 2000pF  [0603]  (hidden comment: GRM1885C1H202JA01D)
C151  Cap_F: 220pF  VDC_V: 50V  [0603]  (hidden comment: GRM188R71H221KA01D)
C152  Cap_F: 220pF  VDC_V: 50V  [0603]  (hidden comment: GRM188R71H221KA01D)
C154  VDC_V: 50V  ValueDisplayed: 2000pF  [0603]  (hidden comment: GRM1885C1H202JA01D)
C155  VDC_V: 50V  ValueDisplayed: 200pF  [0603]  (hidden comment: GRM1885C1H201JA01D)
C156  VDC_V: 50V  ValueDisplayed: 2000pF  [0603]  (hidden comment: GRM1885C1H202JA01D)
C157  Cap_F: 220pF  VDC_V: 50V  [0603]  (hidden comment: GRM188R71H221KA01D)
C158  VDC_V: 50V  ValueDisplayed: 560pF  [0603]  (hidden comment: C0603C561J5GACTU)
C159  VDC_V: 50V  ValueDisplayed: 2000pF  [0603]  (hidden comment: GRM1885C1H202JA01D)
C160  VDC_V: 50V  ValueDisplayed: 200pF  [0603]  (hidden comment: GRM1885C1H201JA01D)
C161  ValueDisplayed: 0.1uF  VDC_V: 25V  [0603]  (hidden comment: C0603X104K3RACTU)
C162  VDC_V: 50V  ValueDisplayed: 2000pF  [0603]  (hidden comment: GRM1885C1H202JA01D)
C163  Cap_F: 220pF  VDC_V: 50V  [0603]  (hidden comment: GRM188R71H221KA01D)
C164  Cap_F: 220pF  VDC_V: 50V  [0603]  (hidden comment: GRM188R71H221KA01D)
C165  ValueDisplayed: 0.1uF  VDC_V: 25V  [0603]  (hidden comment: C0603X104K3RACTU)
C166  VDC_V: 50V  ValueDisplayed: 2000pF  [0603]  (hidden comment: GRM1885C1H202JA01D)
FB7  MH1608-601Y  [FP-MH1608-601Y_0603-MFG]
FB8  MH1608-601Y  [FP-MH1608-601Y_0603-MFG]
R2  ValueDisplayed: 7.32k  [0603]  (hidden comment: RT0603BRD077K32L)
R3  ValueDisplayed: 7.32k  [0603]  (hidden comment: RT0603BRD077K32L)
R4  ValueDisplayed: 7.32k  [0603]  (hidden comment: RT0603BRD077K32L)
R97  ValueDisplayed: 7.32k  [0603]  (hidden comment: RT0603BRD077K32L)
R119  ValueDisplayed: 7.32k  [0603]  (hidden comment: RT0603BRD077K32L)
R136  ValueDisplayed: 7.32k  [0603]  (hidden comment: RT0603BRD077K32L)
R137  ValueDisplayed: 7.32k  [0603]  (hidden comment: RT0603BRD077K32L)
R138  ValueDisplayed: 7.32k  [0603]  (hidden comment: RT0603BRD077K32L)
R139  ValueDisplayed: 7.32k  [0603]  (hidden comment: RT0603BRD077K32L)
R140  ValueDisplayed: 56  [0603]  (hidden comment: RG1608P-560-B-T5)
R141  ValueDisplayed: 56  [0603]  (hidden comment: RG1608P-560-B-T5)
R142  ValueDisplayed: 7.32k  [0603]  (hidden comment: RT0603BRD077K32L)
R143  ValueDisplayed: 7.32k  [0603]  (hidden comment: RT0603BRD077K32L)
R145  ValueDisplayed: 7.32k  [0603]  (hidden comment: RT0603BRD077K32L)
R147  ValueDisplayed: 10.0k  [0603]  (hidden comment: RG1608P-103-B-T5)
R149  ValueDisplayed: 10.0k  [0603]  (hidden comment: RG1608P-103-B-T5)
R150  ValueDisplayed: 56  [0603]  (hidden comment: RG1608P-560-B-T5)
R151  ValueDisplayed: 56  [0603]  (hidden comment: RG1608P-560-B-T5)
R153  ValueDisplayed: 10.0k  [0603]  (hidden comment: RG1608P-103-B-T5)
R155  ValueDisplayed: 10.0k  [0603]  (hidden comment: RG1608P-103-B-T5)
R156  ValueDisplayed: 7.32k  [0603]  (hidden comment: RT0603BRD077K32L)
R157  ValueDisplayed: 10.0k  [0603]  (hidden comment: RG1608P-103-B-T5)
R158  ValueDisplayed: 10.0k  [0603]  (hidden comment: RG1608P-103-B-T5)
R159  ValueDisplayed: 7.32k  [0603]  (hidden comment: RT0603BRD077K32L)
R160  ValueDisplayed: 56  [0603]  (hidden comment: RG1608P-560-B-T5)
R161  ValueDisplayed: 56  [0603]  (hidden comment: RG1608P-560-B-T5)
R162  ValueDisplayed: 10.0k  [0603]  (hidden comment: RG1608P-103-B-T5)
R163  ValueDisplayed: 7.32k  [0603]  (hidden comment: RT0603BRD077K32L)
R164  ValueDisplayed: 10.0k  [0603]  (hidden comment: RG1608P-103-B-T5)
R165  ValueDisplayed: 7.32k  [0603]  (hidden comment: RT0603BRD077K32L)
R166  ValueDisplayed: 10.0k  [0603]  (hidden comment: RG1608P-103-B-T5)
R167  ValueDisplayed: 10.0k  [0603]  (hidden comment: RG1608P-103-B-T5)
R168  ValueDisplayed: 10.0k  [0603]  (hidden comment: RG1608P-103-B-T5)
R169  ValueDisplayed: 56  [0603]  (hidden comment: RG1608P-560-B-T5)
R170  ValueDisplayed: 56  [0603]  (hidden comment: RG1608P-560-B-T5)
R171  ValueDisplayed: 10.0k  [0603]  (hidden comment: RG1608P-103-B-T5)
R172  ValueDisplayed: 10.0k  [0603]  (hidden comment: RG1608P-103-B-T5)
R173  ValueDisplayed: 10.0k  [0603]  (hidden comment: RG1608P-103-B-T5)
U21  OPA4388IDR  [D0014A-MFG]  (parts A,B,C,D of 4)
U22  OPA4388IDR  [D0014A-MFG]  (parts A,B,C,D of 4)

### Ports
CS_Batt1 (out), CS_Batt1+ (in), CS_Batt1- (in), CS_Batt2 (out), CS_Batt2+ (in), CS_Batt2- (in), CS_Boost1 (out), CS_Boost1+ (in), CS_Boost1- (in), CS_Boost2 (out), CS_Boost2+ (in), CS_Boost2- (in), VS_Batt1 (out), VS_Batt1+ (in), VS_Batt1- (in), VS_Boost1 (out), VS_Boost1+ (in), VS_Boost1- (in), VS_Boost2 (out), VS_Boost2+ (in), VS_Boost2- (in)

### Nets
1V65_REF: C143.1 C155.1 C165.2 R136.2 R156.2 R170.2
3V3_HVN: C161.2 FB7.1 FB8.1 R166.1
GND_HVN: C7.1 C9.1 C141.1 C142.1 C145.1 C146.2 C150.2 C151.1 C152.1 C156.2 C157.1 C158.2 C161.1 C162.2 C163.1 C164.1 C165.1 R2.2 R119.2 R147.1 R157.1 R167.1 R172.2 U21.11(V-) U22.11(V-)  [project net DC Bus-]
CS_Batt1: C146.1 R141.2 ; port CS_Batt1
CS_Batt1+: R139.1 ; port CS_Batt1+
CS_Batt1-: R143.1 ; port CS_Batt1-
CS_Batt2: C158.1 R161.2 ; port CS_Batt2
CS_Batt2+: R159.1 ; port CS_Batt2+
CS_Batt2-: R163.1 ; port CS_Batt2-
CS_Boost1: C145.2 R140.2 ; port CS_Boost1
CS_Boost1+: R3.1 ; port CS_Boost1+
CS_Boost1-: R4.1 ; port CS_Boost1-
CS_Boost2: C151.2 R150.2 ; port CS_Boost2
CS_Boost2+: R137.1 ; port CS_Boost2+
CS_Boost2-: R138.1 ; port CS_Boost2-
VS_Batt1: C152.2 R151.2 ; port VS_Batt1
VS_Batt1+: R149.2 ; port VS_Batt1+
VS_Batt1-: R153.2 ; port VS_Batt1-
VS_Boost1: C157.2 R160.2 ; port VS_Boost1
VS_Boost1+: R158.2 ; port VS_Boost1+
VS_Boost1-: R162.2 ; port VS_Boost1-
VS_Boost2: C164.2 R169.2 ; port VS_Boost2
VS_Boost2+: R168.2 ; port VS_Boost2+
VS_Boost2-: R171.2 ; port VS_Boost2-
NetC7_2: C7.2 R2.1 R3.2 U21.3(+IN_A)
NetC8_1: C8.1 R4.2 R97.2 U21.2(-IN_A)
NetC8_2: C8.2 R97.1 R140.1 U21.1(OUT_A)
NetC9_2: C9.2 R119.1 R137.2 U21.5(+IN_B)
NetC141_2: C141.2 FB7.2 U21.4(V+)
NetC142_2: C142.2 FB8.2 U22.4(V+)
NetC143_2: C143.2 R136.1 R139.2 U22.3(+IN_A)
NetC144_1: C144.1 R138.2 R142.2 U21.6(-IN_B)
NetC144_2: C144.2 R142.1 R150.1 U21.7(OUT_B)
NetC148_1: C148.1 R143.2 R145.2 U22.2(-IN_A)
NetC148_2: C148.2 R141.1 R145.1 U22.1(OUT_A)
NetC150_1: C150.1 R147.2 R149.1 U22.5(+IN_B)
NetC154_1: C154.1 R153.1 R155.1 U22.6(-IN_B)
NetC154_2: C154.2 R151.1 R155.2 U22.7(OUT_B)
NetC155_2: C155.2 R156.1 R159.2 U22.10(+IN_C)
NetC156_1: C156.1 R157.2 R158.1 U21.10(+IN_C)
NetC159_1: C159.1 R162.1 R164.1 U21.9(-IN_C)
NetC159_2: C159.2 R160.1 R164.2 U21.8(OUT_C)
NetC160_1: C160.1 R163.2 R165.2 U22.9(-IN_C)
NetC160_2: C160.2 R161.1 R165.1 U22.8(OUT_C)
NetC162_1: C162.1 R167.2 R168.1 U21.12(+IN_D)
NetC163_2: C163.2 R166.2 R172.1 U22.12(+IN_D)
NetC166_1: C166.1 R171.1 R173.1 U21.13(-IN_D)
NetC166_2: C166.2 R169.1 R173.2 U21.14(OUT_D)
NetR170_1: R170.1 U22.13(-IN_D) U22.14(OUT_D)

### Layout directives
net class HVN: 1V65_REF, 3V3_HVN, GND_HVN

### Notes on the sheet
- Boost leg 1 Current
- Battery stage 1 Current
- Bandwidth RC: 217kHz
- Boost leg 2 Current
- Battery stage 1 Voltage
- Boost leg 1 Voltage
- Battery stage 2 Current
- Boost leg 2 Voltage
- REF generation

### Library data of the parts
C7-C9 C143 C144 C148 C155 C160 = CMP-0007194-4: CAP, CERM, 200 pF, 50 V, +/- 5%, C0G/NP0, 0603; Manufacturer: MuRata; TaMin_C: -55°C; Polarized: N; SizeAreaWB_mm2: 4.68; Value1: Unknown; U/M: EA; Value: 200pF; TaMax_C: 125°C; SizeZ_mm: 1; SizeX_mm: 1.6; SizeY_mm: 0.8; SizeArea_mm2: 1.28; AEC Category: Q200
C141 C142 C161 C165 = CMP-0006979-5: CAP, CERM, 0.1 uF, 25 V, +/- 10%, X7R, 0603; Manufacturer: Kemet; Polarized: N; Value: 0.1uF; U/M: EA; Cap_F: 100nF; Value1: Unknown; TaMin_C: -55°C; TaMax_C: 125°C; AEC Category: Q200; SizeArea_mm2: 1.28; SizeAreaWB_mm2: 4.68; SizeX_mm: 1.6; SizeY_mm: 0.8; SizeZ_mm: 1
C145 C151 C152 C157 C163 C164 = CMP-0007442-5: CAP, CERM, 220 pF, 50 V, +/- 10%, X7R, 0603; Manufacturer: MuRata; TaMin_C: -55°C; Polarized: N; SizeAreaWB_mm2: 4.68; Value1: Unknown; U/M: EA; Value: 220pF; TaMax_C: 125°C; SizeZ_mm: 1; SizeX_mm: 1.6; SizeY_mm: 0.8; SizeArea_mm2: 1.28; AEC Category: Q200
C146 C158 = CMP-0006953-4: CAP, CERM, 560 pF, 50 V, +/- 5%, C0G/NP0, 0603; Manufacturer: Kemet; TaMin_C: -55°C; Polarized: N; SizeAreaWB_mm2: 4.68; Value1: Unknown; U/M: EA; Value: 560pF; TaMax_C: 125°C; SizeZ_mm: 1; SizeX_mm: 1.6; SizeY_mm: 0.8; SizeArea_mm2: 1.28; AEC Category: Q200
C150 C154 C156 C159 C162 C166 = CMP-0007195-4: CAP, CERM, 2000 pF, 50 V, +/- 5%, C0G/NP0, 0603; Manufacturer: MuRata; TaMin_C: -55°C; Polarized: N; SizeAreaWB_mm2: 4.68; Value1: Unknown; U/M: EA; Value: 2000pF; TaMax_C: 125°C; SizeZ_mm: 1; SizeX_mm: 1.6; SizeY_mm: 0.8; SizeArea_mm2: 1.28; Cap_F: 2nF; AEC Category: Q200
FB7 FB8 = CMP-0037505-1: 600 Ohms @ 100 MHz 1 Power, Signal Line Ferrite Bead 0603 (1608 Metric) 1A 200mOhm; Manufacturer: Bourns; DCR_ohm: 0.2; SizeZ_mm: 1mm; AEC Qualified: No; Impedance At Frequency: 600Ω @ 100MHz; Test Frequency: 100MHz; Tolerance_%: 25%
R2-R4 R97 R119 R136-R139 R142 R143 R145 R156 R159 R163 R165 = CMP-0024479-2: RES, 7.32 k, 0.1%, 0.1 W, 0603; Manufacturer: Yageo America; Power_W: 100mW; TempCo: 25 ppm/C; Value_Code: 7k32; U/M: EA; Value: 7.32k; EIA_Code: E192; SizeX_mm: 1.6; SizeY_mm: 0.8; SizeZ_mm: 1; Value2: 0.1W; SizeArea_mm2: 1.28; VDC_V: 75V; AEC Category: Q200
R140 R141 R150 R151 R160 R161 R169 R170 = CMP-0023572-3: RES, 56, 0.1%, 0.1 W, 0603; Manufacturer: Susumu Co Ltd; Power_W: 100mW; TempCo: 25 ppm/C; Value_Code: 56R0; U/M: EA; Value: 56; SizeX_mm: 1.6; SizeY_mm: 0.8; SizeZ_mm: 1; Value2: 0.1W; SizeArea_mm2: 1.28; VDC_V: 75V; AEC Category: Q200
R147 R149 R153 R155 R157 R158 R162 R164 R166-R168 R171-R173 = CMP-0023404-3: RES, 10.0 k, 0.1%, 0.1 W, 0603; Manufacturer: Susumu Co Ltd; Power_W: 100mW; TempCo: 25 ppm/C; Value_Code: 10k0; U/M: EA; Value: 10.0k; EIA_Code: E192; Res_ohm: 10k; SizeX_mm: 1.6; SizeY_mm: 0.8; SizeZ_mm: 1; Value2: 0.1W; SizeArea_mm2: 1.28; VDC_V: 75V; AEC Category: Q200
U21 U22 = CMP-0097120-1: Op Amp Quad Zero Drift Amplifier R-R I/O ±2.75V/5.5V 14-Pin SOIC T/R; Manufacturer: Texas Instruments; Standoff Height: 0.1mm; SizeZ_mm: 1.75mm; Number Of Channels: 4; Max Dual Supply Voltage: 2.75V; Input Bias Current: 0.00003uA; TaMin_C: -55°C; TaMax_C: +150°C; Input Offset Voltage: 0.00225mV; Min Dual Supply Voltage: 1.25V; Output Current Per Channel: 60mA; Response Time: 2us; Gain Bandwidth: 10MHz; Max Supply Voltage: 5.5V; Voltage Gain: 148dB; AEC Qualified: No; Nominal Supply Current: 1.7-1.9mA; Min Supply Voltage: 2.5V

## Sheet TIDA-010938 AC-DC_Hardware.SchDoc
size 431 x 279 mm; Date: Not shown in title block; ApprovedBy: Not shown in title block; CheckedBy: Not shown in title block; Author: Not shown in title block; CompanyName: Not shown in title block; Engineer: Not shown in title block; Organization: Not shown in title block; Address1: Not shown in title block; Address2: Not shown in title block; Address3: Not shown in title block; Address4: Not shown in title block; DocumentNumber: 11; Revision: Use project parameter SCH_Rev; SheetNumber: 11; SheetTotal: 11; PageSetup: Record=PageOptions¦CenterHorizontal=True¦CenterVertical=True¦PrintScale=1.00¦XCorrection=1.00¦YCorrection=1.00¦PrintKind=0¦BorderSize=5000000¦LeftOffset=0¦BottomOffset=0¦Orientation=2¦PaperLength=1000¦PaperWidth=1000¦Scale=100¦PaperSource=15¦PrintQuality=600¦MediaType=1¦DitherType=10¦PaperKind=Letter¦PrintScaleMode=1

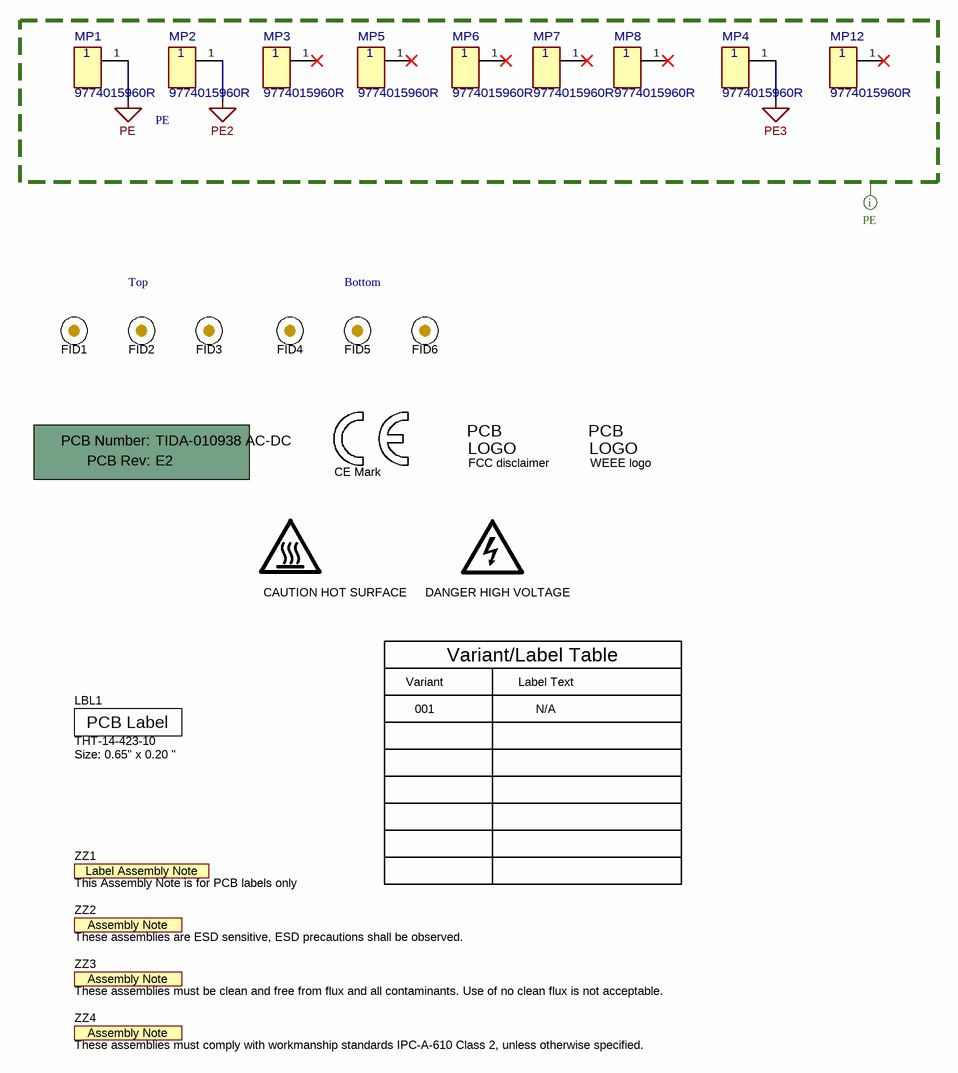
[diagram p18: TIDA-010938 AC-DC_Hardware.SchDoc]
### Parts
!PCB1  Printed Circuit Board  (value not drawn)  (mechanical)
FID1  Fiducial  [Fiducial10-20]  (value not drawn)
FID2  Fiducial  [Fiducial10-20]  (value not drawn)
FID3  Fiducial  [Fiducial10-20]  (value not drawn)
FID4  Fiducial  [Fiducial10-20]  (value not drawn)
FID5  Fiducial  [Fiducial10-20]  (value not drawn)
FID6  Fiducial  [Fiducial10-20]  (value not drawn)
LBL1  THT-14-423-10  Note: Size: 0.65" x 0.20 "  [Label_650x200]
LOGO1  CAUTION HOT SURFACE  [IEC_HotSurface_Small]  (no BOM)
LOGO2  DANGER HIGH VOLTAGE  [IEC_HighVoltage_Small]  (no BOM)
Logo3  CE Mark  [CE_Mark_5mm]  (no BOM)
Logo5  FCC disclaimer  [FCC_disclaimer]  (no BOM)
Logo6  WEEE logo  [WEEE_Minimum]  (no BOM)
MP1  9774015960R  [FP-9774015960R_ROUND_SPACER_6MM0-MFG]
MP2  9774015960R  [FP-9774015960R_ROUND_SPACER_6MM0-MFG]
MP3  9774015960R  [FP-9774015960R_ROUND_SPACER_6MM0-MFG]
MP4  9774015960R  [FP-9774015960R_ROUND_SPACER_6MM0-MFG]
MP5  9774015960R  [FP-9774015960R_ROUND_SPACER_6MM0-MFG]
MP6  9774015960R  [FP-9774015960R_ROUND_SPACER_6MM0-MFG]
MP7  9774015960R  [FP-9774015960R_ROUND_SPACER_6MM0-MFG]
MP8  9774015960R  [FP-9774015960R_ROUND_SPACER_6MM0-MFG]
MP12  9774015960R  [FP-9774015960R_ROUND_SPACER_6MM0-MFG]
ZZ1  This Assembly Note is for PCB labels only  [AssemblyNoteLabel]  (no BOM)
ZZ2  These assemblies are ESD sensitive, ESD precautions shall be observed.  [AssemblyNote]  (no BOM)
ZZ3  These assemblies must be clean and free from flux and all contaminants. Use of no clean flux is not acceptable.  [AssemblyNote]  (no BOM)
ZZ4  These assemblies must comply with workmanship standards IPC-A-610 Class 2, unless otherwise specified.  [AssemblyNote]  (no BOM)

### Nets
PE: MP1.1
PE2: MP2.1
PE3: MP4.1

Not connected (* = marked no-connect by the designer): MP3 1*; MP5 1*; MP6 1*; MP7 1*; MP8 1*; MP12 1*

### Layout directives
net class PE: PE, PE2, PE3

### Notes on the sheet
- PE
- (near FID2) Top
- Bottom
- Variant
- Variant/Label Table
- Label Text
- 001
- N/A

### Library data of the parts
!PCB1 = CMP-0003618-2: Manufacturer: Any; PartNumber: TIDA-010938 AC-DC
FID1-FID6 = CMP-0077181-1: Fiducial mark.  There is nothing to buy or mount.
LBL1 = CMP-0003625-1: Thermal Transfer Printable Labels, 0.650" W x 0.200" H - 10,000 per roll; Manufacturer: Brady; CompType: Label
LOGO1 = CMP-0074837-1: IEC 61010-1 Hot Surface Warning; SymbolCreator: a0412235; Lib Reference: IEC_HotSurface
LOGO2 = CMP-0074835-1: IEC 61010-1 High Voltage Warning; SymbolCreator: a0412235; Lib Reference: IEC_HighVoltage
Logo3 = CMP-0074844-1: SymbolCreator: a0412235
Logo5 = CMP-0074847-1: FCC_disclaimer; Library Reference: Logo
Logo6 = CMP-0074769-1
MP1-MP8 MP12 = CMP-0040203-1: Round Spacer Unthreaded Steel 0.059" (1.50mm); Manufacturer: Wurth Electronics; AEC Qualified: No; Is Female: yes; SizeZ_mm: 1.6mm
ZZ1 = CMP-0003616-3
ZZ2 = CMP-0077236-1
ZZ3 = CMP-0077237-1
ZZ4 = CMP-0077238-1

## Sheet TIDA-010938 AC-DC_Aux Power Supply.SchDoc
size 431 x 279 mm; Date: Not shown in title block; ApprovedBy: Not shown in title block; CheckedBy: Not shown in title block; Author: Not shown in title block; CompanyName: Not shown in title block; Engineer: Not shown in title block; Organization: Not shown in title block; Address1: Not shown in title block; Address2: Not shown in title block; Address3: Not shown in title block; Address4: Not shown in title block; DocumentNumber: 4; Revision: Use project parameter SCH_Rev; SheetNumber: 5; SheetTotal: 11; PageSetup: Record=PageOptions¦CenterHorizontal=True¦CenterVertical=True¦PrintScale=1.00¦XCorrection=1.00¦YCorrection=1.00¦PrintKind=0¦BorderSize=5000000¦LeftOffset=0¦BottomOffset=0¦Orientation=2¦PaperLength=1000¦PaperWidth=1000¦Scale=100¦PaperSource=15¦PrintQuality=600¦MediaType=1¦DitherType=10¦PaperKind=Letter¦PrintScaleMode=1

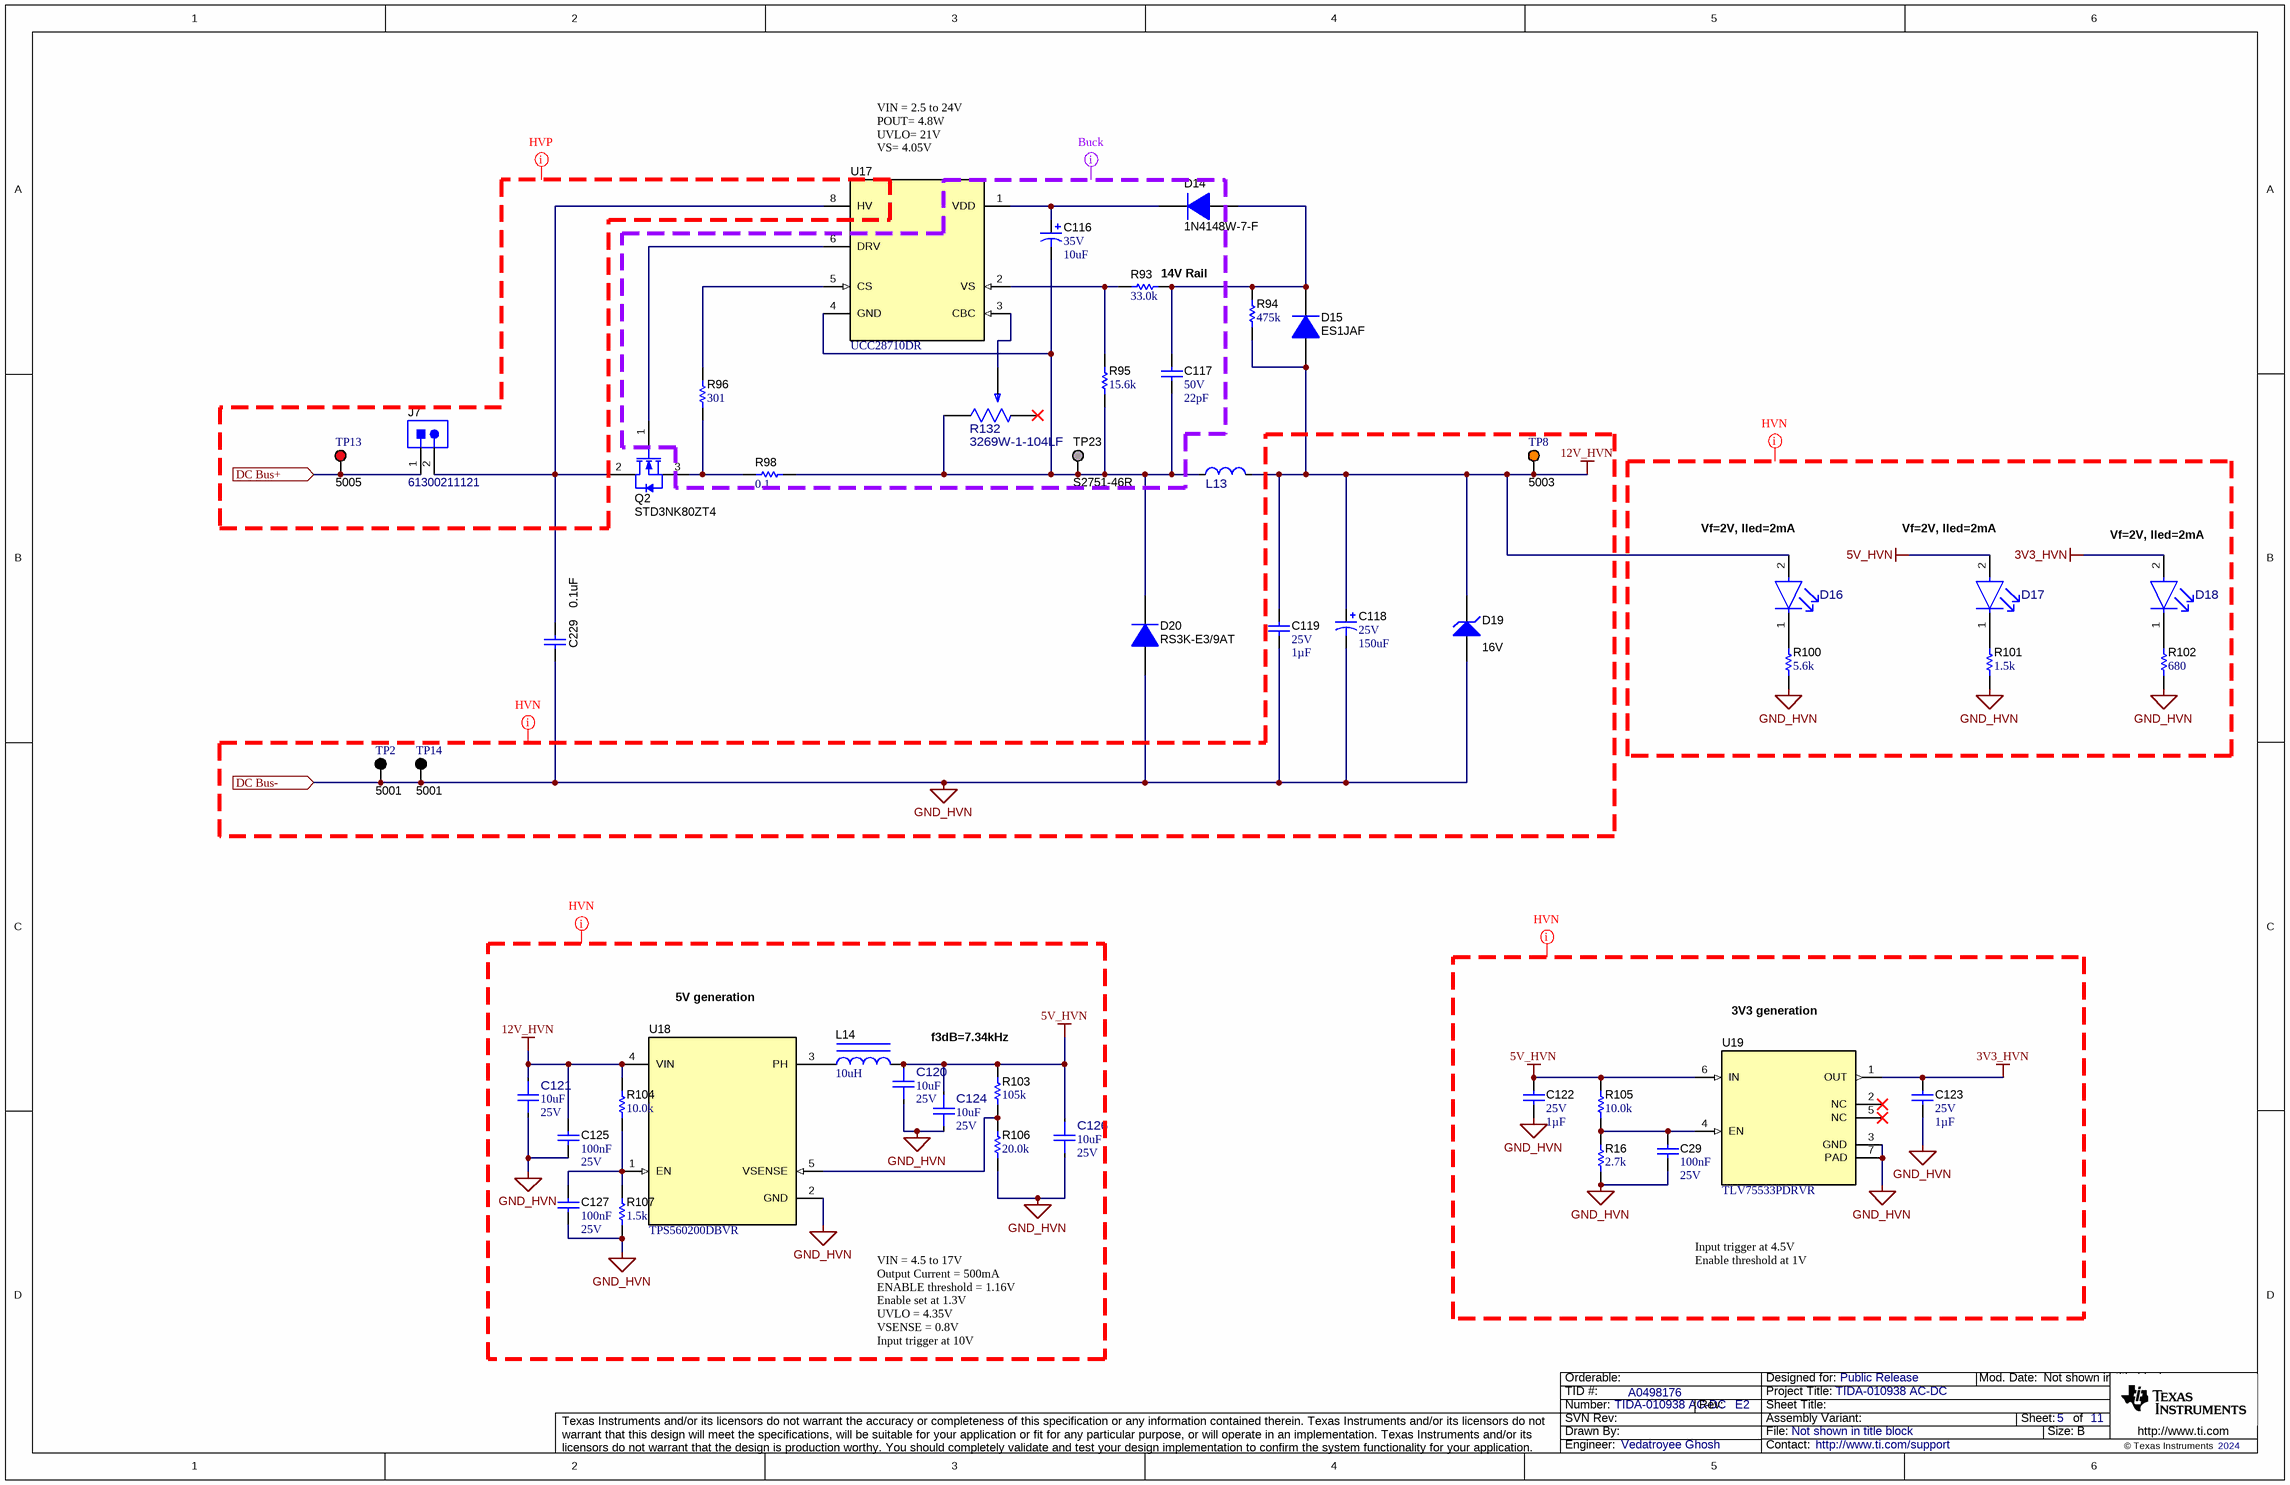
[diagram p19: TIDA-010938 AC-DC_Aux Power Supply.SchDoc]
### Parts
C29  Cap_F: 100nF  VDC_V: 25V  [0603]  (hidden comment: 06033C104JAT2A)
C116  VDC_V: 35V  ValueDisplayed: 10uF  [CAPPR2-5x11]  (hidden comment: UVR1V100MDD1TA)
C117  VDC_V: 50V  ValueDisplayed: 22pF  [0603]  (hidden comment: 06035A220JAT2A)
C118  VDC_V: 25V  ValueDisplayed: 150uF  [FR_630X1120]  (hidden comment: EEU-FR1E151B)
C119  VDC_V: 25V  ValueDisplayed: 1µF  [0603]  (hidden comment: TMK107BJ105KA-T)
C120  ValueDisplayed: 10uF  VDC_V: 25V  [FP-ZRB18AR61E106ME01L_0603-MFG]  (hidden comment: ZRB18AR61E106ME01L)
C121  ValueDisplayed: 10uF  VDC_V: 25V  [FP-ZRB18AR61E106ME01L_0603-MFG]  (hidden comment: ZRB18AR61E106ME01L)
C122  VDC_V: 25V  ValueDisplayed: 1µF  [0603]  (hidden comment: TMK107BJ105KA-T)
C123  VDC_V: 25V  ValueDisplayed: 1µF  [0603]  (hidden comment: TMK107BJ105KA-T)
C124  ValueDisplayed: 10uF  VDC_V: 25V  [FP-ZRB18AR61E106ME01L_0603-MFG]  (hidden comment: ZRB18AR61E106ME01L)
C125  Cap_F: 100nF  VDC_V: 25V  [0603]  (hidden comment: 06033C104JAT2A)
C126  ValueDisplayed: 10uF  VDC_V: 25V  [FP-ZRB18AR61E106ME01L_0603-MFG]  (hidden comment: ZRB18AR61E106ME01L)
C127  Cap_F: 100nF  VDC_V: 25V  [0603]  (hidden comment: 06033C104JAT2A)
C229  ValueDisplayed: 0.1uF  [1812_254]  (hidden comment: C1812W104KDRACTU)
D14  1N4148W-7-F  [SOD-123]
D15  ES1JAF  [SMAF]
D16  KG DELLS1.22-JGKH-24  [FP-KG DELLS1.22-JGKH-24_0603-MFG]  (value not drawn)
D17  KG DELLS1.22-JGKH-24  [FP-KG DELLS1.22-JGKH-24_0603-MFG]  (value not drawn)
D18  KG DELLS1.22-JGKH-24  [FP-KG DELLS1.22-JGKH-24_0603-MFG]  (value not drawn)
D19  value 16V  [SOD-123]  (hidden comment: BZT52C16-7-F)
D20  RS3K-E3/9AT  [SMC]
J7  61300211121  [WURTH_61300211121]
L13  MS0311  [FP-MS0311_SMT_IND_12MM0_12MM0-MFG]  (value not drawn)
L14  ValueDisplayed: 10uH  [SRN3015]  (hidden comment: SRN3015-100M)
Q2  STD3NK80ZT4  [DPAK]
R16  ValueDisplayed: 2.7k  [0603]  (hidden comment: CRCW06032K70JNEA)
R93  ValueDisplayed: 33.0k  [0603]  (hidden comment: RG1608P-333-B-T5)
R94  ValueDisplayed: 475k  [1206]  (hidden comment: CRCW1206475KFKEA)
R95  ValueDisplayed: 15.6k  [0603]  (hidden comment: RT0603DRE0715K6L)
R96  ValueDisplayed: 301  [0603]  (hidden comment: RT0603DRE07301RL)
R98  ValueDisplayed: 0.1  [0805_HV]  (hidden comment: ERJ-6RSFR10V)
R100  ValueDisplayed: 5.6k  [0603]  (hidden comment: RC0603JR-075K6L)
R101  ValueDisplayed: 1.5k  [0603]  (hidden comment: ERJ-3GEYJ152V)
R102  ValueDisplayed: 680  [0603]  (hidden comment: RC0603JR-07680RL)
R103  ValueDisplayed: 105k  [0603]  (hidden comment: RT0603BRD07105KL)
R104  ValueDisplayed: 10.0k  [0603]  (hidden comment: RG1608P-103-B-T5)
R105  ValueDisplayed: 10.0k  [0603]  (hidden comment: RG1608P-103-B-T5)
R106  ValueDisplayed: 20.0k  [0603]  (hidden comment: RT0603DRE0720KL)
R107  ValueDisplayed: 1.5k  [0603]  (hidden comment: CRCW06031K50JNEA)
R132  3269W-1-104LF  [FP-3269W-1-104LF_SMD-MFG]
TP2  5001  [Keystone5001]
TP8  5003  [Keystone5003]
TP13  5005  [Keystone5005]
TP14  5001  [Keystone5001]
TP23  S2751-46R  [Harwin_S2751-46R]  (no BOM)
U17  UCC28710DR  [D0007A_N]
U18  TPS560200DBVR  [DBV0005A_N]
U19  TLV75533PDRVR  [DRV0006A]

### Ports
DC Bus+ (in), DC Bus- (in)

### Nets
3V3_HVN: C123.2 D18.2(ANODE) U19.1(OUT)
5V_HVN: C120.1 C122.2 C124.1 C126.1 D17.2(ANODE) L14.2 R103.1 R105.1 U19.6(IN)
12V_HVN: C118.1(+) C119.1 C121.1 C125.2 D15.2(A) D16.2(ANODE) D19.1(K) L13.2 R94.2 R104.1 TP8.1 U18.4(VIN)
GND_HVN: C29.1 C118.2(-) C119.2 C120.2 C121.2 C122.1 C123.1 C124.2 C125.1 C126.2 C127.1 C229.2 D19.2(A) D20.2(A) R16.1 R100.2 R101.1 R102.1 R106.2 R107.1 TP2.1 TP14.1 U18.2(GND) U19.3(GND) U19.7(PAD) ; port DC Bus-  [project net DC Bus-]
DC Bus+: J7.1 TP13.1 ; port DC Bus+
NetC29_2: C29.2 R16.2 R105.2 U19.4(EN)
NetC116_1: C116.1(+) D14.1(K) U17.1(VDD)
NetC116_2: C116.2(-) C117.2 D20.1(K) L13.1 R95.1 R98.2 R132.1(CCW) TP23.1 U17.4(GND)
NetC117_1: C117.1 D14.2(A) D15.1(K) R93.2 R94.1
NetC127_2: C127.2 R104.2 R107.2 U18.1(EN)
NetC229_1: C229.1 J7.2 Q2.2(D) U17.8(HV)
NetD16_1: D16.1(CATHODE) R100.1
NetD17_1: D17.1(CATHODE) R101.2
NetD18_1: D18.1(CATHODE) R102.2
NetL14_1: L14.1 U18.3(PH)
NetQ2_1: Q2.1(G) U17.6(DRV)
NetQ2_3: Q2.3(S) R96.2 R98.1
NetR93_1: R93.1 R95.2 U17.2(VS)
NetR96_1: R96.1 U17.5(CS)
NetR103_2: R103.2 R106.1 U18.5(VSENSE)
NetR132_2: R132.2(WIPER) U17.3(CBC)

Not connected (* = marked no-connect by the designer): R132 3(CW)*; U19 2(NC)* 5(NC)*

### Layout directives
net class HVN: 3V3_HVN, 5V_HVN, 12V_HVN, GND_HVN
net class Buck: (no net found under the mark)
net class HVP: (no net found under the mark)

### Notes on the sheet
- VIN = 2.5 to 24V
  POUT= 4.8W
  UVLO= 21V
  VS= 4.05V
- (near R93) 14V Rail
- (near D16) Vf=2V, Iled=2mA
- (near D17) Vf=2V, Iled=2mA
- (near D18) Vf=2V, Iled=2mA
- 5V generation
- f3dB=7.34kHz
- 3V3 generation
- Input trigger at 4.5V
  Enable threshold at 1V
- VIN = 4.5 to 17V
  Output Current = 500mA
  ENABLE threshold = 1.16V
  Enable set at 1.3V
  UVLO = 4.35V
  VSENSE = 0.8V
  Input trigger at 10V

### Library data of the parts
C29 C125 C127 = CMP-0006752-5: CAP, CERM, 0.1 uF, 25 V, +/- 5%, X7R, 0603; Manufacturer: AVX; TaMin_C: -55°C; ESR_ohm: 0.05; Polarized: N; SizeAreaWB_mm2: 4.68; Value1: 0.05 ohm; U/M: EA; Value: 0.1uF; TaMax_C: 125°C; SizeZ_mm: 1; SizeX_mm: 1.6; SizeY_mm: 0.8; SizeArea_mm2: 1.28; AEC Category: Q200
C116 = CMP-0010555-2: CAP, AL, 10 uF, 35 V, +/- 20%, TH; Manufacturer: Nichicon; TaMin_C: -40°C; Polarized: Y; SizeAreaWB_mm2: 49; Value1: Unknown; U/M: EA; Value: 10uF; TaMax_C: 85°C; SizeZ_mm: 11; SizeX_mm: 5; Cap_Case: 5x11; SizeArea_mm2: 25; CompType: Capacitor; AEC Qualified: N; Cap_F: 10µF; AEC Category: Q200
C117 = CMP-0006775-4: CAP, CERM, 22 pF, 50 V, +/- 5%, C0G/NP0, 0603; Manufacturer: AVX; TaMin_C: -55°C; ESR_ohm: 2.59d; Polarized: N; SizeAreaWB_mm2: 4.68; Value1: 0.259 ohm; U/M: EA; Value: 22pF; TaMax_C: 125°C; SizeZ_mm: 1; SizeX_mm: 1.6; SizeY_mm: 0.8; SizeArea_mm2: 1.28; AEC Category: Q200
C118 = CMP-0010348-1: CAP, AL, 150 uF, 25 V, +/- 20%, TH; Manufacturer: Panasonic; TaMin_C: -40°C; Polarized: Y; SizeAreaWB_mm2: 68.89; Value1: Unknown; U/M: EA; Value: 150uF; TaMax_C: 105°C; SizeZ_mm: 11.2; SizeX_mm: 6.3; Cap_Case: 6.3x11.2mm; SizeArea_mm2: 39.69; CompType: Capacitor; AEC Qualified: N; Cap_F: 150µF; IRMS_A: 4.55dA; AEC Category: Q200
C119 C122 C123 = CMP-0086152-1: CAP, CERM, 1 µF, 25 V,+/- 10%, X5R, 0603; Manufacturer: Taiyo Yuden; SizeAreaWB_mm2: 4.68; SizeZ_mm: 1; U/M: EA; Green_REACh: Passed; Value: 1uF; AEC Qualified: N; TaMax_C: 85°C; Green_Lifecycle: Active; AEC Category: Q200; SizeArea_mm2: 1.28; TaMin_C: -55°C; SizeY_mm: 0.8; SizeX_mm: 1.6
C120 C121 C124 C126 = CMP-0094458-1: 10µF ±20% 25V Ceramic Capacitor X5R 0603 (1608 Metric); Manufacturer: Murata Electronics; SizeZ_mm: 1.2mm; AEC Qualified: No
C229 = CMP-0009326-2: CAP, CERM, 0.1 uF, 1000 V, +/- 10%, X7R, 1812; Manufacturer: Kemet; Polarized: N; Value: 0.1uF; U/M: EA; Cap_F: 100nF; Value1: Unknown; VDC_V: 1kV; Value2: 1000V; TaMin_C: -55°C; TaMax_C: 125°C; Cap_Case: 1812; AEC Category: Q200; SizeArea_mm2: 14.4; SizeAreaWB_mm2: 23.1; SizeX_mm: 4.5; SizeY_mm: 3.2; SizeZ_mm: 2.54
D14 = CMP-0029001-2: Diode, Ultrafast, 100 V, 0.15 A, SOD-123; Manufacturer: Diodes Inc.; SizeX_mm: 3.85; Value2: 1.25V; Green_REACh: Passed; TJmax_C: 150°C; AEC Category: Q101; SizeAreaWB_mm2: 13.095; Value: 100V; Green_Lifecycle: Active; SizeY_mm: 1.7; Value1: 0.15A; SizeArea_mm2: 6.545; Io_A: 150mA; SizeZ_mm: 1.35
D15 = CMP-0029162-2: Diode, Ultrafast, 600 V, 1 A, AEC-Q101, SMAF; Manufacturer: Fairchild Semiconductor; TJmax_C: 150°C; Green_Lifecycle: Not Set; Green_REACh: Incomplete; Value: 600V; SizeY_mm: 2.5; Io_A: 1A; AEC Category: Q101; SizeArea_mm2: 11.75; SizeX_mm: 4.7; AEC Qualified: Y; SizeZ_mm: 1; SizeAreaWB_mm2: 19.95; Value2: 1.7V
D16-D18 = CMP-0093310-1: Standard LEDs - SMD Green TOPLED E 1608; Manufacturer: Osram Opto; AEC Grade: Grade 2; LambdaP: 572nm; SizeZ_mm: 0.7mm; LuminousFlux_PhiV: 0.016-0.0295lm; Luminous Intensity: 4.5-9.7mcd; LambdaD: 570nm; Tjmax_C: 125°C; Angle: 120°; Led Orientation: Top View; Forward Current: 2mA; Vf_V: 1.8V; AEC Qualified: Yes; Vr_V: 12V
D19 = CMP-0005769-4: Diode, Zener, 16 V, 500 mW, AEC-Q101, SOD-123; Manufacturer: Diodes Inc.; SizeZ_mm: 1.35; AEC Qualified: Y; SizeX_mm: 3.85; AEC Category: Q101; Power_W: 500mW; SizeY_mm: 1.7; Value1: 0.5W; SizeAreaWB_mm2: 13.095; SizeArea_mm2: 6.545; RJA_CperW: 338
D20 = CMP-0076883-2: Diode, Switching, 800 V, 3 A, SMC; Manufacturer: Vishay-Semiconductor; Value1: 3A; SizeAreaWB_mm2: 83.2686; SizeZ_mm: 2.6; AEC Category: Q101; SizeX_mm: 8.13; TJmax_C: 150°C; Value2: 1.3V; Vr_V: 800V; SizeArea_mm2: 50.5686; RJC_CperW: 50.0; Green_REACh: Incomplete; SizeY_mm: 6.22; Value: 800V; Green_Lifecycle: Not Set
J7 = CMP-0054794-2: Header, 2.54 mm, 2x1, Gold, TH; Manufacturer: Wurth Elektronik; Green_Lifecycle: Active; Green_REACh: Passed; Cert_UL: Y; Gender: Male; Pitch_mm: 2.54; Row_Count: 1; Shrouded: N
L13 = CMP-0123259-1: Shielded SMD Power Inductor 220uH 2A 240mOhm 12.0x12.0x10.0mm SMT; Manufacturer: Bourns; AEC Qualified: No; DCR_ohm: 0.24; Ind_H: 220µH; Isat: 3A; Material: Ferrite; SizeZ_mm: 10.3mm; Shrouded: true; Test Frequency: 1kHz; Tolerance_%: 10%
L14 = CMP-0056744-1: Inductor, Drum Core, Ferrite, 10 uH, 0.88 A, 0.276 ohm, SMD; Manufacturer: Bourns; Isat: 0.88A @ 30% inductance drop; Irms: 1A @ 40C rise; Green_Lifecycle: Active; SizeAreaWB_mm2: 16; DCR_ohm: 2.76d; Green_REACh: Passed; Value: 10uH; Imax_A: 8.8dA; SizeZ_mm: 1.5; SizeX_mm: 3; Value2: 0.88A; SizeArea_mm2: 9; Ind_H: 10µH; AEC Category: Q200
Q2 = CMP-0001278-3: MOSFET, N-CH, 800 V, 2.5 A, DPAK; Manufacturer: STMicroelectronics; Alternate Manufacturer: None; SizeY_mm: 6.54; SizeZ_mm: 2.29; VdsMax_V: 800V; SizeX_mm: 9.91; AEC Qualified: N; SizeArea_mm2: 64.8114; IdsMax_A: 2.5A; Value: 800V; SizeAreaWB_mm2: 101.7114; Value2: 19 nC; QgTyp_nC: 19; ChMode: Enhancement; Vgs_V: 30V; AEC Category: Q101
R16 = CMP-0025771-4: RES, 2.7 k, 5%, 0.1 W, AEC-Q200 Grade 0, 0603; Manufacturer: Vishay-Dale; Power_W: 100mW; TempCo: 200 ppm/C; Value_Code: 2k70; Value: 2.7k; EIA_Code: E24; SizeX_mm: 1.6; SizeY_mm: 0.8; SizeZ_mm: 1; Value2: 0.1W; SizeArea_mm2: 1.28; AEC Qualified: Y; VDC_V: 75V; AEC Category: Q200; AEC Grade: 0
R93 = CMP-0023520-3: RES, 33.0 k, 0.1%, 0.1 W, 0603; Manufacturer: Susumu Co Ltd; Power_W: 100mW; TempCo: 25 ppm/C; Value_Code: 33k0; U/M: EA; Value: 33.0k; Res_ohm: 33k; SizeX_mm: 1.6; SizeY_mm: 0.8; SizeZ_mm: 1; Value2: 0.1W; SizeArea_mm2: 1.28; VDC_V: 75V; AEC Category: Q200
R94 = CMP-0017008-3: RES, 475 k, 1%, 0.25 W, AEC-Q200 Grade 0, 1206; Manufacturer: Vishay-Dale; Power_W: 250mW; TempCo: 100 ppm/C; Value: 475k; EIA_Code: E96; SizeX_mm: 3.2; SizeY_mm: 1.6; SizeZ_mm: 1.35; Value2: 0.25W; SizeArea_mm2: 5.12; AEC Qualified: Y; VDC_V: 200V; AEC Category: Q200; AEC Grade: 0
R95 = CMP-0024711-2: RES, 15.6 k, 0.5%, 0.1 W, 0603; Manufacturer: Yageo America; Power_W: 100mW; TempCo: 50 ppm/C; Value_Code: 15k6; U/M: EA; Value: 15.6k; EIA_Code: E192; SizeX_mm: 1.6; SizeY_mm: 0.8; SizeZ_mm: 1; Value2: 0.1W; SizeArea_mm2: 1.28; VDC_V: 75V; AEC Category: Q200
R96 = CMP-0025116-2: RES, 301, 0.5%, 0.1 W, 0603; Manufacturer: Yageo America; Power_W: 100mW; TempCo: 50 ppm/C; Value_Code: 301R; U/M: EA; Value: 301; EIA_Code: E192; SizeX_mm: 1.6; SizeY_mm: 0.8; SizeZ_mm: 1; Value2: 0.1W; SizeArea_mm2: 1.28; VDC_V: 75V; AEC Category: Q200
R98 = CMP-0021846-2: RES, 0.1, 1%, 0.125 W, 0805; Manufacturer: Panasonic; Power_W: 125mW; TempCo: 250 ppm/C; Value_Code: R100; U/M: EA; Value: 0.1; EIA_Code: E96; Res_ohm: 1d; SizeX_mm: 2; SizeY_mm: 1.25; SizeZ_mm: 1.45; Value2: 0.125W; SizeArea_mm2: 2.5; AEC Category: Q200
R100 = CMP-0025933-5: RES, 5.6 k, 5%, 0.1 W, 0603; Manufacturer: Yageo; Power_W: 100mW; TempCo: 100 ppm/C; Value_Code: 5k60; Value: 5.6k; EIA_Code: E24; SizeX_mm: 1.6; SizeY_mm: 0.8; SizeZ_mm: 1; Value2: 0.1W; SizeArea_mm2: 1.28; AEC Qualified: N; VDC_V: 75V; AEC Category: Q200; SizeAreaWB_mm2: 4.68
R101 = CMP-0025877-3: RES, 1.5 k, 5%, 0.1 W, AEC-Q200 Grade 0, 0603; Manufacturer: Panasonic; Power_W: 100mW; TempCo: 200 ppm/C; Value_Code: 1k50; U/M: EA; Value: 1.5k; EIA_Code: E24; SizeX_mm: 1.6; SizeY_mm: 0.8; SizeZ_mm: 1; Value2: 0.1W; SizeArea_mm2: 1.28; AEC Qualified: Y; VDC_V: 75V; AEC Grade: 0; AEC Category: Q200
R102 = CMP-0025936-5: RES, 680, 5%, 0.1 W, 0603; Manufacturer: Yageo; Power_W: 100mW; TempCo: 100 ppm/C; Value_Code: 680R; Value: 680; EIA_Code: E24; SizeX_mm: 1.6; SizeY_mm: 0.8; SizeZ_mm: 1; Value2: 0.1W; SizeArea_mm2: 1.28; AEC Qualified: N; VDC_V: 75V; AEC Category: Q200; SizeAreaWB_mm2: 4.68
R103 = CMP-0023638-3: RES, 105 k, 0.1%, 0.1 W, 0603; Manufacturer: Yageo America; Power_W: 100mW; TempCo: 25 ppm/C; U/M: EA; Value: 105k; EIA_Code: E192; SizeX_mm: 1.6; SizeY_mm: 0.8; SizeZ_mm: 1; Value2: 0.1W; SizeArea_mm2: 1.28; VDC_V: 75V; AEC Category: Q200
R104 R105 = CMP-0023404-1: RES, 10.0 k, 0.1%, 0.1 W, 0603; Manufacturer: Susumu Co Ltd; Power_W: 100mW; TempCo: 25 ppm/C; Value_Code: 10k0; U/M: EA; Value: 10.0k; EIA_Code: E192; Res_ohm: 10k; SizeX_mm: 1.6; SizeY_mm: 0.8; SizeZ_mm: 1; Value2: 0.1W; SizeArea_mm2: 1.28; VDC_V: 75V; AEC Category: Q200
R106 = CMP-0024922-3: RES, 20.0 k, 0.5%, 0.1 W, 0603; Manufacturer: Yageo America; Power_W: 100mW; TempCo: 50 ppm/C; Value_Code: 20k0; U/M: EA; Value: 20.0k; EIA_Code: E192; Res_ohm: 20k; SizeX_mm: 1.6; SizeY_mm: 0.8; SizeZ_mm: 1; Value2: 0.1W; SizeArea_mm2: 1.28; VDC_V: 75V; AEC Category: Q200
R107 = CMP-0025733-4: RES, 1.5 k, 5%, 0.1 W, AEC-Q200 Grade 0, 0603; Manufacturer: Vishay-Dale; Power_W: 100mW; TempCo: 200 ppm/C; Value_Code: 1k50; Value: 1.5k; EIA_Code: E24; SizeX_mm: 1.6; SizeY_mm: 0.8; SizeZ_mm: 1; Value2: 0.1W; SizeArea_mm2: 1.28; AEC Qualified: Y; VDC_V: 75V; AEC Category: Q200; AEC Grade: 0
R132 = CMP-0089217-1: 100 kOhms 0.25W, 1/4W Gull Wing Surface Mount Trimmer Potentiometer Cermet 12 Turn Top Adjustment; Manufacturer: Bourns; TempCo: 100ppm/°C; Tolerance_%: 10%; SizeZ_mm: 8.96mm; Res_ohm: 100k; AEC Qualified: No; Power_W: 250mW
TP2 TP14 = CMP-0055138-2: Test Point, Miniature, Black, TH; Manufacturer: Keystone Electronics; ContactFinish: Silver; CNHeader: FALSE; Green_Lifecycle: Active; Green_REACh: Passed; CT: TRUE
TP8 = CMP-0055140-2: Test Point, Miniature, Orange, TH; Manufacturer: Keystone Electronics; Green_Lifecycle: Active; ContactFinish: Silver; CNHeader: FALSE; CT: TRUE; Green_REACh: Passed
TP13 = CMP-0055142-2: Test Point, Compact, Red, TH; Manufacturer: Keystone Electronics; Green_REACh: Passed; CT: TRUE; ContactFinish: Silver; CNHeader: FALSE; Green_Lifecycle: Active
TP23 = CMP-0003968-1: Test Point, SMT; Manufacturer: Harwin
U17 = CMP-0067230-2: Constant-Voltage, Constant-Current PWM Controller with Primary-Side Regulation, D0007A (SOIC-7); Alternate Manufacturer: Texas Instruments; SizeAreaWB_mm2: 55.2; U/M: EA; SizeZ_mm: 1.75; SizeX_mm: 6.0; SizeY_mm: 4.9; SizeArea_mm2: 29.4; CompType: IC; AEC Category: Q200; AEC Qualified: N
U18 = CMP-0067067-1: 17V Input, 500mA Synchronous Step-Down Regulator in SOT-23 with Advanced Eco-Mode(TM), DBV0005A (SOT-23-5); Alternate PartNumber: TPS560200DBVT; Alternate Manufacturer: Texas Instruments; Green_Lifecycle: Active; SizeAreaWB_mm2: 14.82; Green_REACh: Passed; U/M: EA; SizeZ_mm: 1.45; SizeX_mm: 2.8; SizeY_mm: 2.9; SizeArea_mm2: 8.12; CompType: IC
U19 = CMP-0013427-7: 500mA LDO, DRV0006A (WSON-6); Manufacturer: Texas Instruments; SizeX_mm: 2; CompType: IC; SizeZ_mm: 0.8; SizeArea_mm2: 4; SizeAreaWB_mm2: 9; U/M: EA

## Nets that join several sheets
1V65_REF: TIDA-010938 AC-DC_Voltage Measurement (C6.2 C45.2 R23.2 R36.2), TIDA-010938 AC-DC_OpAmp (6 pins)
3V3_HVN: TIDA-010938 AC-DC_Cover Sheet (R5.2), TIDA-010938 AC-DC_Power Stage_BranchA (5 pins), TIDA-010938 AC-DC_Power Stage_BranchB (5 pins), TIDA-010938 AC-DC_EMI Protection Stage (C115.1 FB6.1 R91.1), TIDA-010938 AC-DC_Voltage Measurement (FB12.1 FB14.1), TIDA-010938 AC-DC_Control Stage (12 pins), TIDA-010938 AC-DC_Communication (L12.1 L17.1 R310.2 R318.2), TIDA-010938 AC-DC_OpAmp (C161.2 FB7.1 FB8.1 R166.1), TIDA-010938 AC-DC_Aux Power Supply (C123.2 D18.2 U19.1)
5V_HVN: TIDA-010938 AC-DC_Control Stage (5 pins), TIDA-010938 AC-DC_Communication (L8.1 L16.1), TIDA-010938 AC-DC_Aux Power Supply (9 pins)
12V_HVN: TIDA-010938 AC-DC_Cover Sheet (J6.1), TIDA-010938 AC-DC_Power Stage_BranchA (8 pins), TIDA-010938 AC-DC_Power Stage_BranchB (8 pins), TIDA-010938 AC-DC_EMI Protection Stage (C105.1 D13.1 K1.4 K2.4), TIDA-010938 AC-DC_Control Stage (J10.2), TIDA-010938 AC-DC_Aux Power Supply (12 pins)
DC Bus-: TIDA-010938 AC-DC_Cover Sheet (14 pins), TIDA-010938 AC-DC_Power Stage_BranchA (73 pins), TIDA-010938 AC-DC_Power Stage_BranchB (67 pins), TIDA-010938 AC-DC_EMI Protection Stage (15 pins), TIDA-010938 AC-DC_Voltage Measurement (12 pins), TIDA-010938 AC-DC_Control Stage (87 pins), TIDA-010938 AC-DC_Communication (19 pins), TIDA-010938 AC-DC_OpAmp (25 pins), TIDA-010938 AC-DC_Aux Power Supply (25 pins)
GND_ISO_COMM: TIDA-010938 AC-DC_Cover Sheet (C1.1), TIDA-010938 AC-DC_Communication (30 pins)
PE: TIDA-010938 AC-DC_Cover Sheet (J2.1), TIDA-010938 AC-DC_EMI Protection Stage (R78.1 R81.1 TP6.1), TIDA-010938 AC-DC_Hardware (MP1.1)
PE2: TIDA-010938 AC-DC_Cover Sheet (J31.1), TIDA-010938 AC-DC_EMI Protection Stage (C102.2 C106.1), TIDA-010938 AC-DC_Hardware (MP2.1)
PE3: TIDA-010938 AC-DC_EMI Protection Stage (C243.1 C244.2), TIDA-010938 AC-DC_Hardware (MP4.1)
SW_1: TIDA-010938 AC-DC_Power Stage_BranchA (114 pins), TIDA-010938 AC-DC_EMI Protection Stage (L1.11 L1.12)
SW_2: TIDA-010938 AC-DC_Power Stage_BranchB (113 pins), TIDA-010938 AC-DC_EMI Protection Stage (L4.1 L4.2)
ACLOAD_N: TIDA-010938 AC-DC_EMI Protection Stage (5 pins), TIDA-010938 AC-DC_Voltage Measurement (R122.1)
DC Bus+: TIDA-010938 AC-DC_Power Stage_BranchA (17 pins), TIDA-010938 AC-DC_Power Stage_BranchB (17 pins), TIDA-010938 AC-DC_Aux Power Supply (J7.1 TP13.1)
~{FAULT}_~{OC}_S1: TIDA-010938 AC-DC_Power Stage_BranchA (C37.2 R31.1), TIDA-010938 AC-DC_Control Stage (R204.2)
~{FAULT}_~{OC}_S2_init: TIDA-010938 AC-DC_Power Stage_BranchA (U25.4), TIDA-010938 AC-DC_Control Stage (R203.1)
~{FAULT}_~{OC}_S3: TIDA-010938 AC-DC_Power Stage_BranchB (C83.2 R65.1), TIDA-010938 AC-DC_Control Stage (R206.2)
~{FAULT}_~{OC}_S4_init: TIDA-010938 AC-DC_Power Stage_BranchB (U26.4), TIDA-010938 AC-DC_Control Stage (R205.1)
~{FAULT}_~{OC}_S5: TIDA-010938 AC-DC_Power Stage_BranchA (C36.2 R28.1), TIDA-010938 AC-DC_Control Stage (R207.2)
~{FAULT}_~{OC}_S6: TIDA-010938 AC-DC_Power Stage_BranchB (C82.2 R63.1), TIDA-010938 AC-DC_Control Stage (R208.2)
IAC_~{FAULT}: TIDA-010938 AC-DC_EMI Protection Stage (C113.2 R88.2), TIDA-010938 AC-DC_Control Stage (R229.1)
IAC_~{OC}: TIDA-010938 AC-DC_EMI Protection Stage (C108.2 R87.2), TIDA-010938 AC-DC_Control Stage (R231.1)
IAC_REF: TIDA-010938 AC-DC_EMI Protection Stage (C112.2 R86.1), TIDA-010938 AC-DC_Control Stage (R181.1)
IAC_sense: TIDA-010938 AC-DC_EMI Protection Stage (C107.2 R83.2), TIDA-010938 AC-DC_Control Stage (R180.1)
PWM_S1_Buff: TIDA-010938 AC-DC_Power Stage_BranchA (R22.1), TIDA-010938 AC-DC_Control Stage (J22.1 R21.2 R144.2)
PWM_S2_Buff: TIDA-010938 AC-DC_Power Stage_BranchA (R35.1), TIDA-010938 AC-DC_Control Stage (J4.2 J24.2)
PWM_S3_Buff: TIDA-010938 AC-DC_Power Stage_BranchB (R56.1), TIDA-010938 AC-DC_Control Stage (J14.2 J21.2 J25.2)
PWM_S4_Buff: TIDA-010938 AC-DC_Power Stage_BranchB (R69.1), TIDA-010938 AC-DC_Control Stage (J20.2 J22.2)
PWM_S5_Buff: TIDA-010938 AC-DC_Power Stage_BranchA (R20.1), TIDA-010938 AC-DC_Control Stage (J5.2 J26.2)
PWM_S6_Buff: TIDA-010938 AC-DC_Power Stage_BranchB (R54.1), TIDA-010938 AC-DC_Control Stage (J13.2 J23.2)
RY_PreCharge: TIDA-010938 AC-DC_EMI Protection Stage (R89.1), TIDA-010938 AC-DC_Control Stage (R236.2)
SW_mid: TIDA-010938 AC-DC_Power Stage_BranchA (15 pins), TIDA-010938 AC-DC_Power Stage_BranchB (15 pins)
TEMP_S1: TIDA-010938 AC-DC_Power Stage_BranchA (R26.1), TIDA-010938 AC-DC_Control Stage (C167.2 U23.4)
TEMP_S2_init: TIDA-010938 AC-DC_Power Stage_BranchA (C52.2 R37.1), TIDA-010938 AC-DC_Control Stage (R38.1)
TEMP_S3: TIDA-010938 AC-DC_Power Stage_BranchB (R61.1), TIDA-010938 AC-DC_Control Stage (C170.2 U23.2)
TEMP_S4_init: TIDA-010938 AC-DC_Power Stage_BranchB (C98.2 R71.1), TIDA-010938 AC-DC_Control Stage (R72.1)
TEMP_S5: TIDA-010938 AC-DC_Power Stage_BranchA (R24.1), TIDA-010938 AC-DC_Control Stage (C172.2 U23.15)
TEMP_S6: TIDA-010938 AC-DC_Power Stage_BranchB (R58.1), TIDA-010938 AC-DC_Control Stage (C173.2 U23.14)
VAC_L: TIDA-010938 AC-DC_EMI Protection Stage (K1.3 L11.EII R75.1), TIDA-010938 AC-DC_Voltage Measurement (R116.1)
VAC_N: TIDA-010938 AC-DC_EMI Protection Stage (K2.2 L11.EI R114.1), TIDA-010938 AC-DC_Voltage Measurement (R127.1)
VAC_sense: TIDA-010938 AC-DC_Voltage Measurement (C132.2 R120.2), TIDA-010938 AC-DC_Control Stage (R178.1)
VAC_SW+: TIDA-010938 AC-DC_EMI Protection Stage (C102.1 C104.2 L10.EII U16.1), TIDA-010938 AC-DC_Voltage Measurement (R111.1)
VDC_sense: TIDA-010938 AC-DC_Voltage Measurement (C133.2 R1.2), TIDA-010938 AC-DC_Control Stage (R174.2)
Vinv_sense: TIDA-010938 AC-DC_Voltage Measurement (C134.2 R121.2), TIDA-010938 AC-DC_Control Stage (R176.1)
VS_DCDC_VDC+: TIDA-010938 AC-DC_Voltage Measurement (R135.2), TIDA-010938 AC-DC_Control Stage (J12.18)
VS_DCDC_VDC-: TIDA-010938 AC-DC_Voltage Measurement (R238.2), TIDA-010938 AC-DC_Control Stage (J12.20)
VS_DCDC_VDC_sense: TIDA-010938 AC-DC_Voltage Measurement (C92.2 R134.2), TIDA-010938 AC-DC_Control Stage (R67.2)

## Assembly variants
001: not fitted C52 C98 D1 D1 D7 D7 FID1 FID2 FID3 J27 L1 L4 R7 R7 R21 R41 R41 R53 R53 R55 R55 R240 R240 R241 R241 R242 R242 R243 R243 R244 R244 R245 R245 R246 R246 R247 R247 R248 R248 R249 R249 R250 R250 R251 R251 R? R? R? R? R? R? R? R? R? R? R? R?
